VERSION 5.7 ;
BUSBITCHARS "[]" ;
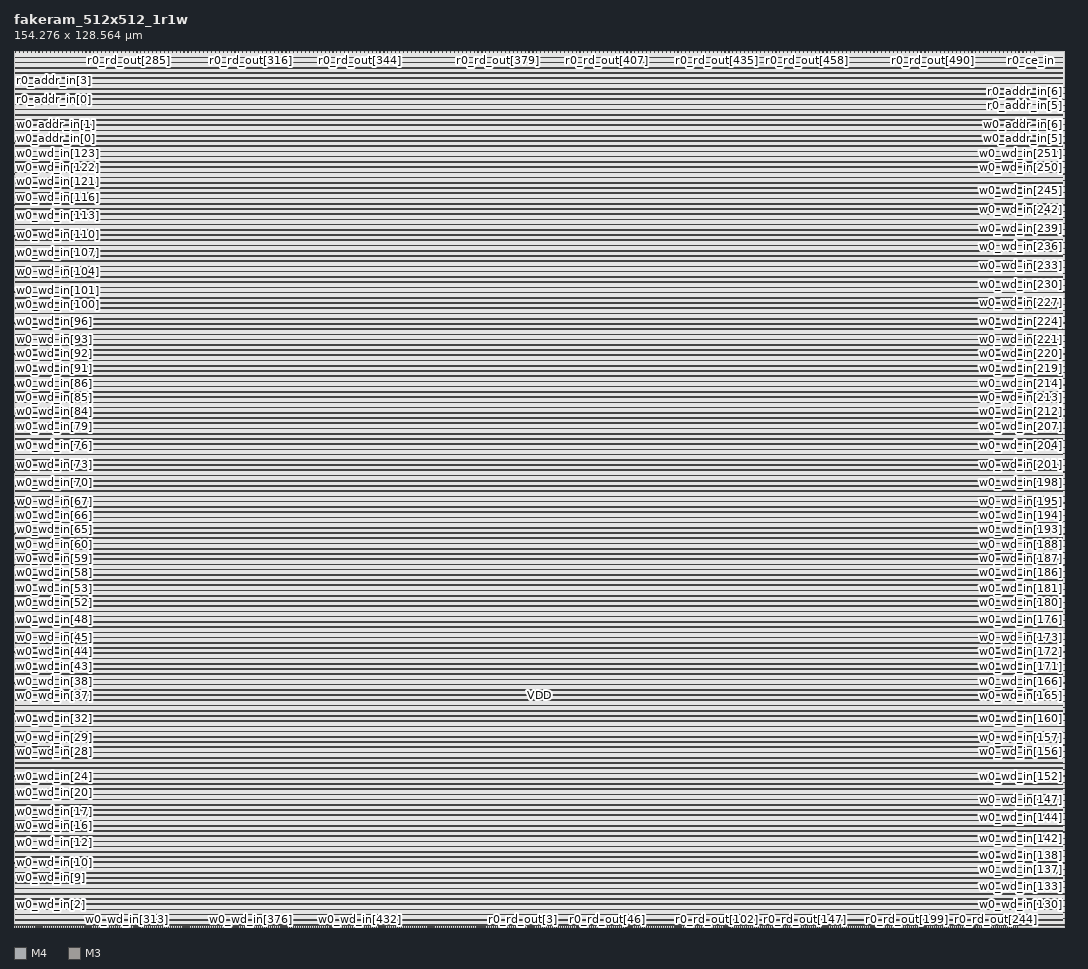
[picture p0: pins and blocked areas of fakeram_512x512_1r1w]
MACRO fakeram_512x512_1r1w
  FOREIGN fakeram_512x512_1r1w 0 0 ;
  SYMMETRY X Y R90 ;
  SIZE 154.276 BY 128.564 ;
  CLASS BLOCK ;
  PIN w0_wd_in[0]
    DIRECTION INPUT ;
    USE SIGNAL ;
    SHAPE ABUTMENT ;
    PORT
      LAYER M4 ;
      RECT 0.000 0.276 0.072 0.300 ;
    END
  END w0_wd_in[0]
  PIN w0_wd_in[1]
    DIRECTION INPUT ;
    USE SIGNAL ;
    SHAPE ABUTMENT ;
    PORT
      LAYER M4 ;
      RECT 0.000 1.188 0.072 1.212 ;
    END
  END w0_wd_in[1]
  PIN w0_wd_in[2]
    DIRECTION INPUT ;
    USE SIGNAL ;
    SHAPE ABUTMENT ;
    PORT
      LAYER M4 ;
      RECT 0.000 2.100 0.072 2.124 ;
    END
  END w0_wd_in[2]
  PIN w0_wd_in[3]
    DIRECTION INPUT ;
    USE SIGNAL ;
    SHAPE ABUTMENT ;
    PORT
      LAYER M4 ;
      RECT 0.000 3.012 0.072 3.036 ;
    END
  END w0_wd_in[3]
  PIN w0_wd_in[4]
    DIRECTION INPUT ;
    USE SIGNAL ;
    SHAPE ABUTMENT ;
    PORT
      LAYER M4 ;
      RECT 0.000 3.924 0.072 3.948 ;
    END
  END w0_wd_in[4]
  PIN w0_wd_in[5]
    DIRECTION INPUT ;
    USE SIGNAL ;
    SHAPE ABUTMENT ;
    PORT
      LAYER M4 ;
      RECT 0.000 4.836 0.072 4.860 ;
    END
  END w0_wd_in[5]
  PIN w0_wd_in[6]
    DIRECTION INPUT ;
    USE SIGNAL ;
    SHAPE ABUTMENT ;
    PORT
      LAYER M4 ;
      RECT 0.000 5.748 0.072 5.772 ;
    END
  END w0_wd_in[6]
  PIN w0_wd_in[7]
    DIRECTION INPUT ;
    USE SIGNAL ;
    SHAPE ABUTMENT ;
    PORT
      LAYER M4 ;
      RECT 0.000 6.660 0.072 6.684 ;
    END
  END w0_wd_in[7]
  PIN w0_wd_in[8]
    DIRECTION INPUT ;
    USE SIGNAL ;
    SHAPE ABUTMENT ;
    PORT
      LAYER M4 ;
      RECT 0.000 7.572 0.072 7.596 ;
    END
  END w0_wd_in[8]
  PIN w0_wd_in[9]
    DIRECTION INPUT ;
    USE SIGNAL ;
    SHAPE ABUTMENT ;
    PORT
      LAYER M4 ;
      RECT 0.000 8.484 0.072 8.508 ;
    END
  END w0_wd_in[9]
  PIN w0_wd_in[10]
    DIRECTION INPUT ;
    USE SIGNAL ;
    SHAPE ABUTMENT ;
    PORT
      LAYER M4 ;
      RECT 0.000 9.396 0.072 9.420 ;
    END
  END w0_wd_in[10]
  PIN w0_wd_in[11]
    DIRECTION INPUT ;
    USE SIGNAL ;
    SHAPE ABUTMENT ;
    PORT
      LAYER M4 ;
      RECT 0.000 10.308 0.072 10.332 ;
    END
  END w0_wd_in[11]
  PIN w0_wd_in[12]
    DIRECTION INPUT ;
    USE SIGNAL ;
    SHAPE ABUTMENT ;
    PORT
      LAYER M4 ;
      RECT 0.000 11.220 0.072 11.244 ;
    END
  END w0_wd_in[12]
  PIN w0_wd_in[13]
    DIRECTION INPUT ;
    USE SIGNAL ;
    SHAPE ABUTMENT ;
    PORT
      LAYER M4 ;
      RECT 0.000 12.132 0.072 12.156 ;
    END
  END w0_wd_in[13]
  PIN w0_wd_in[14]
    DIRECTION INPUT ;
    USE SIGNAL ;
    SHAPE ABUTMENT ;
    PORT
      LAYER M4 ;
      RECT 0.000 13.044 0.072 13.068 ;
    END
  END w0_wd_in[14]
  PIN w0_wd_in[15]
    DIRECTION INPUT ;
    USE SIGNAL ;
    SHAPE ABUTMENT ;
    PORT
      LAYER M4 ;
      RECT 0.000 13.956 0.072 13.980 ;
    END
  END w0_wd_in[15]
  PIN w0_wd_in[16]
    DIRECTION INPUT ;
    USE SIGNAL ;
    SHAPE ABUTMENT ;
    PORT
      LAYER M4 ;
      RECT 0.000 14.868 0.072 14.892 ;
    END
  END w0_wd_in[16]
  PIN w0_wd_in[17]
    DIRECTION INPUT ;
    USE SIGNAL ;
    SHAPE ABUTMENT ;
    PORT
      LAYER M4 ;
      RECT 0.000 15.780 0.072 15.804 ;
    END
  END w0_wd_in[17]
  PIN w0_wd_in[18]
    DIRECTION INPUT ;
    USE SIGNAL ;
    SHAPE ABUTMENT ;
    PORT
      LAYER M4 ;
      RECT 0.000 16.692 0.072 16.716 ;
    END
  END w0_wd_in[18]
  PIN w0_wd_in[19]
    DIRECTION INPUT ;
    USE SIGNAL ;
    SHAPE ABUTMENT ;
    PORT
      LAYER M4 ;
      RECT 0.000 17.604 0.072 17.628 ;
    END
  END w0_wd_in[19]
  PIN w0_wd_in[20]
    DIRECTION INPUT ;
    USE SIGNAL ;
    SHAPE ABUTMENT ;
    PORT
      LAYER M4 ;
      RECT 0.000 18.516 0.072 18.540 ;
    END
  END w0_wd_in[20]
  PIN w0_wd_in[21]
    DIRECTION INPUT ;
    USE SIGNAL ;
    SHAPE ABUTMENT ;
    PORT
      LAYER M4 ;
      RECT 0.000 19.428 0.072 19.452 ;
    END
  END w0_wd_in[21]
  PIN w0_wd_in[22]
    DIRECTION INPUT ;
    USE SIGNAL ;
    SHAPE ABUTMENT ;
    PORT
      LAYER M4 ;
      RECT 0.000 20.340 0.072 20.364 ;
    END
  END w0_wd_in[22]
  PIN w0_wd_in[23]
    DIRECTION INPUT ;
    USE SIGNAL ;
    SHAPE ABUTMENT ;
    PORT
      LAYER M4 ;
      RECT 0.000 21.252 0.072 21.276 ;
    END
  END w0_wd_in[23]
  PIN w0_wd_in[24]
    DIRECTION INPUT ;
    USE SIGNAL ;
    SHAPE ABUTMENT ;
    PORT
      LAYER M4 ;
      RECT 0.000 22.164 0.072 22.188 ;
    END
  END w0_wd_in[24]
  PIN w0_wd_in[25]
    DIRECTION INPUT ;
    USE SIGNAL ;
    SHAPE ABUTMENT ;
    PORT
      LAYER M4 ;
      RECT 0.000 23.076 0.072 23.100 ;
    END
  END w0_wd_in[25]
  PIN w0_wd_in[26]
    DIRECTION INPUT ;
    USE SIGNAL ;
    SHAPE ABUTMENT ;
    PORT
      LAYER M4 ;
      RECT 0.000 23.988 0.072 24.012 ;
    END
  END w0_wd_in[26]
  PIN w0_wd_in[27]
    DIRECTION INPUT ;
    USE SIGNAL ;
    SHAPE ABUTMENT ;
    PORT
      LAYER M4 ;
      RECT 0.000 24.900 0.072 24.924 ;
    END
  END w0_wd_in[27]
  PIN w0_wd_in[28]
    DIRECTION INPUT ;
    USE SIGNAL ;
    SHAPE ABUTMENT ;
    PORT
      LAYER M4 ;
      RECT 0.000 25.812 0.072 25.836 ;
    END
  END w0_wd_in[28]
  PIN w0_wd_in[29]
    DIRECTION INPUT ;
    USE SIGNAL ;
    SHAPE ABUTMENT ;
    PORT
      LAYER M4 ;
      RECT 0.000 26.724 0.072 26.748 ;
    END
  END w0_wd_in[29]
  PIN w0_wd_in[30]
    DIRECTION INPUT ;
    USE SIGNAL ;
    SHAPE ABUTMENT ;
    PORT
      LAYER M4 ;
      RECT 0.000 27.636 0.072 27.660 ;
    END
  END w0_wd_in[30]
  PIN w0_wd_in[31]
    DIRECTION INPUT ;
    USE SIGNAL ;
    SHAPE ABUTMENT ;
    PORT
      LAYER M4 ;
      RECT 0.000 28.548 0.072 28.572 ;
    END
  END w0_wd_in[31]
  PIN w0_wd_in[32]
    DIRECTION INPUT ;
    USE SIGNAL ;
    SHAPE ABUTMENT ;
    PORT
      LAYER M4 ;
      RECT 0.000 29.460 0.072 29.484 ;
    END
  END w0_wd_in[32]
  PIN w0_wd_in[33]
    DIRECTION INPUT ;
    USE SIGNAL ;
    SHAPE ABUTMENT ;
    PORT
      LAYER M4 ;
      RECT 0.000 30.372 0.072 30.396 ;
    END
  END w0_wd_in[33]
  PIN w0_wd_in[34]
    DIRECTION INPUT ;
    USE SIGNAL ;
    SHAPE ABUTMENT ;
    PORT
      LAYER M4 ;
      RECT 0.000 31.284 0.072 31.308 ;
    END
  END w0_wd_in[34]
  PIN w0_wd_in[35]
    DIRECTION INPUT ;
    USE SIGNAL ;
    SHAPE ABUTMENT ;
    PORT
      LAYER M4 ;
      RECT 0.000 32.196 0.072 32.220 ;
    END
  END w0_wd_in[35]
  PIN w0_wd_in[36]
    DIRECTION INPUT ;
    USE SIGNAL ;
    SHAPE ABUTMENT ;
    PORT
      LAYER M4 ;
      RECT 0.000 33.108 0.072 33.132 ;
    END
  END w0_wd_in[36]
  PIN w0_wd_in[37]
    DIRECTION INPUT ;
    USE SIGNAL ;
    SHAPE ABUTMENT ;
    PORT
      LAYER M4 ;
      RECT 0.000 34.020 0.072 34.044 ;
    END
  END w0_wd_in[37]
  PIN w0_wd_in[38]
    DIRECTION INPUT ;
    USE SIGNAL ;
    SHAPE ABUTMENT ;
    PORT
      LAYER M4 ;
      RECT 0.000 34.932 0.072 34.956 ;
    END
  END w0_wd_in[38]
  PIN w0_wd_in[39]
    DIRECTION INPUT ;
    USE SIGNAL ;
    SHAPE ABUTMENT ;
    PORT
      LAYER M4 ;
      RECT 0.000 35.844 0.072 35.868 ;
    END
  END w0_wd_in[39]
  PIN w0_wd_in[40]
    DIRECTION INPUT ;
    USE SIGNAL ;
    SHAPE ABUTMENT ;
    PORT
      LAYER M4 ;
      RECT 0.000 36.756 0.072 36.780 ;
    END
  END w0_wd_in[40]
  PIN w0_wd_in[41]
    DIRECTION INPUT ;
    USE SIGNAL ;
    SHAPE ABUTMENT ;
    PORT
      LAYER M4 ;
      RECT 0.000 37.668 0.072 37.692 ;
    END
  END w0_wd_in[41]
  PIN w0_wd_in[42]
    DIRECTION INPUT ;
    USE SIGNAL ;
    SHAPE ABUTMENT ;
    PORT
      LAYER M4 ;
      RECT 0.000 38.580 0.072 38.604 ;
    END
  END w0_wd_in[42]
  PIN w0_wd_in[43]
    DIRECTION INPUT ;
    USE SIGNAL ;
    SHAPE ABUTMENT ;
    PORT
      LAYER M4 ;
      RECT 0.000 39.492 0.072 39.516 ;
    END
  END w0_wd_in[43]
  PIN w0_wd_in[44]
    DIRECTION INPUT ;
    USE SIGNAL ;
    SHAPE ABUTMENT ;
    PORT
      LAYER M4 ;
      RECT 0.000 40.404 0.072 40.428 ;
    END
  END w0_wd_in[44]
  PIN w0_wd_in[45]
    DIRECTION INPUT ;
    USE SIGNAL ;
    SHAPE ABUTMENT ;
    PORT
      LAYER M4 ;
      RECT 0.000 41.316 0.072 41.340 ;
    END
  END w0_wd_in[45]
  PIN w0_wd_in[46]
    DIRECTION INPUT ;
    USE SIGNAL ;
    SHAPE ABUTMENT ;
    PORT
      LAYER M4 ;
      RECT 0.000 42.228 0.072 42.252 ;
    END
  END w0_wd_in[46]
  PIN w0_wd_in[47]
    DIRECTION INPUT ;
    USE SIGNAL ;
    SHAPE ABUTMENT ;
    PORT
      LAYER M4 ;
      RECT 0.000 43.140 0.072 43.164 ;
    END
  END w0_wd_in[47]
  PIN w0_wd_in[48]
    DIRECTION INPUT ;
    USE SIGNAL ;
    SHAPE ABUTMENT ;
    PORT
      LAYER M4 ;
      RECT 0.000 44.052 0.072 44.076 ;
    END
  END w0_wd_in[48]
  PIN w0_wd_in[49]
    DIRECTION INPUT ;
    USE SIGNAL ;
    SHAPE ABUTMENT ;
    PORT
      LAYER M4 ;
      RECT 0.000 44.964 0.072 44.988 ;
    END
  END w0_wd_in[49]
  PIN w0_wd_in[50]
    DIRECTION INPUT ;
    USE SIGNAL ;
    SHAPE ABUTMENT ;
    PORT
      LAYER M4 ;
      RECT 0.000 45.876 0.072 45.900 ;
    END
  END w0_wd_in[50]
  PIN w0_wd_in[51]
    DIRECTION INPUT ;
    USE SIGNAL ;
    SHAPE ABUTMENT ;
    PORT
      LAYER M4 ;
      RECT 0.000 46.788 0.072 46.812 ;
    END
  END w0_wd_in[51]
  PIN w0_wd_in[52]
    DIRECTION INPUT ;
    USE SIGNAL ;
    SHAPE ABUTMENT ;
    PORT
      LAYER M4 ;
      RECT 0.000 47.700 0.072 47.724 ;
    END
  END w0_wd_in[52]
  PIN w0_wd_in[53]
    DIRECTION INPUT ;
    USE SIGNAL ;
    SHAPE ABUTMENT ;
    PORT
      LAYER M4 ;
      RECT 0.000 48.612 0.072 48.636 ;
    END
  END w0_wd_in[53]
  PIN w0_wd_in[54]
    DIRECTION INPUT ;
    USE SIGNAL ;
    SHAPE ABUTMENT ;
    PORT
      LAYER M4 ;
      RECT 0.000 49.524 0.072 49.548 ;
    END
  END w0_wd_in[54]
  PIN w0_wd_in[55]
    DIRECTION INPUT ;
    USE SIGNAL ;
    SHAPE ABUTMENT ;
    PORT
      LAYER M4 ;
      RECT 0.000 50.436 0.072 50.460 ;
    END
  END w0_wd_in[55]
  PIN w0_wd_in[56]
    DIRECTION INPUT ;
    USE SIGNAL ;
    SHAPE ABUTMENT ;
    PORT
      LAYER M4 ;
      RECT 0.000 51.348 0.072 51.372 ;
    END
  END w0_wd_in[56]
  PIN w0_wd_in[57]
    DIRECTION INPUT ;
    USE SIGNAL ;
    SHAPE ABUTMENT ;
    PORT
      LAYER M4 ;
      RECT 0.000 52.260 0.072 52.284 ;
    END
  END w0_wd_in[57]
  PIN w0_wd_in[58]
    DIRECTION INPUT ;
    USE SIGNAL ;
    SHAPE ABUTMENT ;
    PORT
      LAYER M4 ;
      RECT 0.000 53.172 0.072 53.196 ;
    END
  END w0_wd_in[58]
  PIN w0_wd_in[59]
    DIRECTION INPUT ;
    USE SIGNAL ;
    SHAPE ABUTMENT ;
    PORT
      LAYER M4 ;
      RECT 0.000 54.084 0.072 54.108 ;
    END
  END w0_wd_in[59]
  PIN w0_wd_in[60]
    DIRECTION INPUT ;
    USE SIGNAL ;
    SHAPE ABUTMENT ;
    PORT
      LAYER M4 ;
      RECT 0.000 54.996 0.072 55.020 ;
    END
  END w0_wd_in[60]
  PIN w0_wd_in[61]
    DIRECTION INPUT ;
    USE SIGNAL ;
    SHAPE ABUTMENT ;
    PORT
      LAYER M4 ;
      RECT 0.000 55.908 0.072 55.932 ;
    END
  END w0_wd_in[61]
  PIN w0_wd_in[62]
    DIRECTION INPUT ;
    USE SIGNAL ;
    SHAPE ABUTMENT ;
    PORT
      LAYER M4 ;
      RECT 0.000 56.820 0.072 56.844 ;
    END
  END w0_wd_in[62]
  PIN w0_wd_in[63]
    DIRECTION INPUT ;
    USE SIGNAL ;
    SHAPE ABUTMENT ;
    PORT
      LAYER M4 ;
      RECT 0.000 57.732 0.072 57.756 ;
    END
  END w0_wd_in[63]
  PIN w0_wd_in[64]
    DIRECTION INPUT ;
    USE SIGNAL ;
    SHAPE ABUTMENT ;
    PORT
      LAYER M4 ;
      RECT 0.000 58.644 0.072 58.668 ;
    END
  END w0_wd_in[64]
  PIN w0_wd_in[65]
    DIRECTION INPUT ;
    USE SIGNAL ;
    SHAPE ABUTMENT ;
    PORT
      LAYER M4 ;
      RECT 0.000 59.556 0.072 59.580 ;
    END
  END w0_wd_in[65]
  PIN w0_wd_in[66]
    DIRECTION INPUT ;
    USE SIGNAL ;
    SHAPE ABUTMENT ;
    PORT
      LAYER M4 ;
      RECT 0.000 60.468 0.072 60.492 ;
    END
  END w0_wd_in[66]
  PIN w0_wd_in[67]
    DIRECTION INPUT ;
    USE SIGNAL ;
    SHAPE ABUTMENT ;
    PORT
      LAYER M4 ;
      RECT 0.000 61.380 0.072 61.404 ;
    END
  END w0_wd_in[67]
  PIN w0_wd_in[68]
    DIRECTION INPUT ;
    USE SIGNAL ;
    SHAPE ABUTMENT ;
    PORT
      LAYER M4 ;
      RECT 0.000 62.292 0.072 62.316 ;
    END
  END w0_wd_in[68]
  PIN w0_wd_in[69]
    DIRECTION INPUT ;
    USE SIGNAL ;
    SHAPE ABUTMENT ;
    PORT
      LAYER M4 ;
      RECT 0.000 63.204 0.072 63.228 ;
    END
  END w0_wd_in[69]
  PIN w0_wd_in[70]
    DIRECTION INPUT ;
    USE SIGNAL ;
    SHAPE ABUTMENT ;
    PORT
      LAYER M4 ;
      RECT 0.000 64.116 0.072 64.140 ;
    END
  END w0_wd_in[70]
  PIN w0_wd_in[71]
    DIRECTION INPUT ;
    USE SIGNAL ;
    SHAPE ABUTMENT ;
    PORT
      LAYER M4 ;
      RECT 0.000 65.028 0.072 65.052 ;
    END
  END w0_wd_in[71]
  PIN w0_wd_in[72]
    DIRECTION INPUT ;
    USE SIGNAL ;
    SHAPE ABUTMENT ;
    PORT
      LAYER M4 ;
      RECT 0.000 65.940 0.072 65.964 ;
    END
  END w0_wd_in[72]
  PIN w0_wd_in[73]
    DIRECTION INPUT ;
    USE SIGNAL ;
    SHAPE ABUTMENT ;
    PORT
      LAYER M4 ;
      RECT 0.000 66.852 0.072 66.876 ;
    END
  END w0_wd_in[73]
  PIN w0_wd_in[74]
    DIRECTION INPUT ;
    USE SIGNAL ;
    SHAPE ABUTMENT ;
    PORT
      LAYER M4 ;
      RECT 0.000 67.764 0.072 67.788 ;
    END
  END w0_wd_in[74]
  PIN w0_wd_in[75]
    DIRECTION INPUT ;
    USE SIGNAL ;
    SHAPE ABUTMENT ;
    PORT
      LAYER M4 ;
      RECT 0.000 68.676 0.072 68.700 ;
    END
  END w0_wd_in[75]
  PIN w0_wd_in[76]
    DIRECTION INPUT ;
    USE SIGNAL ;
    SHAPE ABUTMENT ;
    PORT
      LAYER M4 ;
      RECT 0.000 69.588 0.072 69.612 ;
    END
  END w0_wd_in[76]
  PIN w0_wd_in[77]
    DIRECTION INPUT ;
    USE SIGNAL ;
    SHAPE ABUTMENT ;
    PORT
      LAYER M4 ;
      RECT 0.000 70.500 0.072 70.524 ;
    END
  END w0_wd_in[77]
  PIN w0_wd_in[78]
    DIRECTION INPUT ;
    USE SIGNAL ;
    SHAPE ABUTMENT ;
    PORT
      LAYER M4 ;
      RECT 0.000 71.412 0.072 71.436 ;
    END
  END w0_wd_in[78]
  PIN w0_wd_in[79]
    DIRECTION INPUT ;
    USE SIGNAL ;
    SHAPE ABUTMENT ;
    PORT
      LAYER M4 ;
      RECT 0.000 72.324 0.072 72.348 ;
    END
  END w0_wd_in[79]
  PIN w0_wd_in[80]
    DIRECTION INPUT ;
    USE SIGNAL ;
    SHAPE ABUTMENT ;
    PORT
      LAYER M4 ;
      RECT 0.000 73.236 0.072 73.260 ;
    END
  END w0_wd_in[80]
  PIN w0_wd_in[81]
    DIRECTION INPUT ;
    USE SIGNAL ;
    SHAPE ABUTMENT ;
    PORT
      LAYER M4 ;
      RECT 0.000 74.148 0.072 74.172 ;
    END
  END w0_wd_in[81]
  PIN w0_wd_in[82]
    DIRECTION INPUT ;
    USE SIGNAL ;
    SHAPE ABUTMENT ;
    PORT
      LAYER M4 ;
      RECT 0.000 75.060 0.072 75.084 ;
    END
  END w0_wd_in[82]
  PIN w0_wd_in[83]
    DIRECTION INPUT ;
    USE SIGNAL ;
    SHAPE ABUTMENT ;
    PORT
      LAYER M4 ;
      RECT 0.000 75.972 0.072 75.996 ;
    END
  END w0_wd_in[83]
  PIN w0_wd_in[84]
    DIRECTION INPUT ;
    USE SIGNAL ;
    SHAPE ABUTMENT ;
    PORT
      LAYER M4 ;
      RECT 0.000 76.884 0.072 76.908 ;
    END
  END w0_wd_in[84]
  PIN w0_wd_in[85]
    DIRECTION INPUT ;
    USE SIGNAL ;
    SHAPE ABUTMENT ;
    PORT
      LAYER M4 ;
      RECT 0.000 77.796 0.072 77.820 ;
    END
  END w0_wd_in[85]
  PIN w0_wd_in[86]
    DIRECTION INPUT ;
    USE SIGNAL ;
    SHAPE ABUTMENT ;
    PORT
      LAYER M4 ;
      RECT 0.000 78.708 0.072 78.732 ;
    END
  END w0_wd_in[86]
  PIN w0_wd_in[87]
    DIRECTION INPUT ;
    USE SIGNAL ;
    SHAPE ABUTMENT ;
    PORT
      LAYER M4 ;
      RECT 0.000 79.620 0.072 79.644 ;
    END
  END w0_wd_in[87]
  PIN w0_wd_in[88]
    DIRECTION INPUT ;
    USE SIGNAL ;
    SHAPE ABUTMENT ;
    PORT
      LAYER M4 ;
      RECT 0.000 80.532 0.072 80.556 ;
    END
  END w0_wd_in[88]
  PIN w0_wd_in[89]
    DIRECTION INPUT ;
    USE SIGNAL ;
    SHAPE ABUTMENT ;
    PORT
      LAYER M4 ;
      RECT 0.000 81.444 0.072 81.468 ;
    END
  END w0_wd_in[89]
  PIN w0_wd_in[90]
    DIRECTION INPUT ;
    USE SIGNAL ;
    SHAPE ABUTMENT ;
    PORT
      LAYER M4 ;
      RECT 0.000 82.356 0.072 82.380 ;
    END
  END w0_wd_in[90]
  PIN w0_wd_in[91]
    DIRECTION INPUT ;
    USE SIGNAL ;
    SHAPE ABUTMENT ;
    PORT
      LAYER M4 ;
      RECT 0.000 83.268 0.072 83.292 ;
    END
  END w0_wd_in[91]
  PIN w0_wd_in[92]
    DIRECTION INPUT ;
    USE SIGNAL ;
    SHAPE ABUTMENT ;
    PORT
      LAYER M4 ;
      RECT 0.000 84.180 0.072 84.204 ;
    END
  END w0_wd_in[92]
  PIN w0_wd_in[93]
    DIRECTION INPUT ;
    USE SIGNAL ;
    SHAPE ABUTMENT ;
    PORT
      LAYER M4 ;
      RECT 0.000 85.092 0.072 85.116 ;
    END
  END w0_wd_in[93]
  PIN w0_wd_in[94]
    DIRECTION INPUT ;
    USE SIGNAL ;
    SHAPE ABUTMENT ;
    PORT
      LAYER M4 ;
      RECT 0.000 86.004 0.072 86.028 ;
    END
  END w0_wd_in[94]
  PIN w0_wd_in[95]
    DIRECTION INPUT ;
    USE SIGNAL ;
    SHAPE ABUTMENT ;
    PORT
      LAYER M4 ;
      RECT 0.000 86.916 0.072 86.940 ;
    END
  END w0_wd_in[95]
  PIN w0_wd_in[96]
    DIRECTION INPUT ;
    USE SIGNAL ;
    SHAPE ABUTMENT ;
    PORT
      LAYER M4 ;
      RECT 0.000 87.828 0.072 87.852 ;
    END
  END w0_wd_in[96]
  PIN w0_wd_in[97]
    DIRECTION INPUT ;
    USE SIGNAL ;
    SHAPE ABUTMENT ;
    PORT
      LAYER M4 ;
      RECT 0.000 88.740 0.072 88.764 ;
    END
  END w0_wd_in[97]
  PIN w0_wd_in[98]
    DIRECTION INPUT ;
    USE SIGNAL ;
    SHAPE ABUTMENT ;
    PORT
      LAYER M4 ;
      RECT 0.000 89.652 0.072 89.676 ;
    END
  END w0_wd_in[98]
  PIN w0_wd_in[99]
    DIRECTION INPUT ;
    USE SIGNAL ;
    SHAPE ABUTMENT ;
    PORT
      LAYER M4 ;
      RECT 0.000 90.564 0.072 90.588 ;
    END
  END w0_wd_in[99]
  PIN w0_wd_in[100]
    DIRECTION INPUT ;
    USE SIGNAL ;
    SHAPE ABUTMENT ;
    PORT
      LAYER M4 ;
      RECT 0.000 91.476 0.072 91.500 ;
    END
  END w0_wd_in[100]
  PIN w0_wd_in[101]
    DIRECTION INPUT ;
    USE SIGNAL ;
    SHAPE ABUTMENT ;
    PORT
      LAYER M4 ;
      RECT 0.000 92.388 0.072 92.412 ;
    END
  END w0_wd_in[101]
  PIN w0_wd_in[102]
    DIRECTION INPUT ;
    USE SIGNAL ;
    SHAPE ABUTMENT ;
    PORT
      LAYER M4 ;
      RECT 0.000 93.300 0.072 93.324 ;
    END
  END w0_wd_in[102]
  PIN w0_wd_in[103]
    DIRECTION INPUT ;
    USE SIGNAL ;
    SHAPE ABUTMENT ;
    PORT
      LAYER M4 ;
      RECT 0.000 94.212 0.072 94.236 ;
    END
  END w0_wd_in[103]
  PIN w0_wd_in[104]
    DIRECTION INPUT ;
    USE SIGNAL ;
    SHAPE ABUTMENT ;
    PORT
      LAYER M4 ;
      RECT 0.000 95.124 0.072 95.148 ;
    END
  END w0_wd_in[104]
  PIN w0_wd_in[105]
    DIRECTION INPUT ;
    USE SIGNAL ;
    SHAPE ABUTMENT ;
    PORT
      LAYER M4 ;
      RECT 0.000 96.036 0.072 96.060 ;
    END
  END w0_wd_in[105]
  PIN w0_wd_in[106]
    DIRECTION INPUT ;
    USE SIGNAL ;
    SHAPE ABUTMENT ;
    PORT
      LAYER M4 ;
      RECT 0.000 96.948 0.072 96.972 ;
    END
  END w0_wd_in[106]
  PIN w0_wd_in[107]
    DIRECTION INPUT ;
    USE SIGNAL ;
    SHAPE ABUTMENT ;
    PORT
      LAYER M4 ;
      RECT 0.000 97.860 0.072 97.884 ;
    END
  END w0_wd_in[107]
  PIN w0_wd_in[108]
    DIRECTION INPUT ;
    USE SIGNAL ;
    SHAPE ABUTMENT ;
    PORT
      LAYER M4 ;
      RECT 0.000 98.772 0.072 98.796 ;
    END
  END w0_wd_in[108]
  PIN w0_wd_in[109]
    DIRECTION INPUT ;
    USE SIGNAL ;
    SHAPE ABUTMENT ;
    PORT
      LAYER M4 ;
      RECT 0.000 99.684 0.072 99.708 ;
    END
  END w0_wd_in[109]
  PIN w0_wd_in[110]
    DIRECTION INPUT ;
    USE SIGNAL ;
    SHAPE ABUTMENT ;
    PORT
      LAYER M4 ;
      RECT 0.000 100.596 0.072 100.620 ;
    END
  END w0_wd_in[110]
  PIN w0_wd_in[111]
    DIRECTION INPUT ;
    USE SIGNAL ;
    SHAPE ABUTMENT ;
    PORT
      LAYER M4 ;
      RECT 0.000 101.508 0.072 101.532 ;
    END
  END w0_wd_in[111]
  PIN w0_wd_in[112]
    DIRECTION INPUT ;
    USE SIGNAL ;
    SHAPE ABUTMENT ;
    PORT
      LAYER M4 ;
      RECT 0.000 102.420 0.072 102.444 ;
    END
  END w0_wd_in[112]
  PIN w0_wd_in[113]
    DIRECTION INPUT ;
    USE SIGNAL ;
    SHAPE ABUTMENT ;
    PORT
      LAYER M4 ;
      RECT 0.000 103.332 0.072 103.356 ;
    END
  END w0_wd_in[113]
  PIN w0_wd_in[114]
    DIRECTION INPUT ;
    USE SIGNAL ;
    SHAPE ABUTMENT ;
    PORT
      LAYER M4 ;
      RECT 0.000 104.244 0.072 104.268 ;
    END
  END w0_wd_in[114]
  PIN w0_wd_in[115]
    DIRECTION INPUT ;
    USE SIGNAL ;
    SHAPE ABUTMENT ;
    PORT
      LAYER M4 ;
      RECT 0.000 105.156 0.072 105.180 ;
    END
  END w0_wd_in[115]
  PIN w0_wd_in[116]
    DIRECTION INPUT ;
    USE SIGNAL ;
    SHAPE ABUTMENT ;
    PORT
      LAYER M4 ;
      RECT 0.000 106.068 0.072 106.092 ;
    END
  END w0_wd_in[116]
  PIN w0_wd_in[117]
    DIRECTION INPUT ;
    USE SIGNAL ;
    SHAPE ABUTMENT ;
    PORT
      LAYER M4 ;
      RECT 0.000 106.980 0.072 107.004 ;
    END
  END w0_wd_in[117]
  PIN w0_wd_in[118]
    DIRECTION INPUT ;
    USE SIGNAL ;
    SHAPE ABUTMENT ;
    PORT
      LAYER M4 ;
      RECT 0.000 107.892 0.072 107.916 ;
    END
  END w0_wd_in[118]
  PIN w0_wd_in[119]
    DIRECTION INPUT ;
    USE SIGNAL ;
    SHAPE ABUTMENT ;
    PORT
      LAYER M4 ;
      RECT 0.000 108.804 0.072 108.828 ;
    END
  END w0_wd_in[119]
  PIN w0_wd_in[120]
    DIRECTION INPUT ;
    USE SIGNAL ;
    SHAPE ABUTMENT ;
    PORT
      LAYER M4 ;
      RECT 0.000 109.716 0.072 109.740 ;
    END
  END w0_wd_in[120]
  PIN w0_wd_in[121]
    DIRECTION INPUT ;
    USE SIGNAL ;
    SHAPE ABUTMENT ;
    PORT
      LAYER M4 ;
      RECT 0.000 110.628 0.072 110.652 ;
    END
  END w0_wd_in[121]
  PIN w0_wd_in[122]
    DIRECTION INPUT ;
    USE SIGNAL ;
    SHAPE ABUTMENT ;
    PORT
      LAYER M4 ;
      RECT 0.000 111.540 0.072 111.564 ;
    END
  END w0_wd_in[122]
  PIN w0_wd_in[123]
    DIRECTION INPUT ;
    USE SIGNAL ;
    SHAPE ABUTMENT ;
    PORT
      LAYER M4 ;
      RECT 0.000 112.452 0.072 112.476 ;
    END
  END w0_wd_in[123]
  PIN w0_wd_in[124]
    DIRECTION INPUT ;
    USE SIGNAL ;
    SHAPE ABUTMENT ;
    PORT
      LAYER M4 ;
      RECT 0.000 113.364 0.072 113.388 ;
    END
  END w0_wd_in[124]
  PIN w0_wd_in[125]
    DIRECTION INPUT ;
    USE SIGNAL ;
    SHAPE ABUTMENT ;
    PORT
      LAYER M4 ;
      RECT 0.000 114.276 0.072 114.300 ;
    END
  END w0_wd_in[125]
  PIN w0_wd_in[126]
    DIRECTION INPUT ;
    USE SIGNAL ;
    SHAPE ABUTMENT ;
    PORT
      LAYER M4 ;
      RECT 0.000 115.188 0.072 115.212 ;
    END
  END w0_wd_in[126]
  PIN w0_wd_in[127]
    DIRECTION INPUT ;
    USE SIGNAL ;
    SHAPE ABUTMENT ;
    PORT
      LAYER M4 ;
      RECT 0.000 116.100 0.072 116.124 ;
    END
  END w0_wd_in[127]
  PIN w0_wd_in[128]
    DIRECTION INPUT ;
    USE SIGNAL ;
    SHAPE ABUTMENT ;
    PORT
      LAYER M4 ;
      RECT 154.204 0.276 154.276 0.300 ;
    END
  END w0_wd_in[128]
  PIN w0_wd_in[129]
    DIRECTION INPUT ;
    USE SIGNAL ;
    SHAPE ABUTMENT ;
    PORT
      LAYER M4 ;
      RECT 154.204 1.188 154.276 1.212 ;
    END
  END w0_wd_in[129]
  PIN w0_wd_in[130]
    DIRECTION INPUT ;
    USE SIGNAL ;
    SHAPE ABUTMENT ;
    PORT
      LAYER M4 ;
      RECT 154.204 2.100 154.276 2.124 ;
    END
  END w0_wd_in[130]
  PIN w0_wd_in[131]
    DIRECTION INPUT ;
    USE SIGNAL ;
    SHAPE ABUTMENT ;
    PORT
      LAYER M4 ;
      RECT 154.204 3.012 154.276 3.036 ;
    END
  END w0_wd_in[131]
  PIN w0_wd_in[132]
    DIRECTION INPUT ;
    USE SIGNAL ;
    SHAPE ABUTMENT ;
    PORT
      LAYER M4 ;
      RECT 154.204 3.924 154.276 3.948 ;
    END
  END w0_wd_in[132]
  PIN w0_wd_in[133]
    DIRECTION INPUT ;
    USE SIGNAL ;
    SHAPE ABUTMENT ;
    PORT
      LAYER M4 ;
      RECT 154.204 4.836 154.276 4.860 ;
    END
  END w0_wd_in[133]
  PIN w0_wd_in[134]
    DIRECTION INPUT ;
    USE SIGNAL ;
    SHAPE ABUTMENT ;
    PORT
      LAYER M4 ;
      RECT 154.204 5.748 154.276 5.772 ;
    END
  END w0_wd_in[134]
  PIN w0_wd_in[135]
    DIRECTION INPUT ;
    USE SIGNAL ;
    SHAPE ABUTMENT ;
    PORT
      LAYER M4 ;
      RECT 154.204 6.660 154.276 6.684 ;
    END
  END w0_wd_in[135]
  PIN w0_wd_in[136]
    DIRECTION INPUT ;
    USE SIGNAL ;
    SHAPE ABUTMENT ;
    PORT
      LAYER M4 ;
      RECT 154.204 7.572 154.276 7.596 ;
    END
  END w0_wd_in[136]
  PIN w0_wd_in[137]
    DIRECTION INPUT ;
    USE SIGNAL ;
    SHAPE ABUTMENT ;
    PORT
      LAYER M4 ;
      RECT 154.204 8.484 154.276 8.508 ;
    END
  END w0_wd_in[137]
  PIN w0_wd_in[138]
    DIRECTION INPUT ;
    USE SIGNAL ;
    SHAPE ABUTMENT ;
    PORT
      LAYER M4 ;
      RECT 154.204 9.396 154.276 9.420 ;
    END
  END w0_wd_in[138]
  PIN w0_wd_in[139]
    DIRECTION INPUT ;
    USE SIGNAL ;
    SHAPE ABUTMENT ;
    PORT
      LAYER M4 ;
      RECT 154.204 10.308 154.276 10.332 ;
    END
  END w0_wd_in[139]
  PIN w0_wd_in[140]
    DIRECTION INPUT ;
    USE SIGNAL ;
    SHAPE ABUTMENT ;
    PORT
      LAYER M4 ;
      RECT 154.204 11.220 154.276 11.244 ;
    END
  END w0_wd_in[140]
  PIN w0_wd_in[141]
    DIRECTION INPUT ;
    USE SIGNAL ;
    SHAPE ABUTMENT ;
    PORT
      LAYER M4 ;
      RECT 154.204 12.132 154.276 12.156 ;
    END
  END w0_wd_in[141]
  PIN w0_wd_in[142]
    DIRECTION INPUT ;
    USE SIGNAL ;
    SHAPE ABUTMENT ;
    PORT
      LAYER M4 ;
      RECT 154.204 13.044 154.276 13.068 ;
    END
  END w0_wd_in[142]
  PIN w0_wd_in[143]
    DIRECTION INPUT ;
    USE SIGNAL ;
    SHAPE ABUTMENT ;
    PORT
      LAYER M4 ;
      RECT 154.204 13.956 154.276 13.980 ;
    END
  END w0_wd_in[143]
  PIN w0_wd_in[144]
    DIRECTION INPUT ;
    USE SIGNAL ;
    SHAPE ABUTMENT ;
    PORT
      LAYER M4 ;
      RECT 154.204 14.868 154.276 14.892 ;
    END
  END w0_wd_in[144]
  PIN w0_wd_in[145]
    DIRECTION INPUT ;
    USE SIGNAL ;
    SHAPE ABUTMENT ;
    PORT
      LAYER M4 ;
      RECT 154.204 15.780 154.276 15.804 ;
    END
  END w0_wd_in[145]
  PIN w0_wd_in[146]
    DIRECTION INPUT ;
    USE SIGNAL ;
    SHAPE ABUTMENT ;
    PORT
      LAYER M4 ;
      RECT 154.204 16.692 154.276 16.716 ;
    END
  END w0_wd_in[146]
  PIN w0_wd_in[147]
    DIRECTION INPUT ;
    USE SIGNAL ;
    SHAPE ABUTMENT ;
    PORT
      LAYER M4 ;
      RECT 154.204 17.604 154.276 17.628 ;
    END
  END w0_wd_in[147]
  PIN w0_wd_in[148]
    DIRECTION INPUT ;
    USE SIGNAL ;
    SHAPE ABUTMENT ;
    PORT
      LAYER M4 ;
      RECT 154.204 18.516 154.276 18.540 ;
    END
  END w0_wd_in[148]
  PIN w0_wd_in[149]
    DIRECTION INPUT ;
    USE SIGNAL ;
    SHAPE ABUTMENT ;
    PORT
      LAYER M4 ;
      RECT 154.204 19.428 154.276 19.452 ;
    END
  END w0_wd_in[149]
  PIN w0_wd_in[150]
    DIRECTION INPUT ;
    USE SIGNAL ;
    SHAPE ABUTMENT ;
    PORT
      LAYER M4 ;
      RECT 154.204 20.340 154.276 20.364 ;
    END
  END w0_wd_in[150]
  PIN w0_wd_in[151]
    DIRECTION INPUT ;
    USE SIGNAL ;
    SHAPE ABUTMENT ;
    PORT
      LAYER M4 ;
      RECT 154.204 21.252 154.276 21.276 ;
    END
  END w0_wd_in[151]
  PIN w0_wd_in[152]
    DIRECTION INPUT ;
    USE SIGNAL ;
    SHAPE ABUTMENT ;
    PORT
      LAYER M4 ;
      RECT 154.204 22.164 154.276 22.188 ;
    END
  END w0_wd_in[152]
  PIN w0_wd_in[153]
    DIRECTION INPUT ;
    USE SIGNAL ;
    SHAPE ABUTMENT ;
    PORT
      LAYER M4 ;
      RECT 154.204 23.076 154.276 23.100 ;
    END
  END w0_wd_in[153]
  PIN w0_wd_in[154]
    DIRECTION INPUT ;
    USE SIGNAL ;
    SHAPE ABUTMENT ;
    PORT
      LAYER M4 ;
      RECT 154.204 23.988 154.276 24.012 ;
    END
  END w0_wd_in[154]
  PIN w0_wd_in[155]
    DIRECTION INPUT ;
    USE SIGNAL ;
    SHAPE ABUTMENT ;
    PORT
      LAYER M4 ;
      RECT 154.204 24.900 154.276 24.924 ;
    END
  END w0_wd_in[155]
  PIN w0_wd_in[156]
    DIRECTION INPUT ;
    USE SIGNAL ;
    SHAPE ABUTMENT ;
    PORT
      LAYER M4 ;
      RECT 154.204 25.812 154.276 25.836 ;
    END
  END w0_wd_in[156]
  PIN w0_wd_in[157]
    DIRECTION INPUT ;
    USE SIGNAL ;
    SHAPE ABUTMENT ;
    PORT
      LAYER M4 ;
      RECT 154.204 26.724 154.276 26.748 ;
    END
  END w0_wd_in[157]
  PIN w0_wd_in[158]
    DIRECTION INPUT ;
    USE SIGNAL ;
    SHAPE ABUTMENT ;
    PORT
      LAYER M4 ;
      RECT 154.204 27.636 154.276 27.660 ;
    END
  END w0_wd_in[158]
  PIN w0_wd_in[159]
    DIRECTION INPUT ;
    USE SIGNAL ;
    SHAPE ABUTMENT ;
    PORT
      LAYER M4 ;
      RECT 154.204 28.548 154.276 28.572 ;
    END
  END w0_wd_in[159]
  PIN w0_wd_in[160]
    DIRECTION INPUT ;
    USE SIGNAL ;
    SHAPE ABUTMENT ;
    PORT
      LAYER M4 ;
      RECT 154.204 29.460 154.276 29.484 ;
    END
  END w0_wd_in[160]
  PIN w0_wd_in[161]
    DIRECTION INPUT ;
    USE SIGNAL ;
    SHAPE ABUTMENT ;
    PORT
      LAYER M4 ;
      RECT 154.204 30.372 154.276 30.396 ;
    END
  END w0_wd_in[161]
  PIN w0_wd_in[162]
    DIRECTION INPUT ;
    USE SIGNAL ;
    SHAPE ABUTMENT ;
    PORT
      LAYER M4 ;
      RECT 154.204 31.284 154.276 31.308 ;
    END
  END w0_wd_in[162]
  PIN w0_wd_in[163]
    DIRECTION INPUT ;
    USE SIGNAL ;
    SHAPE ABUTMENT ;
    PORT
      LAYER M4 ;
      RECT 154.204 32.196 154.276 32.220 ;
    END
  END w0_wd_in[163]
  PIN w0_wd_in[164]
    DIRECTION INPUT ;
    USE SIGNAL ;
    SHAPE ABUTMENT ;
    PORT
      LAYER M4 ;
      RECT 154.204 33.108 154.276 33.132 ;
    END
  END w0_wd_in[164]
  PIN w0_wd_in[165]
    DIRECTION INPUT ;
    USE SIGNAL ;
    SHAPE ABUTMENT ;
    PORT
      LAYER M4 ;
      RECT 154.204 34.020 154.276 34.044 ;
    END
  END w0_wd_in[165]
  PIN w0_wd_in[166]
    DIRECTION INPUT ;
    USE SIGNAL ;
    SHAPE ABUTMENT ;
    PORT
      LAYER M4 ;
      RECT 154.204 34.932 154.276 34.956 ;
    END
  END w0_wd_in[166]
  PIN w0_wd_in[167]
    DIRECTION INPUT ;
    USE SIGNAL ;
    SHAPE ABUTMENT ;
    PORT
      LAYER M4 ;
      RECT 154.204 35.844 154.276 35.868 ;
    END
  END w0_wd_in[167]
  PIN w0_wd_in[168]
    DIRECTION INPUT ;
    USE SIGNAL ;
    SHAPE ABUTMENT ;
    PORT
      LAYER M4 ;
      RECT 154.204 36.756 154.276 36.780 ;
    END
  END w0_wd_in[168]
  PIN w0_wd_in[169]
    DIRECTION INPUT ;
    USE SIGNAL ;
    SHAPE ABUTMENT ;
    PORT
      LAYER M4 ;
      RECT 154.204 37.668 154.276 37.692 ;
    END
  END w0_wd_in[169]
  PIN w0_wd_in[170]
    DIRECTION INPUT ;
    USE SIGNAL ;
    SHAPE ABUTMENT ;
    PORT
      LAYER M4 ;
      RECT 154.204 38.580 154.276 38.604 ;
    END
  END w0_wd_in[170]
  PIN w0_wd_in[171]
    DIRECTION INPUT ;
    USE SIGNAL ;
    SHAPE ABUTMENT ;
    PORT
      LAYER M4 ;
      RECT 154.204 39.492 154.276 39.516 ;
    END
  END w0_wd_in[171]
  PIN w0_wd_in[172]
    DIRECTION INPUT ;
    USE SIGNAL ;
    SHAPE ABUTMENT ;
    PORT
      LAYER M4 ;
      RECT 154.204 40.404 154.276 40.428 ;
    END
  END w0_wd_in[172]
  PIN w0_wd_in[173]
    DIRECTION INPUT ;
    USE SIGNAL ;
    SHAPE ABUTMENT ;
    PORT
      LAYER M4 ;
      RECT 154.204 41.316 154.276 41.340 ;
    END
  END w0_wd_in[173]
  PIN w0_wd_in[174]
    DIRECTION INPUT ;
    USE SIGNAL ;
    SHAPE ABUTMENT ;
    PORT
      LAYER M4 ;
      RECT 154.204 42.228 154.276 42.252 ;
    END
  END w0_wd_in[174]
  PIN w0_wd_in[175]
    DIRECTION INPUT ;
    USE SIGNAL ;
    SHAPE ABUTMENT ;
    PORT
      LAYER M4 ;
      RECT 154.204 43.140 154.276 43.164 ;
    END
  END w0_wd_in[175]
  PIN w0_wd_in[176]
    DIRECTION INPUT ;
    USE SIGNAL ;
    SHAPE ABUTMENT ;
    PORT
      LAYER M4 ;
      RECT 154.204 44.052 154.276 44.076 ;
    END
  END w0_wd_in[176]
  PIN w0_wd_in[177]
    DIRECTION INPUT ;
    USE SIGNAL ;
    SHAPE ABUTMENT ;
    PORT
      LAYER M4 ;
      RECT 154.204 44.964 154.276 44.988 ;
    END
  END w0_wd_in[177]
  PIN w0_wd_in[178]
    DIRECTION INPUT ;
    USE SIGNAL ;
    SHAPE ABUTMENT ;
    PORT
      LAYER M4 ;
      RECT 154.204 45.876 154.276 45.900 ;
    END
  END w0_wd_in[178]
  PIN w0_wd_in[179]
    DIRECTION INPUT ;
    USE SIGNAL ;
    SHAPE ABUTMENT ;
    PORT
      LAYER M4 ;
      RECT 154.204 46.788 154.276 46.812 ;
    END
  END w0_wd_in[179]
  PIN w0_wd_in[180]
    DIRECTION INPUT ;
    USE SIGNAL ;
    SHAPE ABUTMENT ;
    PORT
      LAYER M4 ;
      RECT 154.204 47.700 154.276 47.724 ;
    END
  END w0_wd_in[180]
  PIN w0_wd_in[181]
    DIRECTION INPUT ;
    USE SIGNAL ;
    SHAPE ABUTMENT ;
    PORT
      LAYER M4 ;
      RECT 154.204 48.612 154.276 48.636 ;
    END
  END w0_wd_in[181]
  PIN w0_wd_in[182]
    DIRECTION INPUT ;
    USE SIGNAL ;
    SHAPE ABUTMENT ;
    PORT
      LAYER M4 ;
      RECT 154.204 49.524 154.276 49.548 ;
    END
  END w0_wd_in[182]
  PIN w0_wd_in[183]
    DIRECTION INPUT ;
    USE SIGNAL ;
    SHAPE ABUTMENT ;
    PORT
      LAYER M4 ;
      RECT 154.204 50.436 154.276 50.460 ;
    END
  END w0_wd_in[183]
  PIN w0_wd_in[184]
    DIRECTION INPUT ;
    USE SIGNAL ;
    SHAPE ABUTMENT ;
    PORT
      LAYER M4 ;
      RECT 154.204 51.348 154.276 51.372 ;
    END
  END w0_wd_in[184]
  PIN w0_wd_in[185]
    DIRECTION INPUT ;
    USE SIGNAL ;
    SHAPE ABUTMENT ;
    PORT
      LAYER M4 ;
      RECT 154.204 52.260 154.276 52.284 ;
    END
  END w0_wd_in[185]
  PIN w0_wd_in[186]
    DIRECTION INPUT ;
    USE SIGNAL ;
    SHAPE ABUTMENT ;
    PORT
      LAYER M4 ;
      RECT 154.204 53.172 154.276 53.196 ;
    END
  END w0_wd_in[186]
  PIN w0_wd_in[187]
    DIRECTION INPUT ;
    USE SIGNAL ;
    SHAPE ABUTMENT ;
    PORT
      LAYER M4 ;
      RECT 154.204 54.084 154.276 54.108 ;
    END
  END w0_wd_in[187]
  PIN w0_wd_in[188]
    DIRECTION INPUT ;
    USE SIGNAL ;
    SHAPE ABUTMENT ;
    PORT
      LAYER M4 ;
      RECT 154.204 54.996 154.276 55.020 ;
    END
  END w0_wd_in[188]
  PIN w0_wd_in[189]
    DIRECTION INPUT ;
    USE SIGNAL ;
    SHAPE ABUTMENT ;
    PORT
      LAYER M4 ;
      RECT 154.204 55.908 154.276 55.932 ;
    END
  END w0_wd_in[189]
  PIN w0_wd_in[190]
    DIRECTION INPUT ;
    USE SIGNAL ;
    SHAPE ABUTMENT ;
    PORT
      LAYER M4 ;
      RECT 154.204 56.820 154.276 56.844 ;
    END
  END w0_wd_in[190]
  PIN w0_wd_in[191]
    DIRECTION INPUT ;
    USE SIGNAL ;
    SHAPE ABUTMENT ;
    PORT
      LAYER M4 ;
      RECT 154.204 57.732 154.276 57.756 ;
    END
  END w0_wd_in[191]
  PIN w0_wd_in[192]
    DIRECTION INPUT ;
    USE SIGNAL ;
    SHAPE ABUTMENT ;
    PORT
      LAYER M4 ;
      RECT 154.204 58.644 154.276 58.668 ;
    END
  END w0_wd_in[192]
  PIN w0_wd_in[193]
    DIRECTION INPUT ;
    USE SIGNAL ;
    SHAPE ABUTMENT ;
    PORT
      LAYER M4 ;
      RECT 154.204 59.556 154.276 59.580 ;
    END
  END w0_wd_in[193]
  PIN w0_wd_in[194]
    DIRECTION INPUT ;
    USE SIGNAL ;
    SHAPE ABUTMENT ;
    PORT
      LAYER M4 ;
      RECT 154.204 60.468 154.276 60.492 ;
    END
  END w0_wd_in[194]
  PIN w0_wd_in[195]
    DIRECTION INPUT ;
    USE SIGNAL ;
    SHAPE ABUTMENT ;
    PORT
      LAYER M4 ;
      RECT 154.204 61.380 154.276 61.404 ;
    END
  END w0_wd_in[195]
  PIN w0_wd_in[196]
    DIRECTION INPUT ;
    USE SIGNAL ;
    SHAPE ABUTMENT ;
    PORT
      LAYER M4 ;
      RECT 154.204 62.292 154.276 62.316 ;
    END
  END w0_wd_in[196]
  PIN w0_wd_in[197]
    DIRECTION INPUT ;
    USE SIGNAL ;
    SHAPE ABUTMENT ;
    PORT
      LAYER M4 ;
      RECT 154.204 63.204 154.276 63.228 ;
    END
  END w0_wd_in[197]
  PIN w0_wd_in[198]
    DIRECTION INPUT ;
    USE SIGNAL ;
    SHAPE ABUTMENT ;
    PORT
      LAYER M4 ;
      RECT 154.204 64.116 154.276 64.140 ;
    END
  END w0_wd_in[198]
  PIN w0_wd_in[199]
    DIRECTION INPUT ;
    USE SIGNAL ;
    SHAPE ABUTMENT ;
    PORT
      LAYER M4 ;
      RECT 154.204 65.028 154.276 65.052 ;
    END
  END w0_wd_in[199]
  PIN w0_wd_in[200]
    DIRECTION INPUT ;
    USE SIGNAL ;
    SHAPE ABUTMENT ;
    PORT
      LAYER M4 ;
      RECT 154.204 65.940 154.276 65.964 ;
    END
  END w0_wd_in[200]
  PIN w0_wd_in[201]
    DIRECTION INPUT ;
    USE SIGNAL ;
    SHAPE ABUTMENT ;
    PORT
      LAYER M4 ;
      RECT 154.204 66.852 154.276 66.876 ;
    END
  END w0_wd_in[201]
  PIN w0_wd_in[202]
    DIRECTION INPUT ;
    USE SIGNAL ;
    SHAPE ABUTMENT ;
    PORT
      LAYER M4 ;
      RECT 154.204 67.764 154.276 67.788 ;
    END
  END w0_wd_in[202]
  PIN w0_wd_in[203]
    DIRECTION INPUT ;
    USE SIGNAL ;
    SHAPE ABUTMENT ;
    PORT
      LAYER M4 ;
      RECT 154.204 68.676 154.276 68.700 ;
    END
  END w0_wd_in[203]
  PIN w0_wd_in[204]
    DIRECTION INPUT ;
    USE SIGNAL ;
    SHAPE ABUTMENT ;
    PORT
      LAYER M4 ;
      RECT 154.204 69.588 154.276 69.612 ;
    END
  END w0_wd_in[204]
  PIN w0_wd_in[205]
    DIRECTION INPUT ;
    USE SIGNAL ;
    SHAPE ABUTMENT ;
    PORT
      LAYER M4 ;
      RECT 154.204 70.500 154.276 70.524 ;
    END
  END w0_wd_in[205]
  PIN w0_wd_in[206]
    DIRECTION INPUT ;
    USE SIGNAL ;
    SHAPE ABUTMENT ;
    PORT
      LAYER M4 ;
      RECT 154.204 71.412 154.276 71.436 ;
    END
  END w0_wd_in[206]
  PIN w0_wd_in[207]
    DIRECTION INPUT ;
    USE SIGNAL ;
    SHAPE ABUTMENT ;
    PORT
      LAYER M4 ;
      RECT 154.204 72.324 154.276 72.348 ;
    END
  END w0_wd_in[207]
  PIN w0_wd_in[208]
    DIRECTION INPUT ;
    USE SIGNAL ;
    SHAPE ABUTMENT ;
    PORT
      LAYER M4 ;
      RECT 154.204 73.236 154.276 73.260 ;
    END
  END w0_wd_in[208]
  PIN w0_wd_in[209]
    DIRECTION INPUT ;
    USE SIGNAL ;
    SHAPE ABUTMENT ;
    PORT
      LAYER M4 ;
      RECT 154.204 74.148 154.276 74.172 ;
    END
  END w0_wd_in[209]
  PIN w0_wd_in[210]
    DIRECTION INPUT ;
    USE SIGNAL ;
    SHAPE ABUTMENT ;
    PORT
      LAYER M4 ;
      RECT 154.204 75.060 154.276 75.084 ;
    END
  END w0_wd_in[210]
  PIN w0_wd_in[211]
    DIRECTION INPUT ;
    USE SIGNAL ;
    SHAPE ABUTMENT ;
    PORT
      LAYER M4 ;
      RECT 154.204 75.972 154.276 75.996 ;
    END
  END w0_wd_in[211]
  PIN w0_wd_in[212]
    DIRECTION INPUT ;
    USE SIGNAL ;
    SHAPE ABUTMENT ;
    PORT
      LAYER M4 ;
      RECT 154.204 76.884 154.276 76.908 ;
    END
  END w0_wd_in[212]
  PIN w0_wd_in[213]
    DIRECTION INPUT ;
    USE SIGNAL ;
    SHAPE ABUTMENT ;
    PORT
      LAYER M4 ;
      RECT 154.204 77.796 154.276 77.820 ;
    END
  END w0_wd_in[213]
  PIN w0_wd_in[214]
    DIRECTION INPUT ;
    USE SIGNAL ;
    SHAPE ABUTMENT ;
    PORT
      LAYER M4 ;
      RECT 154.204 78.708 154.276 78.732 ;
    END
  END w0_wd_in[214]
  PIN w0_wd_in[215]
    DIRECTION INPUT ;
    USE SIGNAL ;
    SHAPE ABUTMENT ;
    PORT
      LAYER M4 ;
      RECT 154.204 79.620 154.276 79.644 ;
    END
  END w0_wd_in[215]
  PIN w0_wd_in[216]
    DIRECTION INPUT ;
    USE SIGNAL ;
    SHAPE ABUTMENT ;
    PORT
      LAYER M4 ;
      RECT 154.204 80.532 154.276 80.556 ;
    END
  END w0_wd_in[216]
  PIN w0_wd_in[217]
    DIRECTION INPUT ;
    USE SIGNAL ;
    SHAPE ABUTMENT ;
    PORT
      LAYER M4 ;
      RECT 154.204 81.444 154.276 81.468 ;
    END
  END w0_wd_in[217]
  PIN w0_wd_in[218]
    DIRECTION INPUT ;
    USE SIGNAL ;
    SHAPE ABUTMENT ;
    PORT
      LAYER M4 ;
      RECT 154.204 82.356 154.276 82.380 ;
    END
  END w0_wd_in[218]
  PIN w0_wd_in[219]
    DIRECTION INPUT ;
    USE SIGNAL ;
    SHAPE ABUTMENT ;
    PORT
      LAYER M4 ;
      RECT 154.204 83.268 154.276 83.292 ;
    END
  END w0_wd_in[219]
  PIN w0_wd_in[220]
    DIRECTION INPUT ;
    USE SIGNAL ;
    SHAPE ABUTMENT ;
    PORT
      LAYER M4 ;
      RECT 154.204 84.180 154.276 84.204 ;
    END
  END w0_wd_in[220]
  PIN w0_wd_in[221]
    DIRECTION INPUT ;
    USE SIGNAL ;
    SHAPE ABUTMENT ;
    PORT
      LAYER M4 ;
      RECT 154.204 85.092 154.276 85.116 ;
    END
  END w0_wd_in[221]
  PIN w0_wd_in[222]
    DIRECTION INPUT ;
    USE SIGNAL ;
    SHAPE ABUTMENT ;
    PORT
      LAYER M4 ;
      RECT 154.204 86.004 154.276 86.028 ;
    END
  END w0_wd_in[222]
  PIN w0_wd_in[223]
    DIRECTION INPUT ;
    USE SIGNAL ;
    SHAPE ABUTMENT ;
    PORT
      LAYER M4 ;
      RECT 154.204 86.916 154.276 86.940 ;
    END
  END w0_wd_in[223]
  PIN w0_wd_in[224]
    DIRECTION INPUT ;
    USE SIGNAL ;
    SHAPE ABUTMENT ;
    PORT
      LAYER M4 ;
      RECT 154.204 87.828 154.276 87.852 ;
    END
  END w0_wd_in[224]
  PIN w0_wd_in[225]
    DIRECTION INPUT ;
    USE SIGNAL ;
    SHAPE ABUTMENT ;
    PORT
      LAYER M4 ;
      RECT 154.204 88.740 154.276 88.764 ;
    END
  END w0_wd_in[225]
  PIN w0_wd_in[226]
    DIRECTION INPUT ;
    USE SIGNAL ;
    SHAPE ABUTMENT ;
    PORT
      LAYER M4 ;
      RECT 154.204 89.652 154.276 89.676 ;
    END
  END w0_wd_in[226]
  PIN w0_wd_in[227]
    DIRECTION INPUT ;
    USE SIGNAL ;
    SHAPE ABUTMENT ;
    PORT
      LAYER M4 ;
      RECT 154.204 90.564 154.276 90.588 ;
    END
  END w0_wd_in[227]
  PIN w0_wd_in[228]
    DIRECTION INPUT ;
    USE SIGNAL ;
    SHAPE ABUTMENT ;
    PORT
      LAYER M4 ;
      RECT 154.204 91.476 154.276 91.500 ;
    END
  END w0_wd_in[228]
  PIN w0_wd_in[229]
    DIRECTION INPUT ;
    USE SIGNAL ;
    SHAPE ABUTMENT ;
    PORT
      LAYER M4 ;
      RECT 154.204 92.388 154.276 92.412 ;
    END
  END w0_wd_in[229]
  PIN w0_wd_in[230]
    DIRECTION INPUT ;
    USE SIGNAL ;
    SHAPE ABUTMENT ;
    PORT
      LAYER M4 ;
      RECT 154.204 93.300 154.276 93.324 ;
    END
  END w0_wd_in[230]
  PIN w0_wd_in[231]
    DIRECTION INPUT ;
    USE SIGNAL ;
    SHAPE ABUTMENT ;
    PORT
      LAYER M4 ;
      RECT 154.204 94.212 154.276 94.236 ;
    END
  END w0_wd_in[231]
  PIN w0_wd_in[232]
    DIRECTION INPUT ;
    USE SIGNAL ;
    SHAPE ABUTMENT ;
    PORT
      LAYER M4 ;
      RECT 154.204 95.124 154.276 95.148 ;
    END
  END w0_wd_in[232]
  PIN w0_wd_in[233]
    DIRECTION INPUT ;
    USE SIGNAL ;
    SHAPE ABUTMENT ;
    PORT
      LAYER M4 ;
      RECT 154.204 96.036 154.276 96.060 ;
    END
  END w0_wd_in[233]
  PIN w0_wd_in[234]
    DIRECTION INPUT ;
    USE SIGNAL ;
    SHAPE ABUTMENT ;
    PORT
      LAYER M4 ;
      RECT 154.204 96.948 154.276 96.972 ;
    END
  END w0_wd_in[234]
  PIN w0_wd_in[235]
    DIRECTION INPUT ;
    USE SIGNAL ;
    SHAPE ABUTMENT ;
    PORT
      LAYER M4 ;
      RECT 154.204 97.860 154.276 97.884 ;
    END
  END w0_wd_in[235]
  PIN w0_wd_in[236]
    DIRECTION INPUT ;
    USE SIGNAL ;
    SHAPE ABUTMENT ;
    PORT
      LAYER M4 ;
      RECT 154.204 98.772 154.276 98.796 ;
    END
  END w0_wd_in[236]
  PIN w0_wd_in[237]
    DIRECTION INPUT ;
    USE SIGNAL ;
    SHAPE ABUTMENT ;
    PORT
      LAYER M4 ;
      RECT 154.204 99.684 154.276 99.708 ;
    END
  END w0_wd_in[237]
  PIN w0_wd_in[238]
    DIRECTION INPUT ;
    USE SIGNAL ;
    SHAPE ABUTMENT ;
    PORT
      LAYER M4 ;
      RECT 154.204 100.596 154.276 100.620 ;
    END
  END w0_wd_in[238]
  PIN w0_wd_in[239]
    DIRECTION INPUT ;
    USE SIGNAL ;
    SHAPE ABUTMENT ;
    PORT
      LAYER M4 ;
      RECT 154.204 101.508 154.276 101.532 ;
    END
  END w0_wd_in[239]
  PIN w0_wd_in[240]
    DIRECTION INPUT ;
    USE SIGNAL ;
    SHAPE ABUTMENT ;
    PORT
      LAYER M4 ;
      RECT 154.204 102.420 154.276 102.444 ;
    END
  END w0_wd_in[240]
  PIN w0_wd_in[241]
    DIRECTION INPUT ;
    USE SIGNAL ;
    SHAPE ABUTMENT ;
    PORT
      LAYER M4 ;
      RECT 154.204 103.332 154.276 103.356 ;
    END
  END w0_wd_in[241]
  PIN w0_wd_in[242]
    DIRECTION INPUT ;
    USE SIGNAL ;
    SHAPE ABUTMENT ;
    PORT
      LAYER M4 ;
      RECT 154.204 104.244 154.276 104.268 ;
    END
  END w0_wd_in[242]
  PIN w0_wd_in[243]
    DIRECTION INPUT ;
    USE SIGNAL ;
    SHAPE ABUTMENT ;
    PORT
      LAYER M4 ;
      RECT 154.204 105.156 154.276 105.180 ;
    END
  END w0_wd_in[243]
  PIN w0_wd_in[244]
    DIRECTION INPUT ;
    USE SIGNAL ;
    SHAPE ABUTMENT ;
    PORT
      LAYER M4 ;
      RECT 154.204 106.068 154.276 106.092 ;
    END
  END w0_wd_in[244]
  PIN w0_wd_in[245]
    DIRECTION INPUT ;
    USE SIGNAL ;
    SHAPE ABUTMENT ;
    PORT
      LAYER M4 ;
      RECT 154.204 106.980 154.276 107.004 ;
    END
  END w0_wd_in[245]
  PIN w0_wd_in[246]
    DIRECTION INPUT ;
    USE SIGNAL ;
    SHAPE ABUTMENT ;
    PORT
      LAYER M4 ;
      RECT 154.204 107.892 154.276 107.916 ;
    END
  END w0_wd_in[246]
  PIN w0_wd_in[247]
    DIRECTION INPUT ;
    USE SIGNAL ;
    SHAPE ABUTMENT ;
    PORT
      LAYER M4 ;
      RECT 154.204 108.804 154.276 108.828 ;
    END
  END w0_wd_in[247]
  PIN w0_wd_in[248]
    DIRECTION INPUT ;
    USE SIGNAL ;
    SHAPE ABUTMENT ;
    PORT
      LAYER M4 ;
      RECT 154.204 109.716 154.276 109.740 ;
    END
  END w0_wd_in[248]
  PIN w0_wd_in[249]
    DIRECTION INPUT ;
    USE SIGNAL ;
    SHAPE ABUTMENT ;
    PORT
      LAYER M4 ;
      RECT 154.204 110.628 154.276 110.652 ;
    END
  END w0_wd_in[249]
  PIN w0_wd_in[250]
    DIRECTION INPUT ;
    USE SIGNAL ;
    SHAPE ABUTMENT ;
    PORT
      LAYER M4 ;
      RECT 154.204 111.540 154.276 111.564 ;
    END
  END w0_wd_in[250]
  PIN w0_wd_in[251]
    DIRECTION INPUT ;
    USE SIGNAL ;
    SHAPE ABUTMENT ;
    PORT
      LAYER M4 ;
      RECT 154.204 112.452 154.276 112.476 ;
    END
  END w0_wd_in[251]
  PIN w0_wd_in[252]
    DIRECTION INPUT ;
    USE SIGNAL ;
    SHAPE ABUTMENT ;
    PORT
      LAYER M4 ;
      RECT 154.204 113.364 154.276 113.388 ;
    END
  END w0_wd_in[252]
  PIN w0_wd_in[253]
    DIRECTION INPUT ;
    USE SIGNAL ;
    SHAPE ABUTMENT ;
    PORT
      LAYER M4 ;
      RECT 154.204 114.276 154.276 114.300 ;
    END
  END w0_wd_in[253]
  PIN w0_wd_in[254]
    DIRECTION INPUT ;
    USE SIGNAL ;
    SHAPE ABUTMENT ;
    PORT
      LAYER M4 ;
      RECT 154.204 115.188 154.276 115.212 ;
    END
  END w0_wd_in[254]
  PIN w0_wd_in[255]
    DIRECTION INPUT ;
    USE SIGNAL ;
    SHAPE ABUTMENT ;
    PORT
      LAYER M4 ;
      RECT 154.204 116.100 154.276 116.124 ;
    END
  END w0_wd_in[255]
  PIN w0_wd_in[256]
    DIRECTION OUTPUT ;
    USE SIGNAL ;
    SHAPE ABUTMENT ;
    PORT
      LAYER M3 ;
      RECT 0.207 0.000 0.225 0.054 ;
    END
  END w0_wd_in[256]
  PIN w0_wd_in[257]
    DIRECTION OUTPUT ;
    USE SIGNAL ;
    SHAPE ABUTMENT ;
    PORT
      LAYER M3 ;
      RECT 0.495 0.000 0.513 0.054 ;
    END
  END w0_wd_in[257]
  PIN w0_wd_in[258]
    DIRECTION OUTPUT ;
    USE SIGNAL ;
    SHAPE ABUTMENT ;
    PORT
      LAYER M3 ;
      RECT 0.783 0.000 0.801 0.054 ;
    END
  END w0_wd_in[258]
  PIN w0_wd_in[259]
    DIRECTION OUTPUT ;
    USE SIGNAL ;
    SHAPE ABUTMENT ;
    PORT
      LAYER M3 ;
      RECT 1.071 0.000 1.089 0.054 ;
    END
  END w0_wd_in[259]
  PIN w0_wd_in[260]
    DIRECTION OUTPUT ;
    USE SIGNAL ;
    SHAPE ABUTMENT ;
    PORT
      LAYER M3 ;
      RECT 1.359 0.000 1.377 0.054 ;
    END
  END w0_wd_in[260]
  PIN w0_wd_in[261]
    DIRECTION OUTPUT ;
    USE SIGNAL ;
    SHAPE ABUTMENT ;
    PORT
      LAYER M3 ;
      RECT 1.647 0.000 1.665 0.054 ;
    END
  END w0_wd_in[261]
  PIN w0_wd_in[262]
    DIRECTION OUTPUT ;
    USE SIGNAL ;
    SHAPE ABUTMENT ;
    PORT
      LAYER M3 ;
      RECT 1.935 0.000 1.953 0.054 ;
    END
  END w0_wd_in[262]
  PIN w0_wd_in[263]
    DIRECTION OUTPUT ;
    USE SIGNAL ;
    SHAPE ABUTMENT ;
    PORT
      LAYER M3 ;
      RECT 2.223 0.000 2.241 0.054 ;
    END
  END w0_wd_in[263]
  PIN w0_wd_in[264]
    DIRECTION OUTPUT ;
    USE SIGNAL ;
    SHAPE ABUTMENT ;
    PORT
      LAYER M3 ;
      RECT 2.511 0.000 2.529 0.054 ;
    END
  END w0_wd_in[264]
  PIN w0_wd_in[265]
    DIRECTION OUTPUT ;
    USE SIGNAL ;
    SHAPE ABUTMENT ;
    PORT
      LAYER M3 ;
      RECT 2.799 0.000 2.817 0.054 ;
    END
  END w0_wd_in[265]
  PIN w0_wd_in[266]
    DIRECTION OUTPUT ;
    USE SIGNAL ;
    SHAPE ABUTMENT ;
    PORT
      LAYER M3 ;
      RECT 3.087 0.000 3.105 0.054 ;
    END
  END w0_wd_in[266]
  PIN w0_wd_in[267]
    DIRECTION OUTPUT ;
    USE SIGNAL ;
    SHAPE ABUTMENT ;
    PORT
      LAYER M3 ;
      RECT 3.375 0.000 3.393 0.054 ;
    END
  END w0_wd_in[267]
  PIN w0_wd_in[268]
    DIRECTION OUTPUT ;
    USE SIGNAL ;
    SHAPE ABUTMENT ;
    PORT
      LAYER M3 ;
      RECT 3.663 0.000 3.681 0.054 ;
    END
  END w0_wd_in[268]
  PIN w0_wd_in[269]
    DIRECTION OUTPUT ;
    USE SIGNAL ;
    SHAPE ABUTMENT ;
    PORT
      LAYER M3 ;
      RECT 3.951 0.000 3.969 0.054 ;
    END
  END w0_wd_in[269]
  PIN w0_wd_in[270]
    DIRECTION OUTPUT ;
    USE SIGNAL ;
    SHAPE ABUTMENT ;
    PORT
      LAYER M3 ;
      RECT 4.239 0.000 4.257 0.054 ;
    END
  END w0_wd_in[270]
  PIN w0_wd_in[271]
    DIRECTION OUTPUT ;
    USE SIGNAL ;
    SHAPE ABUTMENT ;
    PORT
      LAYER M3 ;
      RECT 4.527 0.000 4.545 0.054 ;
    END
  END w0_wd_in[271]
  PIN w0_wd_in[272]
    DIRECTION OUTPUT ;
    USE SIGNAL ;
    SHAPE ABUTMENT ;
    PORT
      LAYER M3 ;
      RECT 4.815 0.000 4.833 0.054 ;
    END
  END w0_wd_in[272]
  PIN w0_wd_in[273]
    DIRECTION OUTPUT ;
    USE SIGNAL ;
    SHAPE ABUTMENT ;
    PORT
      LAYER M3 ;
      RECT 5.103 0.000 5.121 0.054 ;
    END
  END w0_wd_in[273]
  PIN w0_wd_in[274]
    DIRECTION OUTPUT ;
    USE SIGNAL ;
    SHAPE ABUTMENT ;
    PORT
      LAYER M3 ;
      RECT 5.391 0.000 5.409 0.054 ;
    END
  END w0_wd_in[274]
  PIN w0_wd_in[275]
    DIRECTION OUTPUT ;
    USE SIGNAL ;
    SHAPE ABUTMENT ;
    PORT
      LAYER M3 ;
      RECT 5.679 0.000 5.697 0.054 ;
    END
  END w0_wd_in[275]
  PIN w0_wd_in[276]
    DIRECTION OUTPUT ;
    USE SIGNAL ;
    SHAPE ABUTMENT ;
    PORT
      LAYER M3 ;
      RECT 5.967 0.000 5.985 0.054 ;
    END
  END w0_wd_in[276]
  PIN w0_wd_in[277]
    DIRECTION OUTPUT ;
    USE SIGNAL ;
    SHAPE ABUTMENT ;
    PORT
      LAYER M3 ;
      RECT 6.255 0.000 6.273 0.054 ;
    END
  END w0_wd_in[277]
  PIN w0_wd_in[278]
    DIRECTION OUTPUT ;
    USE SIGNAL ;
    SHAPE ABUTMENT ;
    PORT
      LAYER M3 ;
      RECT 6.543 0.000 6.561 0.054 ;
    END
  END w0_wd_in[278]
  PIN w0_wd_in[279]
    DIRECTION OUTPUT ;
    USE SIGNAL ;
    SHAPE ABUTMENT ;
    PORT
      LAYER M3 ;
      RECT 6.831 0.000 6.849 0.054 ;
    END
  END w0_wd_in[279]
  PIN w0_wd_in[280]
    DIRECTION OUTPUT ;
    USE SIGNAL ;
    SHAPE ABUTMENT ;
    PORT
      LAYER M3 ;
      RECT 7.119 0.000 7.137 0.054 ;
    END
  END w0_wd_in[280]
  PIN w0_wd_in[281]
    DIRECTION OUTPUT ;
    USE SIGNAL ;
    SHAPE ABUTMENT ;
    PORT
      LAYER M3 ;
      RECT 7.407 0.000 7.425 0.054 ;
    END
  END w0_wd_in[281]
  PIN w0_wd_in[282]
    DIRECTION OUTPUT ;
    USE SIGNAL ;
    SHAPE ABUTMENT ;
    PORT
      LAYER M3 ;
      RECT 7.695 0.000 7.713 0.054 ;
    END
  END w0_wd_in[282]
  PIN w0_wd_in[283]
    DIRECTION OUTPUT ;
    USE SIGNAL ;
    SHAPE ABUTMENT ;
    PORT
      LAYER M3 ;
      RECT 7.983 0.000 8.001 0.054 ;
    END
  END w0_wd_in[283]
  PIN w0_wd_in[284]
    DIRECTION OUTPUT ;
    USE SIGNAL ;
    SHAPE ABUTMENT ;
    PORT
      LAYER M3 ;
      RECT 8.271 0.000 8.289 0.054 ;
    END
  END w0_wd_in[284]
  PIN w0_wd_in[285]
    DIRECTION OUTPUT ;
    USE SIGNAL ;
    SHAPE ABUTMENT ;
    PORT
      LAYER M3 ;
      RECT 8.559 0.000 8.577 0.054 ;
    END
  END w0_wd_in[285]
  PIN w0_wd_in[286]
    DIRECTION OUTPUT ;
    USE SIGNAL ;
    SHAPE ABUTMENT ;
    PORT
      LAYER M3 ;
      RECT 8.847 0.000 8.865 0.054 ;
    END
  END w0_wd_in[286]
  PIN w0_wd_in[287]
    DIRECTION OUTPUT ;
    USE SIGNAL ;
    SHAPE ABUTMENT ;
    PORT
      LAYER M3 ;
      RECT 9.135 0.000 9.153 0.054 ;
    END
  END w0_wd_in[287]
  PIN w0_wd_in[288]
    DIRECTION OUTPUT ;
    USE SIGNAL ;
    SHAPE ABUTMENT ;
    PORT
      LAYER M3 ;
      RECT 9.423 0.000 9.441 0.054 ;
    END
  END w0_wd_in[288]
  PIN w0_wd_in[289]
    DIRECTION OUTPUT ;
    USE SIGNAL ;
    SHAPE ABUTMENT ;
    PORT
      LAYER M3 ;
      RECT 9.711 0.000 9.729 0.054 ;
    END
  END w0_wd_in[289]
  PIN w0_wd_in[290]
    DIRECTION OUTPUT ;
    USE SIGNAL ;
    SHAPE ABUTMENT ;
    PORT
      LAYER M3 ;
      RECT 9.999 0.000 10.017 0.054 ;
    END
  END w0_wd_in[290]
  PIN w0_wd_in[291]
    DIRECTION OUTPUT ;
    USE SIGNAL ;
    SHAPE ABUTMENT ;
    PORT
      LAYER M3 ;
      RECT 10.287 0.000 10.305 0.054 ;
    END
  END w0_wd_in[291]
  PIN w0_wd_in[292]
    DIRECTION OUTPUT ;
    USE SIGNAL ;
    SHAPE ABUTMENT ;
    PORT
      LAYER M3 ;
      RECT 10.575 0.000 10.593 0.054 ;
    END
  END w0_wd_in[292]
  PIN w0_wd_in[293]
    DIRECTION OUTPUT ;
    USE SIGNAL ;
    SHAPE ABUTMENT ;
    PORT
      LAYER M3 ;
      RECT 10.863 0.000 10.881 0.054 ;
    END
  END w0_wd_in[293]
  PIN w0_wd_in[294]
    DIRECTION OUTPUT ;
    USE SIGNAL ;
    SHAPE ABUTMENT ;
    PORT
      LAYER M3 ;
      RECT 11.151 0.000 11.169 0.054 ;
    END
  END w0_wd_in[294]
  PIN w0_wd_in[295]
    DIRECTION OUTPUT ;
    USE SIGNAL ;
    SHAPE ABUTMENT ;
    PORT
      LAYER M3 ;
      RECT 11.439 0.000 11.457 0.054 ;
    END
  END w0_wd_in[295]
  PIN w0_wd_in[296]
    DIRECTION OUTPUT ;
    USE SIGNAL ;
    SHAPE ABUTMENT ;
    PORT
      LAYER M3 ;
      RECT 11.727 0.000 11.745 0.054 ;
    END
  END w0_wd_in[296]
  PIN w0_wd_in[297]
    DIRECTION OUTPUT ;
    USE SIGNAL ;
    SHAPE ABUTMENT ;
    PORT
      LAYER M3 ;
      RECT 12.015 0.000 12.033 0.054 ;
    END
  END w0_wd_in[297]
  PIN w0_wd_in[298]
    DIRECTION OUTPUT ;
    USE SIGNAL ;
    SHAPE ABUTMENT ;
    PORT
      LAYER M3 ;
      RECT 12.303 0.000 12.321 0.054 ;
    END
  END w0_wd_in[298]
  PIN w0_wd_in[299]
    DIRECTION OUTPUT ;
    USE SIGNAL ;
    SHAPE ABUTMENT ;
    PORT
      LAYER M3 ;
      RECT 12.591 0.000 12.609 0.054 ;
    END
  END w0_wd_in[299]
  PIN w0_wd_in[300]
    DIRECTION OUTPUT ;
    USE SIGNAL ;
    SHAPE ABUTMENT ;
    PORT
      LAYER M3 ;
      RECT 12.879 0.000 12.897 0.054 ;
    END
  END w0_wd_in[300]
  PIN w0_wd_in[301]
    DIRECTION OUTPUT ;
    USE SIGNAL ;
    SHAPE ABUTMENT ;
    PORT
      LAYER M3 ;
      RECT 13.167 0.000 13.185 0.054 ;
    END
  END w0_wd_in[301]
  PIN w0_wd_in[302]
    DIRECTION OUTPUT ;
    USE SIGNAL ;
    SHAPE ABUTMENT ;
    PORT
      LAYER M3 ;
      RECT 13.455 0.000 13.473 0.054 ;
    END
  END w0_wd_in[302]
  PIN w0_wd_in[303]
    DIRECTION OUTPUT ;
    USE SIGNAL ;
    SHAPE ABUTMENT ;
    PORT
      LAYER M3 ;
      RECT 13.743 0.000 13.761 0.054 ;
    END
  END w0_wd_in[303]
  PIN w0_wd_in[304]
    DIRECTION OUTPUT ;
    USE SIGNAL ;
    SHAPE ABUTMENT ;
    PORT
      LAYER M3 ;
      RECT 14.031 0.000 14.049 0.054 ;
    END
  END w0_wd_in[304]
  PIN w0_wd_in[305]
    DIRECTION OUTPUT ;
    USE SIGNAL ;
    SHAPE ABUTMENT ;
    PORT
      LAYER M3 ;
      RECT 14.319 0.000 14.337 0.054 ;
    END
  END w0_wd_in[305]
  PIN w0_wd_in[306]
    DIRECTION OUTPUT ;
    USE SIGNAL ;
    SHAPE ABUTMENT ;
    PORT
      LAYER M3 ;
      RECT 14.607 0.000 14.625 0.054 ;
    END
  END w0_wd_in[306]
  PIN w0_wd_in[307]
    DIRECTION OUTPUT ;
    USE SIGNAL ;
    SHAPE ABUTMENT ;
    PORT
      LAYER M3 ;
      RECT 14.895 0.000 14.913 0.054 ;
    END
  END w0_wd_in[307]
  PIN w0_wd_in[308]
    DIRECTION OUTPUT ;
    USE SIGNAL ;
    SHAPE ABUTMENT ;
    PORT
      LAYER M3 ;
      RECT 15.183 0.000 15.201 0.054 ;
    END
  END w0_wd_in[308]
  PIN w0_wd_in[309]
    DIRECTION OUTPUT ;
    USE SIGNAL ;
    SHAPE ABUTMENT ;
    PORT
      LAYER M3 ;
      RECT 15.471 0.000 15.489 0.054 ;
    END
  END w0_wd_in[309]
  PIN w0_wd_in[310]
    DIRECTION OUTPUT ;
    USE SIGNAL ;
    SHAPE ABUTMENT ;
    PORT
      LAYER M3 ;
      RECT 15.759 0.000 15.777 0.054 ;
    END
  END w0_wd_in[310]
  PIN w0_wd_in[311]
    DIRECTION OUTPUT ;
    USE SIGNAL ;
    SHAPE ABUTMENT ;
    PORT
      LAYER M3 ;
      RECT 16.047 0.000 16.065 0.054 ;
    END
  END w0_wd_in[311]
  PIN w0_wd_in[312]
    DIRECTION OUTPUT ;
    USE SIGNAL ;
    SHAPE ABUTMENT ;
    PORT
      LAYER M3 ;
      RECT 16.335 0.000 16.353 0.054 ;
    END
  END w0_wd_in[312]
  PIN w0_wd_in[313]
    DIRECTION OUTPUT ;
    USE SIGNAL ;
    SHAPE ABUTMENT ;
    PORT
      LAYER M3 ;
      RECT 16.623 0.000 16.641 0.054 ;
    END
  END w0_wd_in[313]
  PIN w0_wd_in[314]
    DIRECTION OUTPUT ;
    USE SIGNAL ;
    SHAPE ABUTMENT ;
    PORT
      LAYER M3 ;
      RECT 16.911 0.000 16.929 0.054 ;
    END
  END w0_wd_in[314]
  PIN w0_wd_in[315]
    DIRECTION OUTPUT ;
    USE SIGNAL ;
    SHAPE ABUTMENT ;
    PORT
      LAYER M3 ;
      RECT 17.199 0.000 17.217 0.054 ;
    END
  END w0_wd_in[315]
  PIN w0_wd_in[316]
    DIRECTION OUTPUT ;
    USE SIGNAL ;
    SHAPE ABUTMENT ;
    PORT
      LAYER M3 ;
      RECT 17.487 0.000 17.505 0.054 ;
    END
  END w0_wd_in[316]
  PIN w0_wd_in[317]
    DIRECTION OUTPUT ;
    USE SIGNAL ;
    SHAPE ABUTMENT ;
    PORT
      LAYER M3 ;
      RECT 17.775 0.000 17.793 0.054 ;
    END
  END w0_wd_in[317]
  PIN w0_wd_in[318]
    DIRECTION OUTPUT ;
    USE SIGNAL ;
    SHAPE ABUTMENT ;
    PORT
      LAYER M3 ;
      RECT 18.063 0.000 18.081 0.054 ;
    END
  END w0_wd_in[318]
  PIN w0_wd_in[319]
    DIRECTION OUTPUT ;
    USE SIGNAL ;
    SHAPE ABUTMENT ;
    PORT
      LAYER M3 ;
      RECT 18.351 0.000 18.369 0.054 ;
    END
  END w0_wd_in[319]
  PIN w0_wd_in[320]
    DIRECTION OUTPUT ;
    USE SIGNAL ;
    SHAPE ABUTMENT ;
    PORT
      LAYER M3 ;
      RECT 18.639 0.000 18.657 0.054 ;
    END
  END w0_wd_in[320]
  PIN w0_wd_in[321]
    DIRECTION OUTPUT ;
    USE SIGNAL ;
    SHAPE ABUTMENT ;
    PORT
      LAYER M3 ;
      RECT 18.927 0.000 18.945 0.054 ;
    END
  END w0_wd_in[321]
  PIN w0_wd_in[322]
    DIRECTION OUTPUT ;
    USE SIGNAL ;
    SHAPE ABUTMENT ;
    PORT
      LAYER M3 ;
      RECT 19.215 0.000 19.233 0.054 ;
    END
  END w0_wd_in[322]
  PIN w0_wd_in[323]
    DIRECTION OUTPUT ;
    USE SIGNAL ;
    SHAPE ABUTMENT ;
    PORT
      LAYER M3 ;
      RECT 19.503 0.000 19.521 0.054 ;
    END
  END w0_wd_in[323]
  PIN w0_wd_in[324]
    DIRECTION OUTPUT ;
    USE SIGNAL ;
    SHAPE ABUTMENT ;
    PORT
      LAYER M3 ;
      RECT 19.791 0.000 19.809 0.054 ;
    END
  END w0_wd_in[324]
  PIN w0_wd_in[325]
    DIRECTION OUTPUT ;
    USE SIGNAL ;
    SHAPE ABUTMENT ;
    PORT
      LAYER M3 ;
      RECT 20.079 0.000 20.097 0.054 ;
    END
  END w0_wd_in[325]
  PIN w0_wd_in[326]
    DIRECTION OUTPUT ;
    USE SIGNAL ;
    SHAPE ABUTMENT ;
    PORT
      LAYER M3 ;
      RECT 20.367 0.000 20.385 0.054 ;
    END
  END w0_wd_in[326]
  PIN w0_wd_in[327]
    DIRECTION OUTPUT ;
    USE SIGNAL ;
    SHAPE ABUTMENT ;
    PORT
      LAYER M3 ;
      RECT 20.655 0.000 20.673 0.054 ;
    END
  END w0_wd_in[327]
  PIN w0_wd_in[328]
    DIRECTION OUTPUT ;
    USE SIGNAL ;
    SHAPE ABUTMENT ;
    PORT
      LAYER M3 ;
      RECT 20.943 0.000 20.961 0.054 ;
    END
  END w0_wd_in[328]
  PIN w0_wd_in[329]
    DIRECTION OUTPUT ;
    USE SIGNAL ;
    SHAPE ABUTMENT ;
    PORT
      LAYER M3 ;
      RECT 21.231 0.000 21.249 0.054 ;
    END
  END w0_wd_in[329]
  PIN w0_wd_in[330]
    DIRECTION OUTPUT ;
    USE SIGNAL ;
    SHAPE ABUTMENT ;
    PORT
      LAYER M3 ;
      RECT 21.519 0.000 21.537 0.054 ;
    END
  END w0_wd_in[330]
  PIN w0_wd_in[331]
    DIRECTION OUTPUT ;
    USE SIGNAL ;
    SHAPE ABUTMENT ;
    PORT
      LAYER M3 ;
      RECT 21.807 0.000 21.825 0.054 ;
    END
  END w0_wd_in[331]
  PIN w0_wd_in[332]
    DIRECTION OUTPUT ;
    USE SIGNAL ;
    SHAPE ABUTMENT ;
    PORT
      LAYER M3 ;
      RECT 22.095 0.000 22.113 0.054 ;
    END
  END w0_wd_in[332]
  PIN w0_wd_in[333]
    DIRECTION OUTPUT ;
    USE SIGNAL ;
    SHAPE ABUTMENT ;
    PORT
      LAYER M3 ;
      RECT 22.383 0.000 22.401 0.054 ;
    END
  END w0_wd_in[333]
  PIN w0_wd_in[334]
    DIRECTION OUTPUT ;
    USE SIGNAL ;
    SHAPE ABUTMENT ;
    PORT
      LAYER M3 ;
      RECT 22.671 0.000 22.689 0.054 ;
    END
  END w0_wd_in[334]
  PIN w0_wd_in[335]
    DIRECTION OUTPUT ;
    USE SIGNAL ;
    SHAPE ABUTMENT ;
    PORT
      LAYER M3 ;
      RECT 22.959 0.000 22.977 0.054 ;
    END
  END w0_wd_in[335]
  PIN w0_wd_in[336]
    DIRECTION OUTPUT ;
    USE SIGNAL ;
    SHAPE ABUTMENT ;
    PORT
      LAYER M3 ;
      RECT 23.247 0.000 23.265 0.054 ;
    END
  END w0_wd_in[336]
  PIN w0_wd_in[337]
    DIRECTION OUTPUT ;
    USE SIGNAL ;
    SHAPE ABUTMENT ;
    PORT
      LAYER M3 ;
      RECT 23.535 0.000 23.553 0.054 ;
    END
  END w0_wd_in[337]
  PIN w0_wd_in[338]
    DIRECTION OUTPUT ;
    USE SIGNAL ;
    SHAPE ABUTMENT ;
    PORT
      LAYER M3 ;
      RECT 23.823 0.000 23.841 0.054 ;
    END
  END w0_wd_in[338]
  PIN w0_wd_in[339]
    DIRECTION OUTPUT ;
    USE SIGNAL ;
    SHAPE ABUTMENT ;
    PORT
      LAYER M3 ;
      RECT 24.111 0.000 24.129 0.054 ;
    END
  END w0_wd_in[339]
  PIN w0_wd_in[340]
    DIRECTION OUTPUT ;
    USE SIGNAL ;
    SHAPE ABUTMENT ;
    PORT
      LAYER M3 ;
      RECT 24.399 0.000 24.417 0.054 ;
    END
  END w0_wd_in[340]
  PIN w0_wd_in[341]
    DIRECTION OUTPUT ;
    USE SIGNAL ;
    SHAPE ABUTMENT ;
    PORT
      LAYER M3 ;
      RECT 24.687 0.000 24.705 0.054 ;
    END
  END w0_wd_in[341]
  PIN w0_wd_in[342]
    DIRECTION OUTPUT ;
    USE SIGNAL ;
    SHAPE ABUTMENT ;
    PORT
      LAYER M3 ;
      RECT 24.975 0.000 24.993 0.054 ;
    END
  END w0_wd_in[342]
  PIN w0_wd_in[343]
    DIRECTION OUTPUT ;
    USE SIGNAL ;
    SHAPE ABUTMENT ;
    PORT
      LAYER M3 ;
      RECT 25.263 0.000 25.281 0.054 ;
    END
  END w0_wd_in[343]
  PIN w0_wd_in[344]
    DIRECTION OUTPUT ;
    USE SIGNAL ;
    SHAPE ABUTMENT ;
    PORT
      LAYER M3 ;
      RECT 25.551 0.000 25.569 0.054 ;
    END
  END w0_wd_in[344]
  PIN w0_wd_in[345]
    DIRECTION OUTPUT ;
    USE SIGNAL ;
    SHAPE ABUTMENT ;
    PORT
      LAYER M3 ;
      RECT 25.839 0.000 25.857 0.054 ;
    END
  END w0_wd_in[345]
  PIN w0_wd_in[346]
    DIRECTION OUTPUT ;
    USE SIGNAL ;
    SHAPE ABUTMENT ;
    PORT
      LAYER M3 ;
      RECT 26.127 0.000 26.145 0.054 ;
    END
  END w0_wd_in[346]
  PIN w0_wd_in[347]
    DIRECTION OUTPUT ;
    USE SIGNAL ;
    SHAPE ABUTMENT ;
    PORT
      LAYER M3 ;
      RECT 26.415 0.000 26.433 0.054 ;
    END
  END w0_wd_in[347]
  PIN w0_wd_in[348]
    DIRECTION OUTPUT ;
    USE SIGNAL ;
    SHAPE ABUTMENT ;
    PORT
      LAYER M3 ;
      RECT 26.703 0.000 26.721 0.054 ;
    END
  END w0_wd_in[348]
  PIN w0_wd_in[349]
    DIRECTION OUTPUT ;
    USE SIGNAL ;
    SHAPE ABUTMENT ;
    PORT
      LAYER M3 ;
      RECT 26.991 0.000 27.009 0.054 ;
    END
  END w0_wd_in[349]
  PIN w0_wd_in[350]
    DIRECTION OUTPUT ;
    USE SIGNAL ;
    SHAPE ABUTMENT ;
    PORT
      LAYER M3 ;
      RECT 27.279 0.000 27.297 0.054 ;
    END
  END w0_wd_in[350]
  PIN w0_wd_in[351]
    DIRECTION OUTPUT ;
    USE SIGNAL ;
    SHAPE ABUTMENT ;
    PORT
      LAYER M3 ;
      RECT 27.567 0.000 27.585 0.054 ;
    END
  END w0_wd_in[351]
  PIN w0_wd_in[352]
    DIRECTION OUTPUT ;
    USE SIGNAL ;
    SHAPE ABUTMENT ;
    PORT
      LAYER M3 ;
      RECT 27.855 0.000 27.873 0.054 ;
    END
  END w0_wd_in[352]
  PIN w0_wd_in[353]
    DIRECTION OUTPUT ;
    USE SIGNAL ;
    SHAPE ABUTMENT ;
    PORT
      LAYER M3 ;
      RECT 28.143 0.000 28.161 0.054 ;
    END
  END w0_wd_in[353]
  PIN w0_wd_in[354]
    DIRECTION OUTPUT ;
    USE SIGNAL ;
    SHAPE ABUTMENT ;
    PORT
      LAYER M3 ;
      RECT 28.431 0.000 28.449 0.054 ;
    END
  END w0_wd_in[354]
  PIN w0_wd_in[355]
    DIRECTION OUTPUT ;
    USE SIGNAL ;
    SHAPE ABUTMENT ;
    PORT
      LAYER M3 ;
      RECT 28.719 0.000 28.737 0.054 ;
    END
  END w0_wd_in[355]
  PIN w0_wd_in[356]
    DIRECTION OUTPUT ;
    USE SIGNAL ;
    SHAPE ABUTMENT ;
    PORT
      LAYER M3 ;
      RECT 29.007 0.000 29.025 0.054 ;
    END
  END w0_wd_in[356]
  PIN w0_wd_in[357]
    DIRECTION OUTPUT ;
    USE SIGNAL ;
    SHAPE ABUTMENT ;
    PORT
      LAYER M3 ;
      RECT 29.295 0.000 29.313 0.054 ;
    END
  END w0_wd_in[357]
  PIN w0_wd_in[358]
    DIRECTION OUTPUT ;
    USE SIGNAL ;
    SHAPE ABUTMENT ;
    PORT
      LAYER M3 ;
      RECT 29.583 0.000 29.601 0.054 ;
    END
  END w0_wd_in[358]
  PIN w0_wd_in[359]
    DIRECTION OUTPUT ;
    USE SIGNAL ;
    SHAPE ABUTMENT ;
    PORT
      LAYER M3 ;
      RECT 29.871 0.000 29.889 0.054 ;
    END
  END w0_wd_in[359]
  PIN w0_wd_in[360]
    DIRECTION OUTPUT ;
    USE SIGNAL ;
    SHAPE ABUTMENT ;
    PORT
      LAYER M3 ;
      RECT 30.159 0.000 30.177 0.054 ;
    END
  END w0_wd_in[360]
  PIN w0_wd_in[361]
    DIRECTION OUTPUT ;
    USE SIGNAL ;
    SHAPE ABUTMENT ;
    PORT
      LAYER M3 ;
      RECT 30.447 0.000 30.465 0.054 ;
    END
  END w0_wd_in[361]
  PIN w0_wd_in[362]
    DIRECTION OUTPUT ;
    USE SIGNAL ;
    SHAPE ABUTMENT ;
    PORT
      LAYER M3 ;
      RECT 30.735 0.000 30.753 0.054 ;
    END
  END w0_wd_in[362]
  PIN w0_wd_in[363]
    DIRECTION OUTPUT ;
    USE SIGNAL ;
    SHAPE ABUTMENT ;
    PORT
      LAYER M3 ;
      RECT 31.023 0.000 31.041 0.054 ;
    END
  END w0_wd_in[363]
  PIN w0_wd_in[364]
    DIRECTION OUTPUT ;
    USE SIGNAL ;
    SHAPE ABUTMENT ;
    PORT
      LAYER M3 ;
      RECT 31.311 0.000 31.329 0.054 ;
    END
  END w0_wd_in[364]
  PIN w0_wd_in[365]
    DIRECTION OUTPUT ;
    USE SIGNAL ;
    SHAPE ABUTMENT ;
    PORT
      LAYER M3 ;
      RECT 31.599 0.000 31.617 0.054 ;
    END
  END w0_wd_in[365]
  PIN w0_wd_in[366]
    DIRECTION OUTPUT ;
    USE SIGNAL ;
    SHAPE ABUTMENT ;
    PORT
      LAYER M3 ;
      RECT 31.887 0.000 31.905 0.054 ;
    END
  END w0_wd_in[366]
  PIN w0_wd_in[367]
    DIRECTION OUTPUT ;
    USE SIGNAL ;
    SHAPE ABUTMENT ;
    PORT
      LAYER M3 ;
      RECT 32.175 0.000 32.193 0.054 ;
    END
  END w0_wd_in[367]
  PIN w0_wd_in[368]
    DIRECTION OUTPUT ;
    USE SIGNAL ;
    SHAPE ABUTMENT ;
    PORT
      LAYER M3 ;
      RECT 32.463 0.000 32.481 0.054 ;
    END
  END w0_wd_in[368]
  PIN w0_wd_in[369]
    DIRECTION OUTPUT ;
    USE SIGNAL ;
    SHAPE ABUTMENT ;
    PORT
      LAYER M3 ;
      RECT 32.751 0.000 32.769 0.054 ;
    END
  END w0_wd_in[369]
  PIN w0_wd_in[370]
    DIRECTION OUTPUT ;
    USE SIGNAL ;
    SHAPE ABUTMENT ;
    PORT
      LAYER M3 ;
      RECT 33.039 0.000 33.057 0.054 ;
    END
  END w0_wd_in[370]
  PIN w0_wd_in[371]
    DIRECTION OUTPUT ;
    USE SIGNAL ;
    SHAPE ABUTMENT ;
    PORT
      LAYER M3 ;
      RECT 33.327 0.000 33.345 0.054 ;
    END
  END w0_wd_in[371]
  PIN w0_wd_in[372]
    DIRECTION OUTPUT ;
    USE SIGNAL ;
    SHAPE ABUTMENT ;
    PORT
      LAYER M3 ;
      RECT 33.615 0.000 33.633 0.054 ;
    END
  END w0_wd_in[372]
  PIN w0_wd_in[373]
    DIRECTION OUTPUT ;
    USE SIGNAL ;
    SHAPE ABUTMENT ;
    PORT
      LAYER M3 ;
      RECT 33.903 0.000 33.921 0.054 ;
    END
  END w0_wd_in[373]
  PIN w0_wd_in[374]
    DIRECTION OUTPUT ;
    USE SIGNAL ;
    SHAPE ABUTMENT ;
    PORT
      LAYER M3 ;
      RECT 34.191 0.000 34.209 0.054 ;
    END
  END w0_wd_in[374]
  PIN w0_wd_in[375]
    DIRECTION OUTPUT ;
    USE SIGNAL ;
    SHAPE ABUTMENT ;
    PORT
      LAYER M3 ;
      RECT 34.479 0.000 34.497 0.054 ;
    END
  END w0_wd_in[375]
  PIN w0_wd_in[376]
    DIRECTION OUTPUT ;
    USE SIGNAL ;
    SHAPE ABUTMENT ;
    PORT
      LAYER M3 ;
      RECT 34.767 0.000 34.785 0.054 ;
    END
  END w0_wd_in[376]
  PIN w0_wd_in[377]
    DIRECTION OUTPUT ;
    USE SIGNAL ;
    SHAPE ABUTMENT ;
    PORT
      LAYER M3 ;
      RECT 35.055 0.000 35.073 0.054 ;
    END
  END w0_wd_in[377]
  PIN w0_wd_in[378]
    DIRECTION OUTPUT ;
    USE SIGNAL ;
    SHAPE ABUTMENT ;
    PORT
      LAYER M3 ;
      RECT 35.343 0.000 35.361 0.054 ;
    END
  END w0_wd_in[378]
  PIN w0_wd_in[379]
    DIRECTION OUTPUT ;
    USE SIGNAL ;
    SHAPE ABUTMENT ;
    PORT
      LAYER M3 ;
      RECT 35.631 0.000 35.649 0.054 ;
    END
  END w0_wd_in[379]
  PIN w0_wd_in[380]
    DIRECTION OUTPUT ;
    USE SIGNAL ;
    SHAPE ABUTMENT ;
    PORT
      LAYER M3 ;
      RECT 35.919 0.000 35.937 0.054 ;
    END
  END w0_wd_in[380]
  PIN w0_wd_in[381]
    DIRECTION OUTPUT ;
    USE SIGNAL ;
    SHAPE ABUTMENT ;
    PORT
      LAYER M3 ;
      RECT 36.207 0.000 36.225 0.054 ;
    END
  END w0_wd_in[381]
  PIN w0_wd_in[382]
    DIRECTION OUTPUT ;
    USE SIGNAL ;
    SHAPE ABUTMENT ;
    PORT
      LAYER M3 ;
      RECT 36.495 0.000 36.513 0.054 ;
    END
  END w0_wd_in[382]
  PIN w0_wd_in[383]
    DIRECTION OUTPUT ;
    USE SIGNAL ;
    SHAPE ABUTMENT ;
    PORT
      LAYER M3 ;
      RECT 36.783 0.000 36.801 0.054 ;
    END
  END w0_wd_in[383]
  PIN w0_wd_in[384]
    DIRECTION OUTPUT ;
    USE SIGNAL ;
    SHAPE ABUTMENT ;
    PORT
      LAYER M3 ;
      RECT 37.071 0.000 37.089 0.054 ;
    END
  END w0_wd_in[384]
  PIN w0_wd_in[385]
    DIRECTION OUTPUT ;
    USE SIGNAL ;
    SHAPE ABUTMENT ;
    PORT
      LAYER M3 ;
      RECT 37.359 0.000 37.377 0.054 ;
    END
  END w0_wd_in[385]
  PIN w0_wd_in[386]
    DIRECTION OUTPUT ;
    USE SIGNAL ;
    SHAPE ABUTMENT ;
    PORT
      LAYER M3 ;
      RECT 37.647 0.000 37.665 0.054 ;
    END
  END w0_wd_in[386]
  PIN w0_wd_in[387]
    DIRECTION OUTPUT ;
    USE SIGNAL ;
    SHAPE ABUTMENT ;
    PORT
      LAYER M3 ;
      RECT 37.935 0.000 37.953 0.054 ;
    END
  END w0_wd_in[387]
  PIN w0_wd_in[388]
    DIRECTION OUTPUT ;
    USE SIGNAL ;
    SHAPE ABUTMENT ;
    PORT
      LAYER M3 ;
      RECT 38.223 0.000 38.241 0.054 ;
    END
  END w0_wd_in[388]
  PIN w0_wd_in[389]
    DIRECTION OUTPUT ;
    USE SIGNAL ;
    SHAPE ABUTMENT ;
    PORT
      LAYER M3 ;
      RECT 38.511 0.000 38.529 0.054 ;
    END
  END w0_wd_in[389]
  PIN w0_wd_in[390]
    DIRECTION OUTPUT ;
    USE SIGNAL ;
    SHAPE ABUTMENT ;
    PORT
      LAYER M3 ;
      RECT 38.799 0.000 38.817 0.054 ;
    END
  END w0_wd_in[390]
  PIN w0_wd_in[391]
    DIRECTION OUTPUT ;
    USE SIGNAL ;
    SHAPE ABUTMENT ;
    PORT
      LAYER M3 ;
      RECT 39.087 0.000 39.105 0.054 ;
    END
  END w0_wd_in[391]
  PIN w0_wd_in[392]
    DIRECTION OUTPUT ;
    USE SIGNAL ;
    SHAPE ABUTMENT ;
    PORT
      LAYER M3 ;
      RECT 39.375 0.000 39.393 0.054 ;
    END
  END w0_wd_in[392]
  PIN w0_wd_in[393]
    DIRECTION OUTPUT ;
    USE SIGNAL ;
    SHAPE ABUTMENT ;
    PORT
      LAYER M3 ;
      RECT 39.663 0.000 39.681 0.054 ;
    END
  END w0_wd_in[393]
  PIN w0_wd_in[394]
    DIRECTION OUTPUT ;
    USE SIGNAL ;
    SHAPE ABUTMENT ;
    PORT
      LAYER M3 ;
      RECT 39.951 0.000 39.969 0.054 ;
    END
  END w0_wd_in[394]
  PIN w0_wd_in[395]
    DIRECTION OUTPUT ;
    USE SIGNAL ;
    SHAPE ABUTMENT ;
    PORT
      LAYER M3 ;
      RECT 40.239 0.000 40.257 0.054 ;
    END
  END w0_wd_in[395]
  PIN w0_wd_in[396]
    DIRECTION OUTPUT ;
    USE SIGNAL ;
    SHAPE ABUTMENT ;
    PORT
      LAYER M3 ;
      RECT 40.527 0.000 40.545 0.054 ;
    END
  END w0_wd_in[396]
  PIN w0_wd_in[397]
    DIRECTION OUTPUT ;
    USE SIGNAL ;
    SHAPE ABUTMENT ;
    PORT
      LAYER M3 ;
      RECT 40.815 0.000 40.833 0.054 ;
    END
  END w0_wd_in[397]
  PIN w0_wd_in[398]
    DIRECTION OUTPUT ;
    USE SIGNAL ;
    SHAPE ABUTMENT ;
    PORT
      LAYER M3 ;
      RECT 41.103 0.000 41.121 0.054 ;
    END
  END w0_wd_in[398]
  PIN w0_wd_in[399]
    DIRECTION OUTPUT ;
    USE SIGNAL ;
    SHAPE ABUTMENT ;
    PORT
      LAYER M3 ;
      RECT 41.391 0.000 41.409 0.054 ;
    END
  END w0_wd_in[399]
  PIN w0_wd_in[400]
    DIRECTION OUTPUT ;
    USE SIGNAL ;
    SHAPE ABUTMENT ;
    PORT
      LAYER M3 ;
      RECT 41.679 0.000 41.697 0.054 ;
    END
  END w0_wd_in[400]
  PIN w0_wd_in[401]
    DIRECTION OUTPUT ;
    USE SIGNAL ;
    SHAPE ABUTMENT ;
    PORT
      LAYER M3 ;
      RECT 41.967 0.000 41.985 0.054 ;
    END
  END w0_wd_in[401]
  PIN w0_wd_in[402]
    DIRECTION OUTPUT ;
    USE SIGNAL ;
    SHAPE ABUTMENT ;
    PORT
      LAYER M3 ;
      RECT 42.255 0.000 42.273 0.054 ;
    END
  END w0_wd_in[402]
  PIN w0_wd_in[403]
    DIRECTION OUTPUT ;
    USE SIGNAL ;
    SHAPE ABUTMENT ;
    PORT
      LAYER M3 ;
      RECT 42.543 0.000 42.561 0.054 ;
    END
  END w0_wd_in[403]
  PIN w0_wd_in[404]
    DIRECTION OUTPUT ;
    USE SIGNAL ;
    SHAPE ABUTMENT ;
    PORT
      LAYER M3 ;
      RECT 42.831 0.000 42.849 0.054 ;
    END
  END w0_wd_in[404]
  PIN w0_wd_in[405]
    DIRECTION OUTPUT ;
    USE SIGNAL ;
    SHAPE ABUTMENT ;
    PORT
      LAYER M3 ;
      RECT 43.119 0.000 43.137 0.054 ;
    END
  END w0_wd_in[405]
  PIN w0_wd_in[406]
    DIRECTION OUTPUT ;
    USE SIGNAL ;
    SHAPE ABUTMENT ;
    PORT
      LAYER M3 ;
      RECT 43.407 0.000 43.425 0.054 ;
    END
  END w0_wd_in[406]
  PIN w0_wd_in[407]
    DIRECTION OUTPUT ;
    USE SIGNAL ;
    SHAPE ABUTMENT ;
    PORT
      LAYER M3 ;
      RECT 43.695 0.000 43.713 0.054 ;
    END
  END w0_wd_in[407]
  PIN w0_wd_in[408]
    DIRECTION OUTPUT ;
    USE SIGNAL ;
    SHAPE ABUTMENT ;
    PORT
      LAYER M3 ;
      RECT 43.983 0.000 44.001 0.054 ;
    END
  END w0_wd_in[408]
  PIN w0_wd_in[409]
    DIRECTION OUTPUT ;
    USE SIGNAL ;
    SHAPE ABUTMENT ;
    PORT
      LAYER M3 ;
      RECT 44.271 0.000 44.289 0.054 ;
    END
  END w0_wd_in[409]
  PIN w0_wd_in[410]
    DIRECTION OUTPUT ;
    USE SIGNAL ;
    SHAPE ABUTMENT ;
    PORT
      LAYER M3 ;
      RECT 44.559 0.000 44.577 0.054 ;
    END
  END w0_wd_in[410]
  PIN w0_wd_in[411]
    DIRECTION OUTPUT ;
    USE SIGNAL ;
    SHAPE ABUTMENT ;
    PORT
      LAYER M3 ;
      RECT 44.847 0.000 44.865 0.054 ;
    END
  END w0_wd_in[411]
  PIN w0_wd_in[412]
    DIRECTION OUTPUT ;
    USE SIGNAL ;
    SHAPE ABUTMENT ;
    PORT
      LAYER M3 ;
      RECT 45.135 0.000 45.153 0.054 ;
    END
  END w0_wd_in[412]
  PIN w0_wd_in[413]
    DIRECTION OUTPUT ;
    USE SIGNAL ;
    SHAPE ABUTMENT ;
    PORT
      LAYER M3 ;
      RECT 45.423 0.000 45.441 0.054 ;
    END
  END w0_wd_in[413]
  PIN w0_wd_in[414]
    DIRECTION OUTPUT ;
    USE SIGNAL ;
    SHAPE ABUTMENT ;
    PORT
      LAYER M3 ;
      RECT 45.711 0.000 45.729 0.054 ;
    END
  END w0_wd_in[414]
  PIN w0_wd_in[415]
    DIRECTION OUTPUT ;
    USE SIGNAL ;
    SHAPE ABUTMENT ;
    PORT
      LAYER M3 ;
      RECT 45.999 0.000 46.017 0.054 ;
    END
  END w0_wd_in[415]
  PIN w0_wd_in[416]
    DIRECTION OUTPUT ;
    USE SIGNAL ;
    SHAPE ABUTMENT ;
    PORT
      LAYER M3 ;
      RECT 46.287 0.000 46.305 0.054 ;
    END
  END w0_wd_in[416]
  PIN w0_wd_in[417]
    DIRECTION OUTPUT ;
    USE SIGNAL ;
    SHAPE ABUTMENT ;
    PORT
      LAYER M3 ;
      RECT 46.575 0.000 46.593 0.054 ;
    END
  END w0_wd_in[417]
  PIN w0_wd_in[418]
    DIRECTION OUTPUT ;
    USE SIGNAL ;
    SHAPE ABUTMENT ;
    PORT
      LAYER M3 ;
      RECT 46.863 0.000 46.881 0.054 ;
    END
  END w0_wd_in[418]
  PIN w0_wd_in[419]
    DIRECTION OUTPUT ;
    USE SIGNAL ;
    SHAPE ABUTMENT ;
    PORT
      LAYER M3 ;
      RECT 47.151 0.000 47.169 0.054 ;
    END
  END w0_wd_in[419]
  PIN w0_wd_in[420]
    DIRECTION OUTPUT ;
    USE SIGNAL ;
    SHAPE ABUTMENT ;
    PORT
      LAYER M3 ;
      RECT 47.439 0.000 47.457 0.054 ;
    END
  END w0_wd_in[420]
  PIN w0_wd_in[421]
    DIRECTION OUTPUT ;
    USE SIGNAL ;
    SHAPE ABUTMENT ;
    PORT
      LAYER M3 ;
      RECT 47.727 0.000 47.745 0.054 ;
    END
  END w0_wd_in[421]
  PIN w0_wd_in[422]
    DIRECTION OUTPUT ;
    USE SIGNAL ;
    SHAPE ABUTMENT ;
    PORT
      LAYER M3 ;
      RECT 48.015 0.000 48.033 0.054 ;
    END
  END w0_wd_in[422]
  PIN w0_wd_in[423]
    DIRECTION OUTPUT ;
    USE SIGNAL ;
    SHAPE ABUTMENT ;
    PORT
      LAYER M3 ;
      RECT 48.303 0.000 48.321 0.054 ;
    END
  END w0_wd_in[423]
  PIN w0_wd_in[424]
    DIRECTION OUTPUT ;
    USE SIGNAL ;
    SHAPE ABUTMENT ;
    PORT
      LAYER M3 ;
      RECT 48.591 0.000 48.609 0.054 ;
    END
  END w0_wd_in[424]
  PIN w0_wd_in[425]
    DIRECTION OUTPUT ;
    USE SIGNAL ;
    SHAPE ABUTMENT ;
    PORT
      LAYER M3 ;
      RECT 48.879 0.000 48.897 0.054 ;
    END
  END w0_wd_in[425]
  PIN w0_wd_in[426]
    DIRECTION OUTPUT ;
    USE SIGNAL ;
    SHAPE ABUTMENT ;
    PORT
      LAYER M3 ;
      RECT 49.167 0.000 49.185 0.054 ;
    END
  END w0_wd_in[426]
  PIN w0_wd_in[427]
    DIRECTION OUTPUT ;
    USE SIGNAL ;
    SHAPE ABUTMENT ;
    PORT
      LAYER M3 ;
      RECT 49.455 0.000 49.473 0.054 ;
    END
  END w0_wd_in[427]
  PIN w0_wd_in[428]
    DIRECTION OUTPUT ;
    USE SIGNAL ;
    SHAPE ABUTMENT ;
    PORT
      LAYER M3 ;
      RECT 49.743 0.000 49.761 0.054 ;
    END
  END w0_wd_in[428]
  PIN w0_wd_in[429]
    DIRECTION OUTPUT ;
    USE SIGNAL ;
    SHAPE ABUTMENT ;
    PORT
      LAYER M3 ;
      RECT 50.031 0.000 50.049 0.054 ;
    END
  END w0_wd_in[429]
  PIN w0_wd_in[430]
    DIRECTION OUTPUT ;
    USE SIGNAL ;
    SHAPE ABUTMENT ;
    PORT
      LAYER M3 ;
      RECT 50.319 0.000 50.337 0.054 ;
    END
  END w0_wd_in[430]
  PIN w0_wd_in[431]
    DIRECTION OUTPUT ;
    USE SIGNAL ;
    SHAPE ABUTMENT ;
    PORT
      LAYER M3 ;
      RECT 50.607 0.000 50.625 0.054 ;
    END
  END w0_wd_in[431]
  PIN w0_wd_in[432]
    DIRECTION OUTPUT ;
    USE SIGNAL ;
    SHAPE ABUTMENT ;
    PORT
      LAYER M3 ;
      RECT 50.895 0.000 50.913 0.054 ;
    END
  END w0_wd_in[432]
  PIN w0_wd_in[433]
    DIRECTION OUTPUT ;
    USE SIGNAL ;
    SHAPE ABUTMENT ;
    PORT
      LAYER M3 ;
      RECT 51.183 0.000 51.201 0.054 ;
    END
  END w0_wd_in[433]
  PIN w0_wd_in[434]
    DIRECTION OUTPUT ;
    USE SIGNAL ;
    SHAPE ABUTMENT ;
    PORT
      LAYER M3 ;
      RECT 51.471 0.000 51.489 0.054 ;
    END
  END w0_wd_in[434]
  PIN w0_wd_in[435]
    DIRECTION OUTPUT ;
    USE SIGNAL ;
    SHAPE ABUTMENT ;
    PORT
      LAYER M3 ;
      RECT 51.759 0.000 51.777 0.054 ;
    END
  END w0_wd_in[435]
  PIN w0_wd_in[436]
    DIRECTION OUTPUT ;
    USE SIGNAL ;
    SHAPE ABUTMENT ;
    PORT
      LAYER M3 ;
      RECT 52.047 0.000 52.065 0.054 ;
    END
  END w0_wd_in[436]
  PIN w0_wd_in[437]
    DIRECTION OUTPUT ;
    USE SIGNAL ;
    SHAPE ABUTMENT ;
    PORT
      LAYER M3 ;
      RECT 52.335 0.000 52.353 0.054 ;
    END
  END w0_wd_in[437]
  PIN w0_wd_in[438]
    DIRECTION OUTPUT ;
    USE SIGNAL ;
    SHAPE ABUTMENT ;
    PORT
      LAYER M3 ;
      RECT 52.623 0.000 52.641 0.054 ;
    END
  END w0_wd_in[438]
  PIN w0_wd_in[439]
    DIRECTION OUTPUT ;
    USE SIGNAL ;
    SHAPE ABUTMENT ;
    PORT
      LAYER M3 ;
      RECT 52.911 0.000 52.929 0.054 ;
    END
  END w0_wd_in[439]
  PIN w0_wd_in[440]
    DIRECTION OUTPUT ;
    USE SIGNAL ;
    SHAPE ABUTMENT ;
    PORT
      LAYER M3 ;
      RECT 53.199 0.000 53.217 0.054 ;
    END
  END w0_wd_in[440]
  PIN w0_wd_in[441]
    DIRECTION OUTPUT ;
    USE SIGNAL ;
    SHAPE ABUTMENT ;
    PORT
      LAYER M3 ;
      RECT 53.487 0.000 53.505 0.054 ;
    END
  END w0_wd_in[441]
  PIN w0_wd_in[442]
    DIRECTION OUTPUT ;
    USE SIGNAL ;
    SHAPE ABUTMENT ;
    PORT
      LAYER M3 ;
      RECT 53.775 0.000 53.793 0.054 ;
    END
  END w0_wd_in[442]
  PIN w0_wd_in[443]
    DIRECTION OUTPUT ;
    USE SIGNAL ;
    SHAPE ABUTMENT ;
    PORT
      LAYER M3 ;
      RECT 54.063 0.000 54.081 0.054 ;
    END
  END w0_wd_in[443]
  PIN w0_wd_in[444]
    DIRECTION OUTPUT ;
    USE SIGNAL ;
    SHAPE ABUTMENT ;
    PORT
      LAYER M3 ;
      RECT 54.351 0.000 54.369 0.054 ;
    END
  END w0_wd_in[444]
  PIN w0_wd_in[445]
    DIRECTION OUTPUT ;
    USE SIGNAL ;
    SHAPE ABUTMENT ;
    PORT
      LAYER M3 ;
      RECT 54.639 0.000 54.657 0.054 ;
    END
  END w0_wd_in[445]
  PIN w0_wd_in[446]
    DIRECTION OUTPUT ;
    USE SIGNAL ;
    SHAPE ABUTMENT ;
    PORT
      LAYER M3 ;
      RECT 54.927 0.000 54.945 0.054 ;
    END
  END w0_wd_in[446]
  PIN w0_wd_in[447]
    DIRECTION OUTPUT ;
    USE SIGNAL ;
    SHAPE ABUTMENT ;
    PORT
      LAYER M3 ;
      RECT 55.215 0.000 55.233 0.054 ;
    END
  END w0_wd_in[447]
  PIN w0_wd_in[448]
    DIRECTION OUTPUT ;
    USE SIGNAL ;
    SHAPE ABUTMENT ;
    PORT
      LAYER M3 ;
      RECT 55.503 0.000 55.521 0.054 ;
    END
  END w0_wd_in[448]
  PIN w0_wd_in[449]
    DIRECTION OUTPUT ;
    USE SIGNAL ;
    SHAPE ABUTMENT ;
    PORT
      LAYER M3 ;
      RECT 55.791 0.000 55.809 0.054 ;
    END
  END w0_wd_in[449]
  PIN w0_wd_in[450]
    DIRECTION OUTPUT ;
    USE SIGNAL ;
    SHAPE ABUTMENT ;
    PORT
      LAYER M3 ;
      RECT 56.079 0.000 56.097 0.054 ;
    END
  END w0_wd_in[450]
  PIN w0_wd_in[451]
    DIRECTION OUTPUT ;
    USE SIGNAL ;
    SHAPE ABUTMENT ;
    PORT
      LAYER M3 ;
      RECT 56.367 0.000 56.385 0.054 ;
    END
  END w0_wd_in[451]
  PIN w0_wd_in[452]
    DIRECTION OUTPUT ;
    USE SIGNAL ;
    SHAPE ABUTMENT ;
    PORT
      LAYER M3 ;
      RECT 56.655 0.000 56.673 0.054 ;
    END
  END w0_wd_in[452]
  PIN w0_wd_in[453]
    DIRECTION OUTPUT ;
    USE SIGNAL ;
    SHAPE ABUTMENT ;
    PORT
      LAYER M3 ;
      RECT 56.943 0.000 56.961 0.054 ;
    END
  END w0_wd_in[453]
  PIN w0_wd_in[454]
    DIRECTION OUTPUT ;
    USE SIGNAL ;
    SHAPE ABUTMENT ;
    PORT
      LAYER M3 ;
      RECT 57.231 0.000 57.249 0.054 ;
    END
  END w0_wd_in[454]
  PIN w0_wd_in[455]
    DIRECTION OUTPUT ;
    USE SIGNAL ;
    SHAPE ABUTMENT ;
    PORT
      LAYER M3 ;
      RECT 57.519 0.000 57.537 0.054 ;
    END
  END w0_wd_in[455]
  PIN w0_wd_in[456]
    DIRECTION OUTPUT ;
    USE SIGNAL ;
    SHAPE ABUTMENT ;
    PORT
      LAYER M3 ;
      RECT 57.807 0.000 57.825 0.054 ;
    END
  END w0_wd_in[456]
  PIN w0_wd_in[457]
    DIRECTION OUTPUT ;
    USE SIGNAL ;
    SHAPE ABUTMENT ;
    PORT
      LAYER M3 ;
      RECT 58.095 0.000 58.113 0.054 ;
    END
  END w0_wd_in[457]
  PIN w0_wd_in[458]
    DIRECTION OUTPUT ;
    USE SIGNAL ;
    SHAPE ABUTMENT ;
    PORT
      LAYER M3 ;
      RECT 58.383 0.000 58.401 0.054 ;
    END
  END w0_wd_in[458]
  PIN w0_wd_in[459]
    DIRECTION OUTPUT ;
    USE SIGNAL ;
    SHAPE ABUTMENT ;
    PORT
      LAYER M3 ;
      RECT 58.671 0.000 58.689 0.054 ;
    END
  END w0_wd_in[459]
  PIN w0_wd_in[460]
    DIRECTION OUTPUT ;
    USE SIGNAL ;
    SHAPE ABUTMENT ;
    PORT
      LAYER M3 ;
      RECT 58.959 0.000 58.977 0.054 ;
    END
  END w0_wd_in[460]
  PIN w0_wd_in[461]
    DIRECTION OUTPUT ;
    USE SIGNAL ;
    SHAPE ABUTMENT ;
    PORT
      LAYER M3 ;
      RECT 59.247 0.000 59.265 0.054 ;
    END
  END w0_wd_in[461]
  PIN w0_wd_in[462]
    DIRECTION OUTPUT ;
    USE SIGNAL ;
    SHAPE ABUTMENT ;
    PORT
      LAYER M3 ;
      RECT 59.535 0.000 59.553 0.054 ;
    END
  END w0_wd_in[462]
  PIN w0_wd_in[463]
    DIRECTION OUTPUT ;
    USE SIGNAL ;
    SHAPE ABUTMENT ;
    PORT
      LAYER M3 ;
      RECT 59.823 0.000 59.841 0.054 ;
    END
  END w0_wd_in[463]
  PIN w0_wd_in[464]
    DIRECTION OUTPUT ;
    USE SIGNAL ;
    SHAPE ABUTMENT ;
    PORT
      LAYER M3 ;
      RECT 60.111 0.000 60.129 0.054 ;
    END
  END w0_wd_in[464]
  PIN w0_wd_in[465]
    DIRECTION OUTPUT ;
    USE SIGNAL ;
    SHAPE ABUTMENT ;
    PORT
      LAYER M3 ;
      RECT 60.399 0.000 60.417 0.054 ;
    END
  END w0_wd_in[465]
  PIN w0_wd_in[466]
    DIRECTION OUTPUT ;
    USE SIGNAL ;
    SHAPE ABUTMENT ;
    PORT
      LAYER M3 ;
      RECT 60.687 0.000 60.705 0.054 ;
    END
  END w0_wd_in[466]
  PIN w0_wd_in[467]
    DIRECTION OUTPUT ;
    USE SIGNAL ;
    SHAPE ABUTMENT ;
    PORT
      LAYER M3 ;
      RECT 60.975 0.000 60.993 0.054 ;
    END
  END w0_wd_in[467]
  PIN w0_wd_in[468]
    DIRECTION OUTPUT ;
    USE SIGNAL ;
    SHAPE ABUTMENT ;
    PORT
      LAYER M3 ;
      RECT 61.263 0.000 61.281 0.054 ;
    END
  END w0_wd_in[468]
  PIN w0_wd_in[469]
    DIRECTION OUTPUT ;
    USE SIGNAL ;
    SHAPE ABUTMENT ;
    PORT
      LAYER M3 ;
      RECT 61.551 0.000 61.569 0.054 ;
    END
  END w0_wd_in[469]
  PIN w0_wd_in[470]
    DIRECTION OUTPUT ;
    USE SIGNAL ;
    SHAPE ABUTMENT ;
    PORT
      LAYER M3 ;
      RECT 61.839 0.000 61.857 0.054 ;
    END
  END w0_wd_in[470]
  PIN w0_wd_in[471]
    DIRECTION OUTPUT ;
    USE SIGNAL ;
    SHAPE ABUTMENT ;
    PORT
      LAYER M3 ;
      RECT 62.127 0.000 62.145 0.054 ;
    END
  END w0_wd_in[471]
  PIN w0_wd_in[472]
    DIRECTION OUTPUT ;
    USE SIGNAL ;
    SHAPE ABUTMENT ;
    PORT
      LAYER M3 ;
      RECT 62.415 0.000 62.433 0.054 ;
    END
  END w0_wd_in[472]
  PIN w0_wd_in[473]
    DIRECTION OUTPUT ;
    USE SIGNAL ;
    SHAPE ABUTMENT ;
    PORT
      LAYER M3 ;
      RECT 62.703 0.000 62.721 0.054 ;
    END
  END w0_wd_in[473]
  PIN w0_wd_in[474]
    DIRECTION OUTPUT ;
    USE SIGNAL ;
    SHAPE ABUTMENT ;
    PORT
      LAYER M3 ;
      RECT 62.991 0.000 63.009 0.054 ;
    END
  END w0_wd_in[474]
  PIN w0_wd_in[475]
    DIRECTION OUTPUT ;
    USE SIGNAL ;
    SHAPE ABUTMENT ;
    PORT
      LAYER M3 ;
      RECT 63.279 0.000 63.297 0.054 ;
    END
  END w0_wd_in[475]
  PIN w0_wd_in[476]
    DIRECTION OUTPUT ;
    USE SIGNAL ;
    SHAPE ABUTMENT ;
    PORT
      LAYER M3 ;
      RECT 63.567 0.000 63.585 0.054 ;
    END
  END w0_wd_in[476]
  PIN w0_wd_in[477]
    DIRECTION OUTPUT ;
    USE SIGNAL ;
    SHAPE ABUTMENT ;
    PORT
      LAYER M3 ;
      RECT 63.855 0.000 63.873 0.054 ;
    END
  END w0_wd_in[477]
  PIN w0_wd_in[478]
    DIRECTION OUTPUT ;
    USE SIGNAL ;
    SHAPE ABUTMENT ;
    PORT
      LAYER M3 ;
      RECT 64.143 0.000 64.161 0.054 ;
    END
  END w0_wd_in[478]
  PIN w0_wd_in[479]
    DIRECTION OUTPUT ;
    USE SIGNAL ;
    SHAPE ABUTMENT ;
    PORT
      LAYER M3 ;
      RECT 64.431 0.000 64.449 0.054 ;
    END
  END w0_wd_in[479]
  PIN w0_wd_in[480]
    DIRECTION OUTPUT ;
    USE SIGNAL ;
    SHAPE ABUTMENT ;
    PORT
      LAYER M3 ;
      RECT 64.719 0.000 64.737 0.054 ;
    END
  END w0_wd_in[480]
  PIN w0_wd_in[481]
    DIRECTION OUTPUT ;
    USE SIGNAL ;
    SHAPE ABUTMENT ;
    PORT
      LAYER M3 ;
      RECT 65.007 0.000 65.025 0.054 ;
    END
  END w0_wd_in[481]
  PIN w0_wd_in[482]
    DIRECTION OUTPUT ;
    USE SIGNAL ;
    SHAPE ABUTMENT ;
    PORT
      LAYER M3 ;
      RECT 65.295 0.000 65.313 0.054 ;
    END
  END w0_wd_in[482]
  PIN w0_wd_in[483]
    DIRECTION OUTPUT ;
    USE SIGNAL ;
    SHAPE ABUTMENT ;
    PORT
      LAYER M3 ;
      RECT 65.583 0.000 65.601 0.054 ;
    END
  END w0_wd_in[483]
  PIN w0_wd_in[484]
    DIRECTION OUTPUT ;
    USE SIGNAL ;
    SHAPE ABUTMENT ;
    PORT
      LAYER M3 ;
      RECT 65.871 0.000 65.889 0.054 ;
    END
  END w0_wd_in[484]
  PIN w0_wd_in[485]
    DIRECTION OUTPUT ;
    USE SIGNAL ;
    SHAPE ABUTMENT ;
    PORT
      LAYER M3 ;
      RECT 66.159 0.000 66.177 0.054 ;
    END
  END w0_wd_in[485]
  PIN w0_wd_in[486]
    DIRECTION OUTPUT ;
    USE SIGNAL ;
    SHAPE ABUTMENT ;
    PORT
      LAYER M3 ;
      RECT 66.447 0.000 66.465 0.054 ;
    END
  END w0_wd_in[486]
  PIN w0_wd_in[487]
    DIRECTION OUTPUT ;
    USE SIGNAL ;
    SHAPE ABUTMENT ;
    PORT
      LAYER M3 ;
      RECT 66.735 0.000 66.753 0.054 ;
    END
  END w0_wd_in[487]
  PIN w0_wd_in[488]
    DIRECTION OUTPUT ;
    USE SIGNAL ;
    SHAPE ABUTMENT ;
    PORT
      LAYER M3 ;
      RECT 67.023 0.000 67.041 0.054 ;
    END
  END w0_wd_in[488]
  PIN w0_wd_in[489]
    DIRECTION OUTPUT ;
    USE SIGNAL ;
    SHAPE ABUTMENT ;
    PORT
      LAYER M3 ;
      RECT 67.311 0.000 67.329 0.054 ;
    END
  END w0_wd_in[489]
  PIN w0_wd_in[490]
    DIRECTION OUTPUT ;
    USE SIGNAL ;
    SHAPE ABUTMENT ;
    PORT
      LAYER M3 ;
      RECT 67.599 0.000 67.617 0.054 ;
    END
  END w0_wd_in[490]
  PIN w0_wd_in[491]
    DIRECTION OUTPUT ;
    USE SIGNAL ;
    SHAPE ABUTMENT ;
    PORT
      LAYER M3 ;
      RECT 67.887 0.000 67.905 0.054 ;
    END
  END w0_wd_in[491]
  PIN w0_wd_in[492]
    DIRECTION OUTPUT ;
    USE SIGNAL ;
    SHAPE ABUTMENT ;
    PORT
      LAYER M3 ;
      RECT 68.175 0.000 68.193 0.054 ;
    END
  END w0_wd_in[492]
  PIN w0_wd_in[493]
    DIRECTION OUTPUT ;
    USE SIGNAL ;
    SHAPE ABUTMENT ;
    PORT
      LAYER M3 ;
      RECT 68.463 0.000 68.481 0.054 ;
    END
  END w0_wd_in[493]
  PIN w0_wd_in[494]
    DIRECTION OUTPUT ;
    USE SIGNAL ;
    SHAPE ABUTMENT ;
    PORT
      LAYER M3 ;
      RECT 68.751 0.000 68.769 0.054 ;
    END
  END w0_wd_in[494]
  PIN w0_wd_in[495]
    DIRECTION OUTPUT ;
    USE SIGNAL ;
    SHAPE ABUTMENT ;
    PORT
      LAYER M3 ;
      RECT 69.039 0.000 69.057 0.054 ;
    END
  END w0_wd_in[495]
  PIN w0_wd_in[496]
    DIRECTION OUTPUT ;
    USE SIGNAL ;
    SHAPE ABUTMENT ;
    PORT
      LAYER M3 ;
      RECT 69.327 0.000 69.345 0.054 ;
    END
  END w0_wd_in[496]
  PIN w0_wd_in[497]
    DIRECTION OUTPUT ;
    USE SIGNAL ;
    SHAPE ABUTMENT ;
    PORT
      LAYER M3 ;
      RECT 69.615 0.000 69.633 0.054 ;
    END
  END w0_wd_in[497]
  PIN w0_wd_in[498]
    DIRECTION OUTPUT ;
    USE SIGNAL ;
    SHAPE ABUTMENT ;
    PORT
      LAYER M3 ;
      RECT 69.903 0.000 69.921 0.054 ;
    END
  END w0_wd_in[498]
  PIN w0_wd_in[499]
    DIRECTION OUTPUT ;
    USE SIGNAL ;
    SHAPE ABUTMENT ;
    PORT
      LAYER M3 ;
      RECT 70.191 0.000 70.209 0.054 ;
    END
  END w0_wd_in[499]
  PIN w0_wd_in[500]
    DIRECTION OUTPUT ;
    USE SIGNAL ;
    SHAPE ABUTMENT ;
    PORT
      LAYER M3 ;
      RECT 70.479 0.000 70.497 0.054 ;
    END
  END w0_wd_in[500]
  PIN w0_wd_in[501]
    DIRECTION OUTPUT ;
    USE SIGNAL ;
    SHAPE ABUTMENT ;
    PORT
      LAYER M3 ;
      RECT 70.767 0.000 70.785 0.054 ;
    END
  END w0_wd_in[501]
  PIN w0_wd_in[502]
    DIRECTION OUTPUT ;
    USE SIGNAL ;
    SHAPE ABUTMENT ;
    PORT
      LAYER M3 ;
      RECT 71.055 0.000 71.073 0.054 ;
    END
  END w0_wd_in[502]
  PIN w0_wd_in[503]
    DIRECTION OUTPUT ;
    USE SIGNAL ;
    SHAPE ABUTMENT ;
    PORT
      LAYER M3 ;
      RECT 71.343 0.000 71.361 0.054 ;
    END
  END w0_wd_in[503]
  PIN w0_wd_in[504]
    DIRECTION OUTPUT ;
    USE SIGNAL ;
    SHAPE ABUTMENT ;
    PORT
      LAYER M3 ;
      RECT 71.631 0.000 71.649 0.054 ;
    END
  END w0_wd_in[504]
  PIN w0_wd_in[505]
    DIRECTION OUTPUT ;
    USE SIGNAL ;
    SHAPE ABUTMENT ;
    PORT
      LAYER M3 ;
      RECT 71.919 0.000 71.937 0.054 ;
    END
  END w0_wd_in[505]
  PIN w0_wd_in[506]
    DIRECTION OUTPUT ;
    USE SIGNAL ;
    SHAPE ABUTMENT ;
    PORT
      LAYER M3 ;
      RECT 72.207 0.000 72.225 0.054 ;
    END
  END w0_wd_in[506]
  PIN w0_wd_in[507]
    DIRECTION OUTPUT ;
    USE SIGNAL ;
    SHAPE ABUTMENT ;
    PORT
      LAYER M3 ;
      RECT 72.495 0.000 72.513 0.054 ;
    END
  END w0_wd_in[507]
  PIN w0_wd_in[508]
    DIRECTION OUTPUT ;
    USE SIGNAL ;
    SHAPE ABUTMENT ;
    PORT
      LAYER M3 ;
      RECT 72.783 0.000 72.801 0.054 ;
    END
  END w0_wd_in[508]
  PIN w0_wd_in[509]
    DIRECTION OUTPUT ;
    USE SIGNAL ;
    SHAPE ABUTMENT ;
    PORT
      LAYER M3 ;
      RECT 73.071 0.000 73.089 0.054 ;
    END
  END w0_wd_in[509]
  PIN w0_wd_in[510]
    DIRECTION OUTPUT ;
    USE SIGNAL ;
    SHAPE ABUTMENT ;
    PORT
      LAYER M3 ;
      RECT 73.359 0.000 73.377 0.054 ;
    END
  END w0_wd_in[510]
  PIN w0_wd_in[511]
    DIRECTION OUTPUT ;
    USE SIGNAL ;
    SHAPE ABUTMENT ;
    PORT
      LAYER M3 ;
      RECT 73.647 0.000 73.665 0.054 ;
    END
  END w0_wd_in[511]
  PIN r0_rd_out[0]
    DIRECTION OUTPUT ;
    USE SIGNAL ;
    SHAPE ABUTMENT ;
    PORT
      LAYER M3 ;
      RECT 73.935 0.000 73.953 0.054 ;
    END
  END r0_rd_out[0]
  PIN r0_rd_out[1]
    DIRECTION OUTPUT ;
    USE SIGNAL ;
    SHAPE ABUTMENT ;
    PORT
      LAYER M3 ;
      RECT 74.223 0.000 74.241 0.054 ;
    END
  END r0_rd_out[1]
  PIN r0_rd_out[2]
    DIRECTION OUTPUT ;
    USE SIGNAL ;
    SHAPE ABUTMENT ;
    PORT
      LAYER M3 ;
      RECT 74.511 0.000 74.529 0.054 ;
    END
  END r0_rd_out[2]
  PIN r0_rd_out[3]
    DIRECTION OUTPUT ;
    USE SIGNAL ;
    SHAPE ABUTMENT ;
    PORT
      LAYER M3 ;
      RECT 74.799 0.000 74.817 0.054 ;
    END
  END r0_rd_out[3]
  PIN r0_rd_out[4]
    DIRECTION OUTPUT ;
    USE SIGNAL ;
    SHAPE ABUTMENT ;
    PORT
      LAYER M3 ;
      RECT 75.087 0.000 75.105 0.054 ;
    END
  END r0_rd_out[4]
  PIN r0_rd_out[5]
    DIRECTION OUTPUT ;
    USE SIGNAL ;
    SHAPE ABUTMENT ;
    PORT
      LAYER M3 ;
      RECT 75.375 0.000 75.393 0.054 ;
    END
  END r0_rd_out[5]
  PIN r0_rd_out[6]
    DIRECTION OUTPUT ;
    USE SIGNAL ;
    SHAPE ABUTMENT ;
    PORT
      LAYER M3 ;
      RECT 75.663 0.000 75.681 0.054 ;
    END
  END r0_rd_out[6]
  PIN r0_rd_out[7]
    DIRECTION OUTPUT ;
    USE SIGNAL ;
    SHAPE ABUTMENT ;
    PORT
      LAYER M3 ;
      RECT 75.951 0.000 75.969 0.054 ;
    END
  END r0_rd_out[7]
  PIN r0_rd_out[8]
    DIRECTION OUTPUT ;
    USE SIGNAL ;
    SHAPE ABUTMENT ;
    PORT
      LAYER M3 ;
      RECT 76.239 0.000 76.257 0.054 ;
    END
  END r0_rd_out[8]
  PIN r0_rd_out[9]
    DIRECTION OUTPUT ;
    USE SIGNAL ;
    SHAPE ABUTMENT ;
    PORT
      LAYER M3 ;
      RECT 76.527 0.000 76.545 0.054 ;
    END
  END r0_rd_out[9]
  PIN r0_rd_out[10]
    DIRECTION OUTPUT ;
    USE SIGNAL ;
    SHAPE ABUTMENT ;
    PORT
      LAYER M3 ;
      RECT 76.815 0.000 76.833 0.054 ;
    END
  END r0_rd_out[10]
  PIN r0_rd_out[11]
    DIRECTION OUTPUT ;
    USE SIGNAL ;
    SHAPE ABUTMENT ;
    PORT
      LAYER M3 ;
      RECT 77.103 0.000 77.121 0.054 ;
    END
  END r0_rd_out[11]
  PIN r0_rd_out[12]
    DIRECTION OUTPUT ;
    USE SIGNAL ;
    SHAPE ABUTMENT ;
    PORT
      LAYER M3 ;
      RECT 77.391 0.000 77.409 0.054 ;
    END
  END r0_rd_out[12]
  PIN r0_rd_out[13]
    DIRECTION OUTPUT ;
    USE SIGNAL ;
    SHAPE ABUTMENT ;
    PORT
      LAYER M3 ;
      RECT 77.679 0.000 77.697 0.054 ;
    END
  END r0_rd_out[13]
  PIN r0_rd_out[14]
    DIRECTION OUTPUT ;
    USE SIGNAL ;
    SHAPE ABUTMENT ;
    PORT
      LAYER M3 ;
      RECT 77.967 0.000 77.985 0.054 ;
    END
  END r0_rd_out[14]
  PIN r0_rd_out[15]
    DIRECTION OUTPUT ;
    USE SIGNAL ;
    SHAPE ABUTMENT ;
    PORT
      LAYER M3 ;
      RECT 78.255 0.000 78.273 0.054 ;
    END
  END r0_rd_out[15]
  PIN r0_rd_out[16]
    DIRECTION OUTPUT ;
    USE SIGNAL ;
    SHAPE ABUTMENT ;
    PORT
      LAYER M3 ;
      RECT 78.543 0.000 78.561 0.054 ;
    END
  END r0_rd_out[16]
  PIN r0_rd_out[17]
    DIRECTION OUTPUT ;
    USE SIGNAL ;
    SHAPE ABUTMENT ;
    PORT
      LAYER M3 ;
      RECT 78.831 0.000 78.849 0.054 ;
    END
  END r0_rd_out[17]
  PIN r0_rd_out[18]
    DIRECTION OUTPUT ;
    USE SIGNAL ;
    SHAPE ABUTMENT ;
    PORT
      LAYER M3 ;
      RECT 79.119 0.000 79.137 0.054 ;
    END
  END r0_rd_out[18]
  PIN r0_rd_out[19]
    DIRECTION OUTPUT ;
    USE SIGNAL ;
    SHAPE ABUTMENT ;
    PORT
      LAYER M3 ;
      RECT 79.407 0.000 79.425 0.054 ;
    END
  END r0_rd_out[19]
  PIN r0_rd_out[20]
    DIRECTION OUTPUT ;
    USE SIGNAL ;
    SHAPE ABUTMENT ;
    PORT
      LAYER M3 ;
      RECT 79.695 0.000 79.713 0.054 ;
    END
  END r0_rd_out[20]
  PIN r0_rd_out[21]
    DIRECTION OUTPUT ;
    USE SIGNAL ;
    SHAPE ABUTMENT ;
    PORT
      LAYER M3 ;
      RECT 79.983 0.000 80.001 0.054 ;
    END
  END r0_rd_out[21]
  PIN r0_rd_out[22]
    DIRECTION OUTPUT ;
    USE SIGNAL ;
    SHAPE ABUTMENT ;
    PORT
      LAYER M3 ;
      RECT 80.271 0.000 80.289 0.054 ;
    END
  END r0_rd_out[22]
  PIN r0_rd_out[23]
    DIRECTION OUTPUT ;
    USE SIGNAL ;
    SHAPE ABUTMENT ;
    PORT
      LAYER M3 ;
      RECT 80.559 0.000 80.577 0.054 ;
    END
  END r0_rd_out[23]
  PIN r0_rd_out[24]
    DIRECTION OUTPUT ;
    USE SIGNAL ;
    SHAPE ABUTMENT ;
    PORT
      LAYER M3 ;
      RECT 80.847 0.000 80.865 0.054 ;
    END
  END r0_rd_out[24]
  PIN r0_rd_out[25]
    DIRECTION OUTPUT ;
    USE SIGNAL ;
    SHAPE ABUTMENT ;
    PORT
      LAYER M3 ;
      RECT 81.135 0.000 81.153 0.054 ;
    END
  END r0_rd_out[25]
  PIN r0_rd_out[26]
    DIRECTION OUTPUT ;
    USE SIGNAL ;
    SHAPE ABUTMENT ;
    PORT
      LAYER M3 ;
      RECT 81.423 0.000 81.441 0.054 ;
    END
  END r0_rd_out[26]
  PIN r0_rd_out[27]
    DIRECTION OUTPUT ;
    USE SIGNAL ;
    SHAPE ABUTMENT ;
    PORT
      LAYER M3 ;
      RECT 81.711 0.000 81.729 0.054 ;
    END
  END r0_rd_out[27]
  PIN r0_rd_out[28]
    DIRECTION OUTPUT ;
    USE SIGNAL ;
    SHAPE ABUTMENT ;
    PORT
      LAYER M3 ;
      RECT 81.999 0.000 82.017 0.054 ;
    END
  END r0_rd_out[28]
  PIN r0_rd_out[29]
    DIRECTION OUTPUT ;
    USE SIGNAL ;
    SHAPE ABUTMENT ;
    PORT
      LAYER M3 ;
      RECT 82.287 0.000 82.305 0.054 ;
    END
  END r0_rd_out[29]
  PIN r0_rd_out[30]
    DIRECTION OUTPUT ;
    USE SIGNAL ;
    SHAPE ABUTMENT ;
    PORT
      LAYER M3 ;
      RECT 82.575 0.000 82.593 0.054 ;
    END
  END r0_rd_out[30]
  PIN r0_rd_out[31]
    DIRECTION OUTPUT ;
    USE SIGNAL ;
    SHAPE ABUTMENT ;
    PORT
      LAYER M3 ;
      RECT 82.863 0.000 82.881 0.054 ;
    END
  END r0_rd_out[31]
  PIN r0_rd_out[32]
    DIRECTION OUTPUT ;
    USE SIGNAL ;
    SHAPE ABUTMENT ;
    PORT
      LAYER M3 ;
      RECT 83.151 0.000 83.169 0.054 ;
    END
  END r0_rd_out[32]
  PIN r0_rd_out[33]
    DIRECTION OUTPUT ;
    USE SIGNAL ;
    SHAPE ABUTMENT ;
    PORT
      LAYER M3 ;
      RECT 83.439 0.000 83.457 0.054 ;
    END
  END r0_rd_out[33]
  PIN r0_rd_out[34]
    DIRECTION OUTPUT ;
    USE SIGNAL ;
    SHAPE ABUTMENT ;
    PORT
      LAYER M3 ;
      RECT 83.727 0.000 83.745 0.054 ;
    END
  END r0_rd_out[34]
  PIN r0_rd_out[35]
    DIRECTION OUTPUT ;
    USE SIGNAL ;
    SHAPE ABUTMENT ;
    PORT
      LAYER M3 ;
      RECT 84.015 0.000 84.033 0.054 ;
    END
  END r0_rd_out[35]
  PIN r0_rd_out[36]
    DIRECTION OUTPUT ;
    USE SIGNAL ;
    SHAPE ABUTMENT ;
    PORT
      LAYER M3 ;
      RECT 84.303 0.000 84.321 0.054 ;
    END
  END r0_rd_out[36]
  PIN r0_rd_out[37]
    DIRECTION OUTPUT ;
    USE SIGNAL ;
    SHAPE ABUTMENT ;
    PORT
      LAYER M3 ;
      RECT 84.591 0.000 84.609 0.054 ;
    END
  END r0_rd_out[37]
  PIN r0_rd_out[38]
    DIRECTION OUTPUT ;
    USE SIGNAL ;
    SHAPE ABUTMENT ;
    PORT
      LAYER M3 ;
      RECT 84.879 0.000 84.897 0.054 ;
    END
  END r0_rd_out[38]
  PIN r0_rd_out[39]
    DIRECTION OUTPUT ;
    USE SIGNAL ;
    SHAPE ABUTMENT ;
    PORT
      LAYER M3 ;
      RECT 85.167 0.000 85.185 0.054 ;
    END
  END r0_rd_out[39]
  PIN r0_rd_out[40]
    DIRECTION OUTPUT ;
    USE SIGNAL ;
    SHAPE ABUTMENT ;
    PORT
      LAYER M3 ;
      RECT 85.455 0.000 85.473 0.054 ;
    END
  END r0_rd_out[40]
  PIN r0_rd_out[41]
    DIRECTION OUTPUT ;
    USE SIGNAL ;
    SHAPE ABUTMENT ;
    PORT
      LAYER M3 ;
      RECT 85.743 0.000 85.761 0.054 ;
    END
  END r0_rd_out[41]
  PIN r0_rd_out[42]
    DIRECTION OUTPUT ;
    USE SIGNAL ;
    SHAPE ABUTMENT ;
    PORT
      LAYER M3 ;
      RECT 86.031 0.000 86.049 0.054 ;
    END
  END r0_rd_out[42]
  PIN r0_rd_out[43]
    DIRECTION OUTPUT ;
    USE SIGNAL ;
    SHAPE ABUTMENT ;
    PORT
      LAYER M3 ;
      RECT 86.319 0.000 86.337 0.054 ;
    END
  END r0_rd_out[43]
  PIN r0_rd_out[44]
    DIRECTION OUTPUT ;
    USE SIGNAL ;
    SHAPE ABUTMENT ;
    PORT
      LAYER M3 ;
      RECT 86.607 0.000 86.625 0.054 ;
    END
  END r0_rd_out[44]
  PIN r0_rd_out[45]
    DIRECTION OUTPUT ;
    USE SIGNAL ;
    SHAPE ABUTMENT ;
    PORT
      LAYER M3 ;
      RECT 86.895 0.000 86.913 0.054 ;
    END
  END r0_rd_out[45]
  PIN r0_rd_out[46]
    DIRECTION OUTPUT ;
    USE SIGNAL ;
    SHAPE ABUTMENT ;
    PORT
      LAYER M3 ;
      RECT 87.183 0.000 87.201 0.054 ;
    END
  END r0_rd_out[46]
  PIN r0_rd_out[47]
    DIRECTION OUTPUT ;
    USE SIGNAL ;
    SHAPE ABUTMENT ;
    PORT
      LAYER M3 ;
      RECT 87.471 0.000 87.489 0.054 ;
    END
  END r0_rd_out[47]
  PIN r0_rd_out[48]
    DIRECTION OUTPUT ;
    USE SIGNAL ;
    SHAPE ABUTMENT ;
    PORT
      LAYER M3 ;
      RECT 87.759 0.000 87.777 0.054 ;
    END
  END r0_rd_out[48]
  PIN r0_rd_out[49]
    DIRECTION OUTPUT ;
    USE SIGNAL ;
    SHAPE ABUTMENT ;
    PORT
      LAYER M3 ;
      RECT 88.047 0.000 88.065 0.054 ;
    END
  END r0_rd_out[49]
  PIN r0_rd_out[50]
    DIRECTION OUTPUT ;
    USE SIGNAL ;
    SHAPE ABUTMENT ;
    PORT
      LAYER M3 ;
      RECT 88.335 0.000 88.353 0.054 ;
    END
  END r0_rd_out[50]
  PIN r0_rd_out[51]
    DIRECTION OUTPUT ;
    USE SIGNAL ;
    SHAPE ABUTMENT ;
    PORT
      LAYER M3 ;
      RECT 88.623 0.000 88.641 0.054 ;
    END
  END r0_rd_out[51]
  PIN r0_rd_out[52]
    DIRECTION OUTPUT ;
    USE SIGNAL ;
    SHAPE ABUTMENT ;
    PORT
      LAYER M3 ;
      RECT 88.911 0.000 88.929 0.054 ;
    END
  END r0_rd_out[52]
  PIN r0_rd_out[53]
    DIRECTION OUTPUT ;
    USE SIGNAL ;
    SHAPE ABUTMENT ;
    PORT
      LAYER M3 ;
      RECT 89.199 0.000 89.217 0.054 ;
    END
  END r0_rd_out[53]
  PIN r0_rd_out[54]
    DIRECTION OUTPUT ;
    USE SIGNAL ;
    SHAPE ABUTMENT ;
    PORT
      LAYER M3 ;
      RECT 89.487 0.000 89.505 0.054 ;
    END
  END r0_rd_out[54]
  PIN r0_rd_out[55]
    DIRECTION OUTPUT ;
    USE SIGNAL ;
    SHAPE ABUTMENT ;
    PORT
      LAYER M3 ;
      RECT 89.775 0.000 89.793 0.054 ;
    END
  END r0_rd_out[55]
  PIN r0_rd_out[56]
    DIRECTION OUTPUT ;
    USE SIGNAL ;
    SHAPE ABUTMENT ;
    PORT
      LAYER M3 ;
      RECT 90.063 0.000 90.081 0.054 ;
    END
  END r0_rd_out[56]
  PIN r0_rd_out[57]
    DIRECTION OUTPUT ;
    USE SIGNAL ;
    SHAPE ABUTMENT ;
    PORT
      LAYER M3 ;
      RECT 90.351 0.000 90.369 0.054 ;
    END
  END r0_rd_out[57]
  PIN r0_rd_out[58]
    DIRECTION OUTPUT ;
    USE SIGNAL ;
    SHAPE ABUTMENT ;
    PORT
      LAYER M3 ;
      RECT 90.639 0.000 90.657 0.054 ;
    END
  END r0_rd_out[58]
  PIN r0_rd_out[59]
    DIRECTION OUTPUT ;
    USE SIGNAL ;
    SHAPE ABUTMENT ;
    PORT
      LAYER M3 ;
      RECT 90.927 0.000 90.945 0.054 ;
    END
  END r0_rd_out[59]
  PIN r0_rd_out[60]
    DIRECTION OUTPUT ;
    USE SIGNAL ;
    SHAPE ABUTMENT ;
    PORT
      LAYER M3 ;
      RECT 91.215 0.000 91.233 0.054 ;
    END
  END r0_rd_out[60]
  PIN r0_rd_out[61]
    DIRECTION OUTPUT ;
    USE SIGNAL ;
    SHAPE ABUTMENT ;
    PORT
      LAYER M3 ;
      RECT 91.503 0.000 91.521 0.054 ;
    END
  END r0_rd_out[61]
  PIN r0_rd_out[62]
    DIRECTION OUTPUT ;
    USE SIGNAL ;
    SHAPE ABUTMENT ;
    PORT
      LAYER M3 ;
      RECT 91.791 0.000 91.809 0.054 ;
    END
  END r0_rd_out[62]
  PIN r0_rd_out[63]
    DIRECTION OUTPUT ;
    USE SIGNAL ;
    SHAPE ABUTMENT ;
    PORT
      LAYER M3 ;
      RECT 92.079 0.000 92.097 0.054 ;
    END
  END r0_rd_out[63]
  PIN r0_rd_out[64]
    DIRECTION OUTPUT ;
    USE SIGNAL ;
    SHAPE ABUTMENT ;
    PORT
      LAYER M3 ;
      RECT 92.367 0.000 92.385 0.054 ;
    END
  END r0_rd_out[64]
  PIN r0_rd_out[65]
    DIRECTION OUTPUT ;
    USE SIGNAL ;
    SHAPE ABUTMENT ;
    PORT
      LAYER M3 ;
      RECT 92.655 0.000 92.673 0.054 ;
    END
  END r0_rd_out[65]
  PIN r0_rd_out[66]
    DIRECTION OUTPUT ;
    USE SIGNAL ;
    SHAPE ABUTMENT ;
    PORT
      LAYER M3 ;
      RECT 92.943 0.000 92.961 0.054 ;
    END
  END r0_rd_out[66]
  PIN r0_rd_out[67]
    DIRECTION OUTPUT ;
    USE SIGNAL ;
    SHAPE ABUTMENT ;
    PORT
      LAYER M3 ;
      RECT 93.231 0.000 93.249 0.054 ;
    END
  END r0_rd_out[67]
  PIN r0_rd_out[68]
    DIRECTION OUTPUT ;
    USE SIGNAL ;
    SHAPE ABUTMENT ;
    PORT
      LAYER M3 ;
      RECT 93.519 0.000 93.537 0.054 ;
    END
  END r0_rd_out[68]
  PIN r0_rd_out[69]
    DIRECTION OUTPUT ;
    USE SIGNAL ;
    SHAPE ABUTMENT ;
    PORT
      LAYER M3 ;
      RECT 93.807 0.000 93.825 0.054 ;
    END
  END r0_rd_out[69]
  PIN r0_rd_out[70]
    DIRECTION OUTPUT ;
    USE SIGNAL ;
    SHAPE ABUTMENT ;
    PORT
      LAYER M3 ;
      RECT 94.095 0.000 94.113 0.054 ;
    END
  END r0_rd_out[70]
  PIN r0_rd_out[71]
    DIRECTION OUTPUT ;
    USE SIGNAL ;
    SHAPE ABUTMENT ;
    PORT
      LAYER M3 ;
      RECT 94.383 0.000 94.401 0.054 ;
    END
  END r0_rd_out[71]
  PIN r0_rd_out[72]
    DIRECTION OUTPUT ;
    USE SIGNAL ;
    SHAPE ABUTMENT ;
    PORT
      LAYER M3 ;
      RECT 94.671 0.000 94.689 0.054 ;
    END
  END r0_rd_out[72]
  PIN r0_rd_out[73]
    DIRECTION OUTPUT ;
    USE SIGNAL ;
    SHAPE ABUTMENT ;
    PORT
      LAYER M3 ;
      RECT 94.959 0.000 94.977 0.054 ;
    END
  END r0_rd_out[73]
  PIN r0_rd_out[74]
    DIRECTION OUTPUT ;
    USE SIGNAL ;
    SHAPE ABUTMENT ;
    PORT
      LAYER M3 ;
      RECT 95.247 0.000 95.265 0.054 ;
    END
  END r0_rd_out[74]
  PIN r0_rd_out[75]
    DIRECTION OUTPUT ;
    USE SIGNAL ;
    SHAPE ABUTMENT ;
    PORT
      LAYER M3 ;
      RECT 95.535 0.000 95.553 0.054 ;
    END
  END r0_rd_out[75]
  PIN r0_rd_out[76]
    DIRECTION OUTPUT ;
    USE SIGNAL ;
    SHAPE ABUTMENT ;
    PORT
      LAYER M3 ;
      RECT 95.823 0.000 95.841 0.054 ;
    END
  END r0_rd_out[76]
  PIN r0_rd_out[77]
    DIRECTION OUTPUT ;
    USE SIGNAL ;
    SHAPE ABUTMENT ;
    PORT
      LAYER M3 ;
      RECT 96.111 0.000 96.129 0.054 ;
    END
  END r0_rd_out[77]
  PIN r0_rd_out[78]
    DIRECTION OUTPUT ;
    USE SIGNAL ;
    SHAPE ABUTMENT ;
    PORT
      LAYER M3 ;
      RECT 96.399 0.000 96.417 0.054 ;
    END
  END r0_rd_out[78]
  PIN r0_rd_out[79]
    DIRECTION OUTPUT ;
    USE SIGNAL ;
    SHAPE ABUTMENT ;
    PORT
      LAYER M3 ;
      RECT 96.687 0.000 96.705 0.054 ;
    END
  END r0_rd_out[79]
  PIN r0_rd_out[80]
    DIRECTION OUTPUT ;
    USE SIGNAL ;
    SHAPE ABUTMENT ;
    PORT
      LAYER M3 ;
      RECT 96.975 0.000 96.993 0.054 ;
    END
  END r0_rd_out[80]
  PIN r0_rd_out[81]
    DIRECTION OUTPUT ;
    USE SIGNAL ;
    SHAPE ABUTMENT ;
    PORT
      LAYER M3 ;
      RECT 97.263 0.000 97.281 0.054 ;
    END
  END r0_rd_out[81]
  PIN r0_rd_out[82]
    DIRECTION OUTPUT ;
    USE SIGNAL ;
    SHAPE ABUTMENT ;
    PORT
      LAYER M3 ;
      RECT 97.551 0.000 97.569 0.054 ;
    END
  END r0_rd_out[82]
  PIN r0_rd_out[83]
    DIRECTION OUTPUT ;
    USE SIGNAL ;
    SHAPE ABUTMENT ;
    PORT
      LAYER M3 ;
      RECT 97.839 0.000 97.857 0.054 ;
    END
  END r0_rd_out[83]
  PIN r0_rd_out[84]
    DIRECTION OUTPUT ;
    USE SIGNAL ;
    SHAPE ABUTMENT ;
    PORT
      LAYER M3 ;
      RECT 98.127 0.000 98.145 0.054 ;
    END
  END r0_rd_out[84]
  PIN r0_rd_out[85]
    DIRECTION OUTPUT ;
    USE SIGNAL ;
    SHAPE ABUTMENT ;
    PORT
      LAYER M3 ;
      RECT 98.415 0.000 98.433 0.054 ;
    END
  END r0_rd_out[85]
  PIN r0_rd_out[86]
    DIRECTION OUTPUT ;
    USE SIGNAL ;
    SHAPE ABUTMENT ;
    PORT
      LAYER M3 ;
      RECT 98.703 0.000 98.721 0.054 ;
    END
  END r0_rd_out[86]
  PIN r0_rd_out[87]
    DIRECTION OUTPUT ;
    USE SIGNAL ;
    SHAPE ABUTMENT ;
    PORT
      LAYER M3 ;
      RECT 98.991 0.000 99.009 0.054 ;
    END
  END r0_rd_out[87]
  PIN r0_rd_out[88]
    DIRECTION OUTPUT ;
    USE SIGNAL ;
    SHAPE ABUTMENT ;
    PORT
      LAYER M3 ;
      RECT 99.279 0.000 99.297 0.054 ;
    END
  END r0_rd_out[88]
  PIN r0_rd_out[89]
    DIRECTION OUTPUT ;
    USE SIGNAL ;
    SHAPE ABUTMENT ;
    PORT
      LAYER M3 ;
      RECT 99.567 0.000 99.585 0.054 ;
    END
  END r0_rd_out[89]
  PIN r0_rd_out[90]
    DIRECTION OUTPUT ;
    USE SIGNAL ;
    SHAPE ABUTMENT ;
    PORT
      LAYER M3 ;
      RECT 99.855 0.000 99.873 0.054 ;
    END
  END r0_rd_out[90]
  PIN r0_rd_out[91]
    DIRECTION OUTPUT ;
    USE SIGNAL ;
    SHAPE ABUTMENT ;
    PORT
      LAYER M3 ;
      RECT 100.143 0.000 100.161 0.054 ;
    END
  END r0_rd_out[91]
  PIN r0_rd_out[92]
    DIRECTION OUTPUT ;
    USE SIGNAL ;
    SHAPE ABUTMENT ;
    PORT
      LAYER M3 ;
      RECT 100.431 0.000 100.449 0.054 ;
    END
  END r0_rd_out[92]
  PIN r0_rd_out[93]
    DIRECTION OUTPUT ;
    USE SIGNAL ;
    SHAPE ABUTMENT ;
    PORT
      LAYER M3 ;
      RECT 100.719 0.000 100.737 0.054 ;
    END
  END r0_rd_out[93]
  PIN r0_rd_out[94]
    DIRECTION OUTPUT ;
    USE SIGNAL ;
    SHAPE ABUTMENT ;
    PORT
      LAYER M3 ;
      RECT 101.007 0.000 101.025 0.054 ;
    END
  END r0_rd_out[94]
  PIN r0_rd_out[95]
    DIRECTION OUTPUT ;
    USE SIGNAL ;
    SHAPE ABUTMENT ;
    PORT
      LAYER M3 ;
      RECT 101.295 0.000 101.313 0.054 ;
    END
  END r0_rd_out[95]
  PIN r0_rd_out[96]
    DIRECTION OUTPUT ;
    USE SIGNAL ;
    SHAPE ABUTMENT ;
    PORT
      LAYER M3 ;
      RECT 101.583 0.000 101.601 0.054 ;
    END
  END r0_rd_out[96]
  PIN r0_rd_out[97]
    DIRECTION OUTPUT ;
    USE SIGNAL ;
    SHAPE ABUTMENT ;
    PORT
      LAYER M3 ;
      RECT 101.871 0.000 101.889 0.054 ;
    END
  END r0_rd_out[97]
  PIN r0_rd_out[98]
    DIRECTION OUTPUT ;
    USE SIGNAL ;
    SHAPE ABUTMENT ;
    PORT
      LAYER M3 ;
      RECT 102.159 0.000 102.177 0.054 ;
    END
  END r0_rd_out[98]
  PIN r0_rd_out[99]
    DIRECTION OUTPUT ;
    USE SIGNAL ;
    SHAPE ABUTMENT ;
    PORT
      LAYER M3 ;
      RECT 102.447 0.000 102.465 0.054 ;
    END
  END r0_rd_out[99]
  PIN r0_rd_out[100]
    DIRECTION OUTPUT ;
    USE SIGNAL ;
    SHAPE ABUTMENT ;
    PORT
      LAYER M3 ;
      RECT 102.735 0.000 102.753 0.054 ;
    END
  END r0_rd_out[100]
  PIN r0_rd_out[101]
    DIRECTION OUTPUT ;
    USE SIGNAL ;
    SHAPE ABUTMENT ;
    PORT
      LAYER M3 ;
      RECT 103.023 0.000 103.041 0.054 ;
    END
  END r0_rd_out[101]
  PIN r0_rd_out[102]
    DIRECTION OUTPUT ;
    USE SIGNAL ;
    SHAPE ABUTMENT ;
    PORT
      LAYER M3 ;
      RECT 103.311 0.000 103.329 0.054 ;
    END
  END r0_rd_out[102]
  PIN r0_rd_out[103]
    DIRECTION OUTPUT ;
    USE SIGNAL ;
    SHAPE ABUTMENT ;
    PORT
      LAYER M3 ;
      RECT 103.599 0.000 103.617 0.054 ;
    END
  END r0_rd_out[103]
  PIN r0_rd_out[104]
    DIRECTION OUTPUT ;
    USE SIGNAL ;
    SHAPE ABUTMENT ;
    PORT
      LAYER M3 ;
      RECT 103.887 0.000 103.905 0.054 ;
    END
  END r0_rd_out[104]
  PIN r0_rd_out[105]
    DIRECTION OUTPUT ;
    USE SIGNAL ;
    SHAPE ABUTMENT ;
    PORT
      LAYER M3 ;
      RECT 104.175 0.000 104.193 0.054 ;
    END
  END r0_rd_out[105]
  PIN r0_rd_out[106]
    DIRECTION OUTPUT ;
    USE SIGNAL ;
    SHAPE ABUTMENT ;
    PORT
      LAYER M3 ;
      RECT 104.463 0.000 104.481 0.054 ;
    END
  END r0_rd_out[106]
  PIN r0_rd_out[107]
    DIRECTION OUTPUT ;
    USE SIGNAL ;
    SHAPE ABUTMENT ;
    PORT
      LAYER M3 ;
      RECT 104.751 0.000 104.769 0.054 ;
    END
  END r0_rd_out[107]
  PIN r0_rd_out[108]
    DIRECTION OUTPUT ;
    USE SIGNAL ;
    SHAPE ABUTMENT ;
    PORT
      LAYER M3 ;
      RECT 105.039 0.000 105.057 0.054 ;
    END
  END r0_rd_out[108]
  PIN r0_rd_out[109]
    DIRECTION OUTPUT ;
    USE SIGNAL ;
    SHAPE ABUTMENT ;
    PORT
      LAYER M3 ;
      RECT 105.327 0.000 105.345 0.054 ;
    END
  END r0_rd_out[109]
  PIN r0_rd_out[110]
    DIRECTION OUTPUT ;
    USE SIGNAL ;
    SHAPE ABUTMENT ;
    PORT
      LAYER M3 ;
      RECT 105.615 0.000 105.633 0.054 ;
    END
  END r0_rd_out[110]
  PIN r0_rd_out[111]
    DIRECTION OUTPUT ;
    USE SIGNAL ;
    SHAPE ABUTMENT ;
    PORT
      LAYER M3 ;
      RECT 105.903 0.000 105.921 0.054 ;
    END
  END r0_rd_out[111]
  PIN r0_rd_out[112]
    DIRECTION OUTPUT ;
    USE SIGNAL ;
    SHAPE ABUTMENT ;
    PORT
      LAYER M3 ;
      RECT 106.191 0.000 106.209 0.054 ;
    END
  END r0_rd_out[112]
  PIN r0_rd_out[113]
    DIRECTION OUTPUT ;
    USE SIGNAL ;
    SHAPE ABUTMENT ;
    PORT
      LAYER M3 ;
      RECT 106.479 0.000 106.497 0.054 ;
    END
  END r0_rd_out[113]
  PIN r0_rd_out[114]
    DIRECTION OUTPUT ;
    USE SIGNAL ;
    SHAPE ABUTMENT ;
    PORT
      LAYER M3 ;
      RECT 106.767 0.000 106.785 0.054 ;
    END
  END r0_rd_out[114]
  PIN r0_rd_out[115]
    DIRECTION OUTPUT ;
    USE SIGNAL ;
    SHAPE ABUTMENT ;
    PORT
      LAYER M3 ;
      RECT 107.055 0.000 107.073 0.054 ;
    END
  END r0_rd_out[115]
  PIN r0_rd_out[116]
    DIRECTION OUTPUT ;
    USE SIGNAL ;
    SHAPE ABUTMENT ;
    PORT
      LAYER M3 ;
      RECT 107.343 0.000 107.361 0.054 ;
    END
  END r0_rd_out[116]
  PIN r0_rd_out[117]
    DIRECTION OUTPUT ;
    USE SIGNAL ;
    SHAPE ABUTMENT ;
    PORT
      LAYER M3 ;
      RECT 107.631 0.000 107.649 0.054 ;
    END
  END r0_rd_out[117]
  PIN r0_rd_out[118]
    DIRECTION OUTPUT ;
    USE SIGNAL ;
    SHAPE ABUTMENT ;
    PORT
      LAYER M3 ;
      RECT 107.919 0.000 107.937 0.054 ;
    END
  END r0_rd_out[118]
  PIN r0_rd_out[119]
    DIRECTION OUTPUT ;
    USE SIGNAL ;
    SHAPE ABUTMENT ;
    PORT
      LAYER M3 ;
      RECT 108.207 0.000 108.225 0.054 ;
    END
  END r0_rd_out[119]
  PIN r0_rd_out[120]
    DIRECTION OUTPUT ;
    USE SIGNAL ;
    SHAPE ABUTMENT ;
    PORT
      LAYER M3 ;
      RECT 108.495 0.000 108.513 0.054 ;
    END
  END r0_rd_out[120]
  PIN r0_rd_out[121]
    DIRECTION OUTPUT ;
    USE SIGNAL ;
    SHAPE ABUTMENT ;
    PORT
      LAYER M3 ;
      RECT 108.783 0.000 108.801 0.054 ;
    END
  END r0_rd_out[121]
  PIN r0_rd_out[122]
    DIRECTION OUTPUT ;
    USE SIGNAL ;
    SHAPE ABUTMENT ;
    PORT
      LAYER M3 ;
      RECT 109.071 0.000 109.089 0.054 ;
    END
  END r0_rd_out[122]
  PIN r0_rd_out[123]
    DIRECTION OUTPUT ;
    USE SIGNAL ;
    SHAPE ABUTMENT ;
    PORT
      LAYER M3 ;
      RECT 109.359 0.000 109.377 0.054 ;
    END
  END r0_rd_out[123]
  PIN r0_rd_out[124]
    DIRECTION OUTPUT ;
    USE SIGNAL ;
    SHAPE ABUTMENT ;
    PORT
      LAYER M3 ;
      RECT 109.647 0.000 109.665 0.054 ;
    END
  END r0_rd_out[124]
  PIN r0_rd_out[125]
    DIRECTION OUTPUT ;
    USE SIGNAL ;
    SHAPE ABUTMENT ;
    PORT
      LAYER M3 ;
      RECT 109.935 0.000 109.953 0.054 ;
    END
  END r0_rd_out[125]
  PIN r0_rd_out[126]
    DIRECTION OUTPUT ;
    USE SIGNAL ;
    SHAPE ABUTMENT ;
    PORT
      LAYER M3 ;
      RECT 110.223 0.000 110.241 0.054 ;
    END
  END r0_rd_out[126]
  PIN r0_rd_out[127]
    DIRECTION OUTPUT ;
    USE SIGNAL ;
    SHAPE ABUTMENT ;
    PORT
      LAYER M3 ;
      RECT 110.511 0.000 110.529 0.054 ;
    END
  END r0_rd_out[127]
  PIN r0_rd_out[128]
    DIRECTION OUTPUT ;
    USE SIGNAL ;
    SHAPE ABUTMENT ;
    PORT
      LAYER M3 ;
      RECT 110.799 0.000 110.817 0.054 ;
    END
  END r0_rd_out[128]
  PIN r0_rd_out[129]
    DIRECTION OUTPUT ;
    USE SIGNAL ;
    SHAPE ABUTMENT ;
    PORT
      LAYER M3 ;
      RECT 111.087 0.000 111.105 0.054 ;
    END
  END r0_rd_out[129]
  PIN r0_rd_out[130]
    DIRECTION OUTPUT ;
    USE SIGNAL ;
    SHAPE ABUTMENT ;
    PORT
      LAYER M3 ;
      RECT 111.375 0.000 111.393 0.054 ;
    END
  END r0_rd_out[130]
  PIN r0_rd_out[131]
    DIRECTION OUTPUT ;
    USE SIGNAL ;
    SHAPE ABUTMENT ;
    PORT
      LAYER M3 ;
      RECT 111.663 0.000 111.681 0.054 ;
    END
  END r0_rd_out[131]
  PIN r0_rd_out[132]
    DIRECTION OUTPUT ;
    USE SIGNAL ;
    SHAPE ABUTMENT ;
    PORT
      LAYER M3 ;
      RECT 111.951 0.000 111.969 0.054 ;
    END
  END r0_rd_out[132]
  PIN r0_rd_out[133]
    DIRECTION OUTPUT ;
    USE SIGNAL ;
    SHAPE ABUTMENT ;
    PORT
      LAYER M3 ;
      RECT 112.239 0.000 112.257 0.054 ;
    END
  END r0_rd_out[133]
  PIN r0_rd_out[134]
    DIRECTION OUTPUT ;
    USE SIGNAL ;
    SHAPE ABUTMENT ;
    PORT
      LAYER M3 ;
      RECT 112.527 0.000 112.545 0.054 ;
    END
  END r0_rd_out[134]
  PIN r0_rd_out[135]
    DIRECTION OUTPUT ;
    USE SIGNAL ;
    SHAPE ABUTMENT ;
    PORT
      LAYER M3 ;
      RECT 112.815 0.000 112.833 0.054 ;
    END
  END r0_rd_out[135]
  PIN r0_rd_out[136]
    DIRECTION OUTPUT ;
    USE SIGNAL ;
    SHAPE ABUTMENT ;
    PORT
      LAYER M3 ;
      RECT 113.103 0.000 113.121 0.054 ;
    END
  END r0_rd_out[136]
  PIN r0_rd_out[137]
    DIRECTION OUTPUT ;
    USE SIGNAL ;
    SHAPE ABUTMENT ;
    PORT
      LAYER M3 ;
      RECT 113.391 0.000 113.409 0.054 ;
    END
  END r0_rd_out[137]
  PIN r0_rd_out[138]
    DIRECTION OUTPUT ;
    USE SIGNAL ;
    SHAPE ABUTMENT ;
    PORT
      LAYER M3 ;
      RECT 113.679 0.000 113.697 0.054 ;
    END
  END r0_rd_out[138]
  PIN r0_rd_out[139]
    DIRECTION OUTPUT ;
    USE SIGNAL ;
    SHAPE ABUTMENT ;
    PORT
      LAYER M3 ;
      RECT 113.967 0.000 113.985 0.054 ;
    END
  END r0_rd_out[139]
  PIN r0_rd_out[140]
    DIRECTION OUTPUT ;
    USE SIGNAL ;
    SHAPE ABUTMENT ;
    PORT
      LAYER M3 ;
      RECT 114.255 0.000 114.273 0.054 ;
    END
  END r0_rd_out[140]
  PIN r0_rd_out[141]
    DIRECTION OUTPUT ;
    USE SIGNAL ;
    SHAPE ABUTMENT ;
    PORT
      LAYER M3 ;
      RECT 114.543 0.000 114.561 0.054 ;
    END
  END r0_rd_out[141]
  PIN r0_rd_out[142]
    DIRECTION OUTPUT ;
    USE SIGNAL ;
    SHAPE ABUTMENT ;
    PORT
      LAYER M3 ;
      RECT 114.831 0.000 114.849 0.054 ;
    END
  END r0_rd_out[142]
  PIN r0_rd_out[143]
    DIRECTION OUTPUT ;
    USE SIGNAL ;
    SHAPE ABUTMENT ;
    PORT
      LAYER M3 ;
      RECT 115.119 0.000 115.137 0.054 ;
    END
  END r0_rd_out[143]
  PIN r0_rd_out[144]
    DIRECTION OUTPUT ;
    USE SIGNAL ;
    SHAPE ABUTMENT ;
    PORT
      LAYER M3 ;
      RECT 115.407 0.000 115.425 0.054 ;
    END
  END r0_rd_out[144]
  PIN r0_rd_out[145]
    DIRECTION OUTPUT ;
    USE SIGNAL ;
    SHAPE ABUTMENT ;
    PORT
      LAYER M3 ;
      RECT 115.695 0.000 115.713 0.054 ;
    END
  END r0_rd_out[145]
  PIN r0_rd_out[146]
    DIRECTION OUTPUT ;
    USE SIGNAL ;
    SHAPE ABUTMENT ;
    PORT
      LAYER M3 ;
      RECT 115.983 0.000 116.001 0.054 ;
    END
  END r0_rd_out[146]
  PIN r0_rd_out[147]
    DIRECTION OUTPUT ;
    USE SIGNAL ;
    SHAPE ABUTMENT ;
    PORT
      LAYER M3 ;
      RECT 116.271 0.000 116.289 0.054 ;
    END
  END r0_rd_out[147]
  PIN r0_rd_out[148]
    DIRECTION OUTPUT ;
    USE SIGNAL ;
    SHAPE ABUTMENT ;
    PORT
      LAYER M3 ;
      RECT 116.559 0.000 116.577 0.054 ;
    END
  END r0_rd_out[148]
  PIN r0_rd_out[149]
    DIRECTION OUTPUT ;
    USE SIGNAL ;
    SHAPE ABUTMENT ;
    PORT
      LAYER M3 ;
      RECT 116.847 0.000 116.865 0.054 ;
    END
  END r0_rd_out[149]
  PIN r0_rd_out[150]
    DIRECTION OUTPUT ;
    USE SIGNAL ;
    SHAPE ABUTMENT ;
    PORT
      LAYER M3 ;
      RECT 117.135 0.000 117.153 0.054 ;
    END
  END r0_rd_out[150]
  PIN r0_rd_out[151]
    DIRECTION OUTPUT ;
    USE SIGNAL ;
    SHAPE ABUTMENT ;
    PORT
      LAYER M3 ;
      RECT 117.423 0.000 117.441 0.054 ;
    END
  END r0_rd_out[151]
  PIN r0_rd_out[152]
    DIRECTION OUTPUT ;
    USE SIGNAL ;
    SHAPE ABUTMENT ;
    PORT
      LAYER M3 ;
      RECT 117.711 0.000 117.729 0.054 ;
    END
  END r0_rd_out[152]
  PIN r0_rd_out[153]
    DIRECTION OUTPUT ;
    USE SIGNAL ;
    SHAPE ABUTMENT ;
    PORT
      LAYER M3 ;
      RECT 117.999 0.000 118.017 0.054 ;
    END
  END r0_rd_out[153]
  PIN r0_rd_out[154]
    DIRECTION OUTPUT ;
    USE SIGNAL ;
    SHAPE ABUTMENT ;
    PORT
      LAYER M3 ;
      RECT 118.287 0.000 118.305 0.054 ;
    END
  END r0_rd_out[154]
  PIN r0_rd_out[155]
    DIRECTION OUTPUT ;
    USE SIGNAL ;
    SHAPE ABUTMENT ;
    PORT
      LAYER M3 ;
      RECT 118.575 0.000 118.593 0.054 ;
    END
  END r0_rd_out[155]
  PIN r0_rd_out[156]
    DIRECTION OUTPUT ;
    USE SIGNAL ;
    SHAPE ABUTMENT ;
    PORT
      LAYER M3 ;
      RECT 118.863 0.000 118.881 0.054 ;
    END
  END r0_rd_out[156]
  PIN r0_rd_out[157]
    DIRECTION OUTPUT ;
    USE SIGNAL ;
    SHAPE ABUTMENT ;
    PORT
      LAYER M3 ;
      RECT 119.151 0.000 119.169 0.054 ;
    END
  END r0_rd_out[157]
  PIN r0_rd_out[158]
    DIRECTION OUTPUT ;
    USE SIGNAL ;
    SHAPE ABUTMENT ;
    PORT
      LAYER M3 ;
      RECT 119.439 0.000 119.457 0.054 ;
    END
  END r0_rd_out[158]
  PIN r0_rd_out[159]
    DIRECTION OUTPUT ;
    USE SIGNAL ;
    SHAPE ABUTMENT ;
    PORT
      LAYER M3 ;
      RECT 119.727 0.000 119.745 0.054 ;
    END
  END r0_rd_out[159]
  PIN r0_rd_out[160]
    DIRECTION OUTPUT ;
    USE SIGNAL ;
    SHAPE ABUTMENT ;
    PORT
      LAYER M3 ;
      RECT 120.015 0.000 120.033 0.054 ;
    END
  END r0_rd_out[160]
  PIN r0_rd_out[161]
    DIRECTION OUTPUT ;
    USE SIGNAL ;
    SHAPE ABUTMENT ;
    PORT
      LAYER M3 ;
      RECT 120.303 0.000 120.321 0.054 ;
    END
  END r0_rd_out[161]
  PIN r0_rd_out[162]
    DIRECTION OUTPUT ;
    USE SIGNAL ;
    SHAPE ABUTMENT ;
    PORT
      LAYER M3 ;
      RECT 120.591 0.000 120.609 0.054 ;
    END
  END r0_rd_out[162]
  PIN r0_rd_out[163]
    DIRECTION OUTPUT ;
    USE SIGNAL ;
    SHAPE ABUTMENT ;
    PORT
      LAYER M3 ;
      RECT 120.879 0.000 120.897 0.054 ;
    END
  END r0_rd_out[163]
  PIN r0_rd_out[164]
    DIRECTION OUTPUT ;
    USE SIGNAL ;
    SHAPE ABUTMENT ;
    PORT
      LAYER M3 ;
      RECT 121.167 0.000 121.185 0.054 ;
    END
  END r0_rd_out[164]
  PIN r0_rd_out[165]
    DIRECTION OUTPUT ;
    USE SIGNAL ;
    SHAPE ABUTMENT ;
    PORT
      LAYER M3 ;
      RECT 121.455 0.000 121.473 0.054 ;
    END
  END r0_rd_out[165]
  PIN r0_rd_out[166]
    DIRECTION OUTPUT ;
    USE SIGNAL ;
    SHAPE ABUTMENT ;
    PORT
      LAYER M3 ;
      RECT 121.743 0.000 121.761 0.054 ;
    END
  END r0_rd_out[166]
  PIN r0_rd_out[167]
    DIRECTION OUTPUT ;
    USE SIGNAL ;
    SHAPE ABUTMENT ;
    PORT
      LAYER M3 ;
      RECT 122.031 0.000 122.049 0.054 ;
    END
  END r0_rd_out[167]
  PIN r0_rd_out[168]
    DIRECTION OUTPUT ;
    USE SIGNAL ;
    SHAPE ABUTMENT ;
    PORT
      LAYER M3 ;
      RECT 122.319 0.000 122.337 0.054 ;
    END
  END r0_rd_out[168]
  PIN r0_rd_out[169]
    DIRECTION OUTPUT ;
    USE SIGNAL ;
    SHAPE ABUTMENT ;
    PORT
      LAYER M3 ;
      RECT 122.607 0.000 122.625 0.054 ;
    END
  END r0_rd_out[169]
  PIN r0_rd_out[170]
    DIRECTION OUTPUT ;
    USE SIGNAL ;
    SHAPE ABUTMENT ;
    PORT
      LAYER M3 ;
      RECT 122.895 0.000 122.913 0.054 ;
    END
  END r0_rd_out[170]
  PIN r0_rd_out[171]
    DIRECTION OUTPUT ;
    USE SIGNAL ;
    SHAPE ABUTMENT ;
    PORT
      LAYER M3 ;
      RECT 123.183 0.000 123.201 0.054 ;
    END
  END r0_rd_out[171]
  PIN r0_rd_out[172]
    DIRECTION OUTPUT ;
    USE SIGNAL ;
    SHAPE ABUTMENT ;
    PORT
      LAYER M3 ;
      RECT 123.471 0.000 123.489 0.054 ;
    END
  END r0_rd_out[172]
  PIN r0_rd_out[173]
    DIRECTION OUTPUT ;
    USE SIGNAL ;
    SHAPE ABUTMENT ;
    PORT
      LAYER M3 ;
      RECT 123.759 0.000 123.777 0.054 ;
    END
  END r0_rd_out[173]
  PIN r0_rd_out[174]
    DIRECTION OUTPUT ;
    USE SIGNAL ;
    SHAPE ABUTMENT ;
    PORT
      LAYER M3 ;
      RECT 124.047 0.000 124.065 0.054 ;
    END
  END r0_rd_out[174]
  PIN r0_rd_out[175]
    DIRECTION OUTPUT ;
    USE SIGNAL ;
    SHAPE ABUTMENT ;
    PORT
      LAYER M3 ;
      RECT 124.335 0.000 124.353 0.054 ;
    END
  END r0_rd_out[175]
  PIN r0_rd_out[176]
    DIRECTION OUTPUT ;
    USE SIGNAL ;
    SHAPE ABUTMENT ;
    PORT
      LAYER M3 ;
      RECT 124.623 0.000 124.641 0.054 ;
    END
  END r0_rd_out[176]
  PIN r0_rd_out[177]
    DIRECTION OUTPUT ;
    USE SIGNAL ;
    SHAPE ABUTMENT ;
    PORT
      LAYER M3 ;
      RECT 124.911 0.000 124.929 0.054 ;
    END
  END r0_rd_out[177]
  PIN r0_rd_out[178]
    DIRECTION OUTPUT ;
    USE SIGNAL ;
    SHAPE ABUTMENT ;
    PORT
      LAYER M3 ;
      RECT 125.199 0.000 125.217 0.054 ;
    END
  END r0_rd_out[178]
  PIN r0_rd_out[179]
    DIRECTION OUTPUT ;
    USE SIGNAL ;
    SHAPE ABUTMENT ;
    PORT
      LAYER M3 ;
      RECT 125.487 0.000 125.505 0.054 ;
    END
  END r0_rd_out[179]
  PIN r0_rd_out[180]
    DIRECTION OUTPUT ;
    USE SIGNAL ;
    SHAPE ABUTMENT ;
    PORT
      LAYER M3 ;
      RECT 125.775 0.000 125.793 0.054 ;
    END
  END r0_rd_out[180]
  PIN r0_rd_out[181]
    DIRECTION OUTPUT ;
    USE SIGNAL ;
    SHAPE ABUTMENT ;
    PORT
      LAYER M3 ;
      RECT 126.063 0.000 126.081 0.054 ;
    END
  END r0_rd_out[181]
  PIN r0_rd_out[182]
    DIRECTION OUTPUT ;
    USE SIGNAL ;
    SHAPE ABUTMENT ;
    PORT
      LAYER M3 ;
      RECT 126.351 0.000 126.369 0.054 ;
    END
  END r0_rd_out[182]
  PIN r0_rd_out[183]
    DIRECTION OUTPUT ;
    USE SIGNAL ;
    SHAPE ABUTMENT ;
    PORT
      LAYER M3 ;
      RECT 126.639 0.000 126.657 0.054 ;
    END
  END r0_rd_out[183]
  PIN r0_rd_out[184]
    DIRECTION OUTPUT ;
    USE SIGNAL ;
    SHAPE ABUTMENT ;
    PORT
      LAYER M3 ;
      RECT 126.927 0.000 126.945 0.054 ;
    END
  END r0_rd_out[184]
  PIN r0_rd_out[185]
    DIRECTION OUTPUT ;
    USE SIGNAL ;
    SHAPE ABUTMENT ;
    PORT
      LAYER M3 ;
      RECT 127.215 0.000 127.233 0.054 ;
    END
  END r0_rd_out[185]
  PIN r0_rd_out[186]
    DIRECTION OUTPUT ;
    USE SIGNAL ;
    SHAPE ABUTMENT ;
    PORT
      LAYER M3 ;
      RECT 127.503 0.000 127.521 0.054 ;
    END
  END r0_rd_out[186]
  PIN r0_rd_out[187]
    DIRECTION OUTPUT ;
    USE SIGNAL ;
    SHAPE ABUTMENT ;
    PORT
      LAYER M3 ;
      RECT 127.791 0.000 127.809 0.054 ;
    END
  END r0_rd_out[187]
  PIN r0_rd_out[188]
    DIRECTION OUTPUT ;
    USE SIGNAL ;
    SHAPE ABUTMENT ;
    PORT
      LAYER M3 ;
      RECT 128.079 0.000 128.097 0.054 ;
    END
  END r0_rd_out[188]
  PIN r0_rd_out[189]
    DIRECTION OUTPUT ;
    USE SIGNAL ;
    SHAPE ABUTMENT ;
    PORT
      LAYER M3 ;
      RECT 128.367 0.000 128.385 0.054 ;
    END
  END r0_rd_out[189]
  PIN r0_rd_out[190]
    DIRECTION OUTPUT ;
    USE SIGNAL ;
    SHAPE ABUTMENT ;
    PORT
      LAYER M3 ;
      RECT 128.655 0.000 128.673 0.054 ;
    END
  END r0_rd_out[190]
  PIN r0_rd_out[191]
    DIRECTION OUTPUT ;
    USE SIGNAL ;
    SHAPE ABUTMENT ;
    PORT
      LAYER M3 ;
      RECT 128.943 0.000 128.961 0.054 ;
    END
  END r0_rd_out[191]
  PIN r0_rd_out[192]
    DIRECTION OUTPUT ;
    USE SIGNAL ;
    SHAPE ABUTMENT ;
    PORT
      LAYER M3 ;
      RECT 129.231 0.000 129.249 0.054 ;
    END
  END r0_rd_out[192]
  PIN r0_rd_out[193]
    DIRECTION OUTPUT ;
    USE SIGNAL ;
    SHAPE ABUTMENT ;
    PORT
      LAYER M3 ;
      RECT 129.519 0.000 129.537 0.054 ;
    END
  END r0_rd_out[193]
  PIN r0_rd_out[194]
    DIRECTION OUTPUT ;
    USE SIGNAL ;
    SHAPE ABUTMENT ;
    PORT
      LAYER M3 ;
      RECT 129.807 0.000 129.825 0.054 ;
    END
  END r0_rd_out[194]
  PIN r0_rd_out[195]
    DIRECTION OUTPUT ;
    USE SIGNAL ;
    SHAPE ABUTMENT ;
    PORT
      LAYER M3 ;
      RECT 130.095 0.000 130.113 0.054 ;
    END
  END r0_rd_out[195]
  PIN r0_rd_out[196]
    DIRECTION OUTPUT ;
    USE SIGNAL ;
    SHAPE ABUTMENT ;
    PORT
      LAYER M3 ;
      RECT 130.383 0.000 130.401 0.054 ;
    END
  END r0_rd_out[196]
  PIN r0_rd_out[197]
    DIRECTION OUTPUT ;
    USE SIGNAL ;
    SHAPE ABUTMENT ;
    PORT
      LAYER M3 ;
      RECT 130.671 0.000 130.689 0.054 ;
    END
  END r0_rd_out[197]
  PIN r0_rd_out[198]
    DIRECTION OUTPUT ;
    USE SIGNAL ;
    SHAPE ABUTMENT ;
    PORT
      LAYER M3 ;
      RECT 130.959 0.000 130.977 0.054 ;
    END
  END r0_rd_out[198]
  PIN r0_rd_out[199]
    DIRECTION OUTPUT ;
    USE SIGNAL ;
    SHAPE ABUTMENT ;
    PORT
      LAYER M3 ;
      RECT 131.247 0.000 131.265 0.054 ;
    END
  END r0_rd_out[199]
  PIN r0_rd_out[200]
    DIRECTION OUTPUT ;
    USE SIGNAL ;
    SHAPE ABUTMENT ;
    PORT
      LAYER M3 ;
      RECT 131.535 0.000 131.553 0.054 ;
    END
  END r0_rd_out[200]
  PIN r0_rd_out[201]
    DIRECTION OUTPUT ;
    USE SIGNAL ;
    SHAPE ABUTMENT ;
    PORT
      LAYER M3 ;
      RECT 131.823 0.000 131.841 0.054 ;
    END
  END r0_rd_out[201]
  PIN r0_rd_out[202]
    DIRECTION OUTPUT ;
    USE SIGNAL ;
    SHAPE ABUTMENT ;
    PORT
      LAYER M3 ;
      RECT 132.111 0.000 132.129 0.054 ;
    END
  END r0_rd_out[202]
  PIN r0_rd_out[203]
    DIRECTION OUTPUT ;
    USE SIGNAL ;
    SHAPE ABUTMENT ;
    PORT
      LAYER M3 ;
      RECT 132.399 0.000 132.417 0.054 ;
    END
  END r0_rd_out[203]
  PIN r0_rd_out[204]
    DIRECTION OUTPUT ;
    USE SIGNAL ;
    SHAPE ABUTMENT ;
    PORT
      LAYER M3 ;
      RECT 132.687 0.000 132.705 0.054 ;
    END
  END r0_rd_out[204]
  PIN r0_rd_out[205]
    DIRECTION OUTPUT ;
    USE SIGNAL ;
    SHAPE ABUTMENT ;
    PORT
      LAYER M3 ;
      RECT 132.975 0.000 132.993 0.054 ;
    END
  END r0_rd_out[205]
  PIN r0_rd_out[206]
    DIRECTION OUTPUT ;
    USE SIGNAL ;
    SHAPE ABUTMENT ;
    PORT
      LAYER M3 ;
      RECT 133.263 0.000 133.281 0.054 ;
    END
  END r0_rd_out[206]
  PIN r0_rd_out[207]
    DIRECTION OUTPUT ;
    USE SIGNAL ;
    SHAPE ABUTMENT ;
    PORT
      LAYER M3 ;
      RECT 133.551 0.000 133.569 0.054 ;
    END
  END r0_rd_out[207]
  PIN r0_rd_out[208]
    DIRECTION OUTPUT ;
    USE SIGNAL ;
    SHAPE ABUTMENT ;
    PORT
      LAYER M3 ;
      RECT 133.839 0.000 133.857 0.054 ;
    END
  END r0_rd_out[208]
  PIN r0_rd_out[209]
    DIRECTION OUTPUT ;
    USE SIGNAL ;
    SHAPE ABUTMENT ;
    PORT
      LAYER M3 ;
      RECT 134.127 0.000 134.145 0.054 ;
    END
  END r0_rd_out[209]
  PIN r0_rd_out[210]
    DIRECTION OUTPUT ;
    USE SIGNAL ;
    SHAPE ABUTMENT ;
    PORT
      LAYER M3 ;
      RECT 134.415 0.000 134.433 0.054 ;
    END
  END r0_rd_out[210]
  PIN r0_rd_out[211]
    DIRECTION OUTPUT ;
    USE SIGNAL ;
    SHAPE ABUTMENT ;
    PORT
      LAYER M3 ;
      RECT 134.703 0.000 134.721 0.054 ;
    END
  END r0_rd_out[211]
  PIN r0_rd_out[212]
    DIRECTION OUTPUT ;
    USE SIGNAL ;
    SHAPE ABUTMENT ;
    PORT
      LAYER M3 ;
      RECT 134.991 0.000 135.009 0.054 ;
    END
  END r0_rd_out[212]
  PIN r0_rd_out[213]
    DIRECTION OUTPUT ;
    USE SIGNAL ;
    SHAPE ABUTMENT ;
    PORT
      LAYER M3 ;
      RECT 135.279 0.000 135.297 0.054 ;
    END
  END r0_rd_out[213]
  PIN r0_rd_out[214]
    DIRECTION OUTPUT ;
    USE SIGNAL ;
    SHAPE ABUTMENT ;
    PORT
      LAYER M3 ;
      RECT 135.567 0.000 135.585 0.054 ;
    END
  END r0_rd_out[214]
  PIN r0_rd_out[215]
    DIRECTION OUTPUT ;
    USE SIGNAL ;
    SHAPE ABUTMENT ;
    PORT
      LAYER M3 ;
      RECT 135.855 0.000 135.873 0.054 ;
    END
  END r0_rd_out[215]
  PIN r0_rd_out[216]
    DIRECTION OUTPUT ;
    USE SIGNAL ;
    SHAPE ABUTMENT ;
    PORT
      LAYER M3 ;
      RECT 136.143 0.000 136.161 0.054 ;
    END
  END r0_rd_out[216]
  PIN r0_rd_out[217]
    DIRECTION OUTPUT ;
    USE SIGNAL ;
    SHAPE ABUTMENT ;
    PORT
      LAYER M3 ;
      RECT 136.431 0.000 136.449 0.054 ;
    END
  END r0_rd_out[217]
  PIN r0_rd_out[218]
    DIRECTION OUTPUT ;
    USE SIGNAL ;
    SHAPE ABUTMENT ;
    PORT
      LAYER M3 ;
      RECT 136.719 0.000 136.737 0.054 ;
    END
  END r0_rd_out[218]
  PIN r0_rd_out[219]
    DIRECTION OUTPUT ;
    USE SIGNAL ;
    SHAPE ABUTMENT ;
    PORT
      LAYER M3 ;
      RECT 137.007 0.000 137.025 0.054 ;
    END
  END r0_rd_out[219]
  PIN r0_rd_out[220]
    DIRECTION OUTPUT ;
    USE SIGNAL ;
    SHAPE ABUTMENT ;
    PORT
      LAYER M3 ;
      RECT 137.295 0.000 137.313 0.054 ;
    END
  END r0_rd_out[220]
  PIN r0_rd_out[221]
    DIRECTION OUTPUT ;
    USE SIGNAL ;
    SHAPE ABUTMENT ;
    PORT
      LAYER M3 ;
      RECT 137.583 0.000 137.601 0.054 ;
    END
  END r0_rd_out[221]
  PIN r0_rd_out[222]
    DIRECTION OUTPUT ;
    USE SIGNAL ;
    SHAPE ABUTMENT ;
    PORT
      LAYER M3 ;
      RECT 137.871 0.000 137.889 0.054 ;
    END
  END r0_rd_out[222]
  PIN r0_rd_out[223]
    DIRECTION OUTPUT ;
    USE SIGNAL ;
    SHAPE ABUTMENT ;
    PORT
      LAYER M3 ;
      RECT 138.159 0.000 138.177 0.054 ;
    END
  END r0_rd_out[223]
  PIN r0_rd_out[224]
    DIRECTION OUTPUT ;
    USE SIGNAL ;
    SHAPE ABUTMENT ;
    PORT
      LAYER M3 ;
      RECT 138.447 0.000 138.465 0.054 ;
    END
  END r0_rd_out[224]
  PIN r0_rd_out[225]
    DIRECTION OUTPUT ;
    USE SIGNAL ;
    SHAPE ABUTMENT ;
    PORT
      LAYER M3 ;
      RECT 138.735 0.000 138.753 0.054 ;
    END
  END r0_rd_out[225]
  PIN r0_rd_out[226]
    DIRECTION OUTPUT ;
    USE SIGNAL ;
    SHAPE ABUTMENT ;
    PORT
      LAYER M3 ;
      RECT 139.023 0.000 139.041 0.054 ;
    END
  END r0_rd_out[226]
  PIN r0_rd_out[227]
    DIRECTION OUTPUT ;
    USE SIGNAL ;
    SHAPE ABUTMENT ;
    PORT
      LAYER M3 ;
      RECT 139.311 0.000 139.329 0.054 ;
    END
  END r0_rd_out[227]
  PIN r0_rd_out[228]
    DIRECTION OUTPUT ;
    USE SIGNAL ;
    SHAPE ABUTMENT ;
    PORT
      LAYER M3 ;
      RECT 139.599 0.000 139.617 0.054 ;
    END
  END r0_rd_out[228]
  PIN r0_rd_out[229]
    DIRECTION OUTPUT ;
    USE SIGNAL ;
    SHAPE ABUTMENT ;
    PORT
      LAYER M3 ;
      RECT 139.887 0.000 139.905 0.054 ;
    END
  END r0_rd_out[229]
  PIN r0_rd_out[230]
    DIRECTION OUTPUT ;
    USE SIGNAL ;
    SHAPE ABUTMENT ;
    PORT
      LAYER M3 ;
      RECT 140.175 0.000 140.193 0.054 ;
    END
  END r0_rd_out[230]
  PIN r0_rd_out[231]
    DIRECTION OUTPUT ;
    USE SIGNAL ;
    SHAPE ABUTMENT ;
    PORT
      LAYER M3 ;
      RECT 140.463 0.000 140.481 0.054 ;
    END
  END r0_rd_out[231]
  PIN r0_rd_out[232]
    DIRECTION OUTPUT ;
    USE SIGNAL ;
    SHAPE ABUTMENT ;
    PORT
      LAYER M3 ;
      RECT 140.751 0.000 140.769 0.054 ;
    END
  END r0_rd_out[232]
  PIN r0_rd_out[233]
    DIRECTION OUTPUT ;
    USE SIGNAL ;
    SHAPE ABUTMENT ;
    PORT
      LAYER M3 ;
      RECT 141.039 0.000 141.057 0.054 ;
    END
  END r0_rd_out[233]
  PIN r0_rd_out[234]
    DIRECTION OUTPUT ;
    USE SIGNAL ;
    SHAPE ABUTMENT ;
    PORT
      LAYER M3 ;
      RECT 141.327 0.000 141.345 0.054 ;
    END
  END r0_rd_out[234]
  PIN r0_rd_out[235]
    DIRECTION OUTPUT ;
    USE SIGNAL ;
    SHAPE ABUTMENT ;
    PORT
      LAYER M3 ;
      RECT 141.615 0.000 141.633 0.054 ;
    END
  END r0_rd_out[235]
  PIN r0_rd_out[236]
    DIRECTION OUTPUT ;
    USE SIGNAL ;
    SHAPE ABUTMENT ;
    PORT
      LAYER M3 ;
      RECT 141.903 0.000 141.921 0.054 ;
    END
  END r0_rd_out[236]
  PIN r0_rd_out[237]
    DIRECTION OUTPUT ;
    USE SIGNAL ;
    SHAPE ABUTMENT ;
    PORT
      LAYER M3 ;
      RECT 142.191 0.000 142.209 0.054 ;
    END
  END r0_rd_out[237]
  PIN r0_rd_out[238]
    DIRECTION OUTPUT ;
    USE SIGNAL ;
    SHAPE ABUTMENT ;
    PORT
      LAYER M3 ;
      RECT 142.479 0.000 142.497 0.054 ;
    END
  END r0_rd_out[238]
  PIN r0_rd_out[239]
    DIRECTION OUTPUT ;
    USE SIGNAL ;
    SHAPE ABUTMENT ;
    PORT
      LAYER M3 ;
      RECT 142.767 0.000 142.785 0.054 ;
    END
  END r0_rd_out[239]
  PIN r0_rd_out[240]
    DIRECTION OUTPUT ;
    USE SIGNAL ;
    SHAPE ABUTMENT ;
    PORT
      LAYER M3 ;
      RECT 143.055 0.000 143.073 0.054 ;
    END
  END r0_rd_out[240]
  PIN r0_rd_out[241]
    DIRECTION OUTPUT ;
    USE SIGNAL ;
    SHAPE ABUTMENT ;
    PORT
      LAYER M3 ;
      RECT 143.343 0.000 143.361 0.054 ;
    END
  END r0_rd_out[241]
  PIN r0_rd_out[242]
    DIRECTION OUTPUT ;
    USE SIGNAL ;
    SHAPE ABUTMENT ;
    PORT
      LAYER M3 ;
      RECT 143.631 0.000 143.649 0.054 ;
    END
  END r0_rd_out[242]
  PIN r0_rd_out[243]
    DIRECTION OUTPUT ;
    USE SIGNAL ;
    SHAPE ABUTMENT ;
    PORT
      LAYER M3 ;
      RECT 143.919 0.000 143.937 0.054 ;
    END
  END r0_rd_out[243]
  PIN r0_rd_out[244]
    DIRECTION OUTPUT ;
    USE SIGNAL ;
    SHAPE ABUTMENT ;
    PORT
      LAYER M3 ;
      RECT 144.207 0.000 144.225 0.054 ;
    END
  END r0_rd_out[244]
  PIN r0_rd_out[245]
    DIRECTION OUTPUT ;
    USE SIGNAL ;
    SHAPE ABUTMENT ;
    PORT
      LAYER M3 ;
      RECT 144.495 0.000 144.513 0.054 ;
    END
  END r0_rd_out[245]
  PIN r0_rd_out[246]
    DIRECTION OUTPUT ;
    USE SIGNAL ;
    SHAPE ABUTMENT ;
    PORT
      LAYER M3 ;
      RECT 144.783 0.000 144.801 0.054 ;
    END
  END r0_rd_out[246]
  PIN r0_rd_out[247]
    DIRECTION OUTPUT ;
    USE SIGNAL ;
    SHAPE ABUTMENT ;
    PORT
      LAYER M3 ;
      RECT 145.071 0.000 145.089 0.054 ;
    END
  END r0_rd_out[247]
  PIN r0_rd_out[248]
    DIRECTION OUTPUT ;
    USE SIGNAL ;
    SHAPE ABUTMENT ;
    PORT
      LAYER M3 ;
      RECT 145.359 0.000 145.377 0.054 ;
    END
  END r0_rd_out[248]
  PIN r0_rd_out[249]
    DIRECTION OUTPUT ;
    USE SIGNAL ;
    SHAPE ABUTMENT ;
    PORT
      LAYER M3 ;
      RECT 145.647 0.000 145.665 0.054 ;
    END
  END r0_rd_out[249]
  PIN r0_rd_out[250]
    DIRECTION OUTPUT ;
    USE SIGNAL ;
    SHAPE ABUTMENT ;
    PORT
      LAYER M3 ;
      RECT 145.935 0.000 145.953 0.054 ;
    END
  END r0_rd_out[250]
  PIN r0_rd_out[251]
    DIRECTION OUTPUT ;
    USE SIGNAL ;
    SHAPE ABUTMENT ;
    PORT
      LAYER M3 ;
      RECT 146.223 0.000 146.241 0.054 ;
    END
  END r0_rd_out[251]
  PIN r0_rd_out[252]
    DIRECTION OUTPUT ;
    USE SIGNAL ;
    SHAPE ABUTMENT ;
    PORT
      LAYER M3 ;
      RECT 146.511 0.000 146.529 0.054 ;
    END
  END r0_rd_out[252]
  PIN r0_rd_out[253]
    DIRECTION OUTPUT ;
    USE SIGNAL ;
    SHAPE ABUTMENT ;
    PORT
      LAYER M3 ;
      RECT 146.799 0.000 146.817 0.054 ;
    END
  END r0_rd_out[253]
  PIN r0_rd_out[254]
    DIRECTION OUTPUT ;
    USE SIGNAL ;
    SHAPE ABUTMENT ;
    PORT
      LAYER M3 ;
      RECT 147.087 0.000 147.105 0.054 ;
    END
  END r0_rd_out[254]
  PIN r0_rd_out[255]
    DIRECTION OUTPUT ;
    USE SIGNAL ;
    SHAPE ABUTMENT ;
    PORT
      LAYER M3 ;
      RECT 147.375 0.000 147.393 0.054 ;
    END
  END r0_rd_out[255]
  PIN r0_rd_out[256]
    DIRECTION OUTPUT ;
    USE SIGNAL ;
    SHAPE ABUTMENT ;
    PORT
      LAYER M3 ;
      RECT 0.207 128.510 0.225 128.564 ;
    END
  END r0_rd_out[256]
  PIN r0_rd_out[257]
    DIRECTION OUTPUT ;
    USE SIGNAL ;
    SHAPE ABUTMENT ;
    PORT
      LAYER M3 ;
      RECT 0.783 128.510 0.801 128.564 ;
    END
  END r0_rd_out[257]
  PIN r0_rd_out[258]
    DIRECTION OUTPUT ;
    USE SIGNAL ;
    SHAPE ABUTMENT ;
    PORT
      LAYER M3 ;
      RECT 1.359 128.510 1.377 128.564 ;
    END
  END r0_rd_out[258]
  PIN r0_rd_out[259]
    DIRECTION OUTPUT ;
    USE SIGNAL ;
    SHAPE ABUTMENT ;
    PORT
      LAYER M3 ;
      RECT 1.935 128.510 1.953 128.564 ;
    END
  END r0_rd_out[259]
  PIN r0_rd_out[260]
    DIRECTION OUTPUT ;
    USE SIGNAL ;
    SHAPE ABUTMENT ;
    PORT
      LAYER M3 ;
      RECT 2.511 128.510 2.529 128.564 ;
    END
  END r0_rd_out[260]
  PIN r0_rd_out[261]
    DIRECTION OUTPUT ;
    USE SIGNAL ;
    SHAPE ABUTMENT ;
    PORT
      LAYER M3 ;
      RECT 3.087 128.510 3.105 128.564 ;
    END
  END r0_rd_out[261]
  PIN r0_rd_out[262]
    DIRECTION OUTPUT ;
    USE SIGNAL ;
    SHAPE ABUTMENT ;
    PORT
      LAYER M3 ;
      RECT 3.663 128.510 3.681 128.564 ;
    END
  END r0_rd_out[262]
  PIN r0_rd_out[263]
    DIRECTION OUTPUT ;
    USE SIGNAL ;
    SHAPE ABUTMENT ;
    PORT
      LAYER M3 ;
      RECT 4.239 128.510 4.257 128.564 ;
    END
  END r0_rd_out[263]
  PIN r0_rd_out[264]
    DIRECTION OUTPUT ;
    USE SIGNAL ;
    SHAPE ABUTMENT ;
    PORT
      LAYER M3 ;
      RECT 4.815 128.510 4.833 128.564 ;
    END
  END r0_rd_out[264]
  PIN r0_rd_out[265]
    DIRECTION OUTPUT ;
    USE SIGNAL ;
    SHAPE ABUTMENT ;
    PORT
      LAYER M3 ;
      RECT 5.391 128.510 5.409 128.564 ;
    END
  END r0_rd_out[265]
  PIN r0_rd_out[266]
    DIRECTION OUTPUT ;
    USE SIGNAL ;
    SHAPE ABUTMENT ;
    PORT
      LAYER M3 ;
      RECT 5.967 128.510 5.985 128.564 ;
    END
  END r0_rd_out[266]
  PIN r0_rd_out[267]
    DIRECTION OUTPUT ;
    USE SIGNAL ;
    SHAPE ABUTMENT ;
    PORT
      LAYER M3 ;
      RECT 6.543 128.510 6.561 128.564 ;
    END
  END r0_rd_out[267]
  PIN r0_rd_out[268]
    DIRECTION OUTPUT ;
    USE SIGNAL ;
    SHAPE ABUTMENT ;
    PORT
      LAYER M3 ;
      RECT 7.119 128.510 7.137 128.564 ;
    END
  END r0_rd_out[268]
  PIN r0_rd_out[269]
    DIRECTION OUTPUT ;
    USE SIGNAL ;
    SHAPE ABUTMENT ;
    PORT
      LAYER M3 ;
      RECT 7.695 128.510 7.713 128.564 ;
    END
  END r0_rd_out[269]
  PIN r0_rd_out[270]
    DIRECTION OUTPUT ;
    USE SIGNAL ;
    SHAPE ABUTMENT ;
    PORT
      LAYER M3 ;
      RECT 8.271 128.510 8.289 128.564 ;
    END
  END r0_rd_out[270]
  PIN r0_rd_out[271]
    DIRECTION OUTPUT ;
    USE SIGNAL ;
    SHAPE ABUTMENT ;
    PORT
      LAYER M3 ;
      RECT 8.847 128.510 8.865 128.564 ;
    END
  END r0_rd_out[271]
  PIN r0_rd_out[272]
    DIRECTION OUTPUT ;
    USE SIGNAL ;
    SHAPE ABUTMENT ;
    PORT
      LAYER M3 ;
      RECT 9.423 128.510 9.441 128.564 ;
    END
  END r0_rd_out[272]
  PIN r0_rd_out[273]
    DIRECTION OUTPUT ;
    USE SIGNAL ;
    SHAPE ABUTMENT ;
    PORT
      LAYER M3 ;
      RECT 9.999 128.510 10.017 128.564 ;
    END
  END r0_rd_out[273]
  PIN r0_rd_out[274]
    DIRECTION OUTPUT ;
    USE SIGNAL ;
    SHAPE ABUTMENT ;
    PORT
      LAYER M3 ;
      RECT 10.575 128.510 10.593 128.564 ;
    END
  END r0_rd_out[274]
  PIN r0_rd_out[275]
    DIRECTION OUTPUT ;
    USE SIGNAL ;
    SHAPE ABUTMENT ;
    PORT
      LAYER M3 ;
      RECT 11.151 128.510 11.169 128.564 ;
    END
  END r0_rd_out[275]
  PIN r0_rd_out[276]
    DIRECTION OUTPUT ;
    USE SIGNAL ;
    SHAPE ABUTMENT ;
    PORT
      LAYER M3 ;
      RECT 11.727 128.510 11.745 128.564 ;
    END
  END r0_rd_out[276]
  PIN r0_rd_out[277]
    DIRECTION OUTPUT ;
    USE SIGNAL ;
    SHAPE ABUTMENT ;
    PORT
      LAYER M3 ;
      RECT 12.303 128.510 12.321 128.564 ;
    END
  END r0_rd_out[277]
  PIN r0_rd_out[278]
    DIRECTION OUTPUT ;
    USE SIGNAL ;
    SHAPE ABUTMENT ;
    PORT
      LAYER M3 ;
      RECT 12.879 128.510 12.897 128.564 ;
    END
  END r0_rd_out[278]
  PIN r0_rd_out[279]
    DIRECTION OUTPUT ;
    USE SIGNAL ;
    SHAPE ABUTMENT ;
    PORT
      LAYER M3 ;
      RECT 13.455 128.510 13.473 128.564 ;
    END
  END r0_rd_out[279]
  PIN r0_rd_out[280]
    DIRECTION OUTPUT ;
    USE SIGNAL ;
    SHAPE ABUTMENT ;
    PORT
      LAYER M3 ;
      RECT 14.031 128.510 14.049 128.564 ;
    END
  END r0_rd_out[280]
  PIN r0_rd_out[281]
    DIRECTION OUTPUT ;
    USE SIGNAL ;
    SHAPE ABUTMENT ;
    PORT
      LAYER M3 ;
      RECT 14.607 128.510 14.625 128.564 ;
    END
  END r0_rd_out[281]
  PIN r0_rd_out[282]
    DIRECTION OUTPUT ;
    USE SIGNAL ;
    SHAPE ABUTMENT ;
    PORT
      LAYER M3 ;
      RECT 15.183 128.510 15.201 128.564 ;
    END
  END r0_rd_out[282]
  PIN r0_rd_out[283]
    DIRECTION OUTPUT ;
    USE SIGNAL ;
    SHAPE ABUTMENT ;
    PORT
      LAYER M3 ;
      RECT 15.759 128.510 15.777 128.564 ;
    END
  END r0_rd_out[283]
  PIN r0_rd_out[284]
    DIRECTION OUTPUT ;
    USE SIGNAL ;
    SHAPE ABUTMENT ;
    PORT
      LAYER M3 ;
      RECT 16.335 128.510 16.353 128.564 ;
    END
  END r0_rd_out[284]
  PIN r0_rd_out[285]
    DIRECTION OUTPUT ;
    USE SIGNAL ;
    SHAPE ABUTMENT ;
    PORT
      LAYER M3 ;
      RECT 16.911 128.510 16.929 128.564 ;
    END
  END r0_rd_out[285]
  PIN r0_rd_out[286]
    DIRECTION OUTPUT ;
    USE SIGNAL ;
    SHAPE ABUTMENT ;
    PORT
      LAYER M3 ;
      RECT 17.487 128.510 17.505 128.564 ;
    END
  END r0_rd_out[286]
  PIN r0_rd_out[287]
    DIRECTION OUTPUT ;
    USE SIGNAL ;
    SHAPE ABUTMENT ;
    PORT
      LAYER M3 ;
      RECT 18.063 128.510 18.081 128.564 ;
    END
  END r0_rd_out[287]
  PIN r0_rd_out[288]
    DIRECTION OUTPUT ;
    USE SIGNAL ;
    SHAPE ABUTMENT ;
    PORT
      LAYER M3 ;
      RECT 18.639 128.510 18.657 128.564 ;
    END
  END r0_rd_out[288]
  PIN r0_rd_out[289]
    DIRECTION OUTPUT ;
    USE SIGNAL ;
    SHAPE ABUTMENT ;
    PORT
      LAYER M3 ;
      RECT 19.215 128.510 19.233 128.564 ;
    END
  END r0_rd_out[289]
  PIN r0_rd_out[290]
    DIRECTION OUTPUT ;
    USE SIGNAL ;
    SHAPE ABUTMENT ;
    PORT
      LAYER M3 ;
      RECT 19.791 128.510 19.809 128.564 ;
    END
  END r0_rd_out[290]
  PIN r0_rd_out[291]
    DIRECTION OUTPUT ;
    USE SIGNAL ;
    SHAPE ABUTMENT ;
    PORT
      LAYER M3 ;
      RECT 20.367 128.510 20.385 128.564 ;
    END
  END r0_rd_out[291]
  PIN r0_rd_out[292]
    DIRECTION OUTPUT ;
    USE SIGNAL ;
    SHAPE ABUTMENT ;
    PORT
      LAYER M3 ;
      RECT 20.943 128.510 20.961 128.564 ;
    END
  END r0_rd_out[292]
  PIN r0_rd_out[293]
    DIRECTION OUTPUT ;
    USE SIGNAL ;
    SHAPE ABUTMENT ;
    PORT
      LAYER M3 ;
      RECT 21.519 128.510 21.537 128.564 ;
    END
  END r0_rd_out[293]
  PIN r0_rd_out[294]
    DIRECTION OUTPUT ;
    USE SIGNAL ;
    SHAPE ABUTMENT ;
    PORT
      LAYER M3 ;
      RECT 22.095 128.510 22.113 128.564 ;
    END
  END r0_rd_out[294]
  PIN r0_rd_out[295]
    DIRECTION OUTPUT ;
    USE SIGNAL ;
    SHAPE ABUTMENT ;
    PORT
      LAYER M3 ;
      RECT 22.671 128.510 22.689 128.564 ;
    END
  END r0_rd_out[295]
  PIN r0_rd_out[296]
    DIRECTION OUTPUT ;
    USE SIGNAL ;
    SHAPE ABUTMENT ;
    PORT
      LAYER M3 ;
      RECT 23.247 128.510 23.265 128.564 ;
    END
  END r0_rd_out[296]
  PIN r0_rd_out[297]
    DIRECTION OUTPUT ;
    USE SIGNAL ;
    SHAPE ABUTMENT ;
    PORT
      LAYER M3 ;
      RECT 23.823 128.510 23.841 128.564 ;
    END
  END r0_rd_out[297]
  PIN r0_rd_out[298]
    DIRECTION OUTPUT ;
    USE SIGNAL ;
    SHAPE ABUTMENT ;
    PORT
      LAYER M3 ;
      RECT 24.399 128.510 24.417 128.564 ;
    END
  END r0_rd_out[298]
  PIN r0_rd_out[299]
    DIRECTION OUTPUT ;
    USE SIGNAL ;
    SHAPE ABUTMENT ;
    PORT
      LAYER M3 ;
      RECT 24.975 128.510 24.993 128.564 ;
    END
  END r0_rd_out[299]
  PIN r0_rd_out[300]
    DIRECTION OUTPUT ;
    USE SIGNAL ;
    SHAPE ABUTMENT ;
    PORT
      LAYER M3 ;
      RECT 25.551 128.510 25.569 128.564 ;
    END
  END r0_rd_out[300]
  PIN r0_rd_out[301]
    DIRECTION OUTPUT ;
    USE SIGNAL ;
    SHAPE ABUTMENT ;
    PORT
      LAYER M3 ;
      RECT 26.127 128.510 26.145 128.564 ;
    END
  END r0_rd_out[301]
  PIN r0_rd_out[302]
    DIRECTION OUTPUT ;
    USE SIGNAL ;
    SHAPE ABUTMENT ;
    PORT
      LAYER M3 ;
      RECT 26.703 128.510 26.721 128.564 ;
    END
  END r0_rd_out[302]
  PIN r0_rd_out[303]
    DIRECTION OUTPUT ;
    USE SIGNAL ;
    SHAPE ABUTMENT ;
    PORT
      LAYER M3 ;
      RECT 27.279 128.510 27.297 128.564 ;
    END
  END r0_rd_out[303]
  PIN r0_rd_out[304]
    DIRECTION OUTPUT ;
    USE SIGNAL ;
    SHAPE ABUTMENT ;
    PORT
      LAYER M3 ;
      RECT 27.855 128.510 27.873 128.564 ;
    END
  END r0_rd_out[304]
  PIN r0_rd_out[305]
    DIRECTION OUTPUT ;
    USE SIGNAL ;
    SHAPE ABUTMENT ;
    PORT
      LAYER M3 ;
      RECT 28.431 128.510 28.449 128.564 ;
    END
  END r0_rd_out[305]
  PIN r0_rd_out[306]
    DIRECTION OUTPUT ;
    USE SIGNAL ;
    SHAPE ABUTMENT ;
    PORT
      LAYER M3 ;
      RECT 29.007 128.510 29.025 128.564 ;
    END
  END r0_rd_out[306]
  PIN r0_rd_out[307]
    DIRECTION OUTPUT ;
    USE SIGNAL ;
    SHAPE ABUTMENT ;
    PORT
      LAYER M3 ;
      RECT 29.583 128.510 29.601 128.564 ;
    END
  END r0_rd_out[307]
  PIN r0_rd_out[308]
    DIRECTION OUTPUT ;
    USE SIGNAL ;
    SHAPE ABUTMENT ;
    PORT
      LAYER M3 ;
      RECT 30.159 128.510 30.177 128.564 ;
    END
  END r0_rd_out[308]
  PIN r0_rd_out[309]
    DIRECTION OUTPUT ;
    USE SIGNAL ;
    SHAPE ABUTMENT ;
    PORT
      LAYER M3 ;
      RECT 30.735 128.510 30.753 128.564 ;
    END
  END r0_rd_out[309]
  PIN r0_rd_out[310]
    DIRECTION OUTPUT ;
    USE SIGNAL ;
    SHAPE ABUTMENT ;
    PORT
      LAYER M3 ;
      RECT 31.311 128.510 31.329 128.564 ;
    END
  END r0_rd_out[310]
  PIN r0_rd_out[311]
    DIRECTION OUTPUT ;
    USE SIGNAL ;
    SHAPE ABUTMENT ;
    PORT
      LAYER M3 ;
      RECT 31.887 128.510 31.905 128.564 ;
    END
  END r0_rd_out[311]
  PIN r0_rd_out[312]
    DIRECTION OUTPUT ;
    USE SIGNAL ;
    SHAPE ABUTMENT ;
    PORT
      LAYER M3 ;
      RECT 32.463 128.510 32.481 128.564 ;
    END
  END r0_rd_out[312]
  PIN r0_rd_out[313]
    DIRECTION OUTPUT ;
    USE SIGNAL ;
    SHAPE ABUTMENT ;
    PORT
      LAYER M3 ;
      RECT 33.039 128.510 33.057 128.564 ;
    END
  END r0_rd_out[313]
  PIN r0_rd_out[314]
    DIRECTION OUTPUT ;
    USE SIGNAL ;
    SHAPE ABUTMENT ;
    PORT
      LAYER M3 ;
      RECT 33.615 128.510 33.633 128.564 ;
    END
  END r0_rd_out[314]
  PIN r0_rd_out[315]
    DIRECTION OUTPUT ;
    USE SIGNAL ;
    SHAPE ABUTMENT ;
    PORT
      LAYER M3 ;
      RECT 34.191 128.510 34.209 128.564 ;
    END
  END r0_rd_out[315]
  PIN r0_rd_out[316]
    DIRECTION OUTPUT ;
    USE SIGNAL ;
    SHAPE ABUTMENT ;
    PORT
      LAYER M3 ;
      RECT 34.767 128.510 34.785 128.564 ;
    END
  END r0_rd_out[316]
  PIN r0_rd_out[317]
    DIRECTION OUTPUT ;
    USE SIGNAL ;
    SHAPE ABUTMENT ;
    PORT
      LAYER M3 ;
      RECT 35.343 128.510 35.361 128.564 ;
    END
  END r0_rd_out[317]
  PIN r0_rd_out[318]
    DIRECTION OUTPUT ;
    USE SIGNAL ;
    SHAPE ABUTMENT ;
    PORT
      LAYER M3 ;
      RECT 35.919 128.510 35.937 128.564 ;
    END
  END r0_rd_out[318]
  PIN r0_rd_out[319]
    DIRECTION OUTPUT ;
    USE SIGNAL ;
    SHAPE ABUTMENT ;
    PORT
      LAYER M3 ;
      RECT 36.495 128.510 36.513 128.564 ;
    END
  END r0_rd_out[319]
  PIN r0_rd_out[320]
    DIRECTION OUTPUT ;
    USE SIGNAL ;
    SHAPE ABUTMENT ;
    PORT
      LAYER M3 ;
      RECT 37.071 128.510 37.089 128.564 ;
    END
  END r0_rd_out[320]
  PIN r0_rd_out[321]
    DIRECTION OUTPUT ;
    USE SIGNAL ;
    SHAPE ABUTMENT ;
    PORT
      LAYER M3 ;
      RECT 37.647 128.510 37.665 128.564 ;
    END
  END r0_rd_out[321]
  PIN r0_rd_out[322]
    DIRECTION OUTPUT ;
    USE SIGNAL ;
    SHAPE ABUTMENT ;
    PORT
      LAYER M3 ;
      RECT 38.223 128.510 38.241 128.564 ;
    END
  END r0_rd_out[322]
  PIN r0_rd_out[323]
    DIRECTION OUTPUT ;
    USE SIGNAL ;
    SHAPE ABUTMENT ;
    PORT
      LAYER M3 ;
      RECT 38.799 128.510 38.817 128.564 ;
    END
  END r0_rd_out[323]
  PIN r0_rd_out[324]
    DIRECTION OUTPUT ;
    USE SIGNAL ;
    SHAPE ABUTMENT ;
    PORT
      LAYER M3 ;
      RECT 39.375 128.510 39.393 128.564 ;
    END
  END r0_rd_out[324]
  PIN r0_rd_out[325]
    DIRECTION OUTPUT ;
    USE SIGNAL ;
    SHAPE ABUTMENT ;
    PORT
      LAYER M3 ;
      RECT 39.951 128.510 39.969 128.564 ;
    END
  END r0_rd_out[325]
  PIN r0_rd_out[326]
    DIRECTION OUTPUT ;
    USE SIGNAL ;
    SHAPE ABUTMENT ;
    PORT
      LAYER M3 ;
      RECT 40.527 128.510 40.545 128.564 ;
    END
  END r0_rd_out[326]
  PIN r0_rd_out[327]
    DIRECTION OUTPUT ;
    USE SIGNAL ;
    SHAPE ABUTMENT ;
    PORT
      LAYER M3 ;
      RECT 41.103 128.510 41.121 128.564 ;
    END
  END r0_rd_out[327]
  PIN r0_rd_out[328]
    DIRECTION OUTPUT ;
    USE SIGNAL ;
    SHAPE ABUTMENT ;
    PORT
      LAYER M3 ;
      RECT 41.679 128.510 41.697 128.564 ;
    END
  END r0_rd_out[328]
  PIN r0_rd_out[329]
    DIRECTION OUTPUT ;
    USE SIGNAL ;
    SHAPE ABUTMENT ;
    PORT
      LAYER M3 ;
      RECT 42.255 128.510 42.273 128.564 ;
    END
  END r0_rd_out[329]
  PIN r0_rd_out[330]
    DIRECTION OUTPUT ;
    USE SIGNAL ;
    SHAPE ABUTMENT ;
    PORT
      LAYER M3 ;
      RECT 42.831 128.510 42.849 128.564 ;
    END
  END r0_rd_out[330]
  PIN r0_rd_out[331]
    DIRECTION OUTPUT ;
    USE SIGNAL ;
    SHAPE ABUTMENT ;
    PORT
      LAYER M3 ;
      RECT 43.407 128.510 43.425 128.564 ;
    END
  END r0_rd_out[331]
  PIN r0_rd_out[332]
    DIRECTION OUTPUT ;
    USE SIGNAL ;
    SHAPE ABUTMENT ;
    PORT
      LAYER M3 ;
      RECT 43.983 128.510 44.001 128.564 ;
    END
  END r0_rd_out[332]
  PIN r0_rd_out[333]
    DIRECTION OUTPUT ;
    USE SIGNAL ;
    SHAPE ABUTMENT ;
    PORT
      LAYER M3 ;
      RECT 44.559 128.510 44.577 128.564 ;
    END
  END r0_rd_out[333]
  PIN r0_rd_out[334]
    DIRECTION OUTPUT ;
    USE SIGNAL ;
    SHAPE ABUTMENT ;
    PORT
      LAYER M3 ;
      RECT 45.135 128.510 45.153 128.564 ;
    END
  END r0_rd_out[334]
  PIN r0_rd_out[335]
    DIRECTION OUTPUT ;
    USE SIGNAL ;
    SHAPE ABUTMENT ;
    PORT
      LAYER M3 ;
      RECT 45.711 128.510 45.729 128.564 ;
    END
  END r0_rd_out[335]
  PIN r0_rd_out[336]
    DIRECTION OUTPUT ;
    USE SIGNAL ;
    SHAPE ABUTMENT ;
    PORT
      LAYER M3 ;
      RECT 46.287 128.510 46.305 128.564 ;
    END
  END r0_rd_out[336]
  PIN r0_rd_out[337]
    DIRECTION OUTPUT ;
    USE SIGNAL ;
    SHAPE ABUTMENT ;
    PORT
      LAYER M3 ;
      RECT 46.863 128.510 46.881 128.564 ;
    END
  END r0_rd_out[337]
  PIN r0_rd_out[338]
    DIRECTION OUTPUT ;
    USE SIGNAL ;
    SHAPE ABUTMENT ;
    PORT
      LAYER M3 ;
      RECT 47.439 128.510 47.457 128.564 ;
    END
  END r0_rd_out[338]
  PIN r0_rd_out[339]
    DIRECTION OUTPUT ;
    USE SIGNAL ;
    SHAPE ABUTMENT ;
    PORT
      LAYER M3 ;
      RECT 48.015 128.510 48.033 128.564 ;
    END
  END r0_rd_out[339]
  PIN r0_rd_out[340]
    DIRECTION OUTPUT ;
    USE SIGNAL ;
    SHAPE ABUTMENT ;
    PORT
      LAYER M3 ;
      RECT 48.591 128.510 48.609 128.564 ;
    END
  END r0_rd_out[340]
  PIN r0_rd_out[341]
    DIRECTION OUTPUT ;
    USE SIGNAL ;
    SHAPE ABUTMENT ;
    PORT
      LAYER M3 ;
      RECT 49.167 128.510 49.185 128.564 ;
    END
  END r0_rd_out[341]
  PIN r0_rd_out[342]
    DIRECTION OUTPUT ;
    USE SIGNAL ;
    SHAPE ABUTMENT ;
    PORT
      LAYER M3 ;
      RECT 49.743 128.510 49.761 128.564 ;
    END
  END r0_rd_out[342]
  PIN r0_rd_out[343]
    DIRECTION OUTPUT ;
    USE SIGNAL ;
    SHAPE ABUTMENT ;
    PORT
      LAYER M3 ;
      RECT 50.319 128.510 50.337 128.564 ;
    END
  END r0_rd_out[343]
  PIN r0_rd_out[344]
    DIRECTION OUTPUT ;
    USE SIGNAL ;
    SHAPE ABUTMENT ;
    PORT
      LAYER M3 ;
      RECT 50.895 128.510 50.913 128.564 ;
    END
  END r0_rd_out[344]
  PIN r0_rd_out[345]
    DIRECTION OUTPUT ;
    USE SIGNAL ;
    SHAPE ABUTMENT ;
    PORT
      LAYER M3 ;
      RECT 51.471 128.510 51.489 128.564 ;
    END
  END r0_rd_out[345]
  PIN r0_rd_out[346]
    DIRECTION OUTPUT ;
    USE SIGNAL ;
    SHAPE ABUTMENT ;
    PORT
      LAYER M3 ;
      RECT 52.047 128.510 52.065 128.564 ;
    END
  END r0_rd_out[346]
  PIN r0_rd_out[347]
    DIRECTION OUTPUT ;
    USE SIGNAL ;
    SHAPE ABUTMENT ;
    PORT
      LAYER M3 ;
      RECT 52.623 128.510 52.641 128.564 ;
    END
  END r0_rd_out[347]
  PIN r0_rd_out[348]
    DIRECTION OUTPUT ;
    USE SIGNAL ;
    SHAPE ABUTMENT ;
    PORT
      LAYER M3 ;
      RECT 53.199 128.510 53.217 128.564 ;
    END
  END r0_rd_out[348]
  PIN r0_rd_out[349]
    DIRECTION OUTPUT ;
    USE SIGNAL ;
    SHAPE ABUTMENT ;
    PORT
      LAYER M3 ;
      RECT 53.775 128.510 53.793 128.564 ;
    END
  END r0_rd_out[349]
  PIN r0_rd_out[350]
    DIRECTION OUTPUT ;
    USE SIGNAL ;
    SHAPE ABUTMENT ;
    PORT
      LAYER M3 ;
      RECT 54.351 128.510 54.369 128.564 ;
    END
  END r0_rd_out[350]
  PIN r0_rd_out[351]
    DIRECTION OUTPUT ;
    USE SIGNAL ;
    SHAPE ABUTMENT ;
    PORT
      LAYER M3 ;
      RECT 54.927 128.510 54.945 128.564 ;
    END
  END r0_rd_out[351]
  PIN r0_rd_out[352]
    DIRECTION OUTPUT ;
    USE SIGNAL ;
    SHAPE ABUTMENT ;
    PORT
      LAYER M3 ;
      RECT 55.503 128.510 55.521 128.564 ;
    END
  END r0_rd_out[352]
  PIN r0_rd_out[353]
    DIRECTION OUTPUT ;
    USE SIGNAL ;
    SHAPE ABUTMENT ;
    PORT
      LAYER M3 ;
      RECT 56.079 128.510 56.097 128.564 ;
    END
  END r0_rd_out[353]
  PIN r0_rd_out[354]
    DIRECTION OUTPUT ;
    USE SIGNAL ;
    SHAPE ABUTMENT ;
    PORT
      LAYER M3 ;
      RECT 56.655 128.510 56.673 128.564 ;
    END
  END r0_rd_out[354]
  PIN r0_rd_out[355]
    DIRECTION OUTPUT ;
    USE SIGNAL ;
    SHAPE ABUTMENT ;
    PORT
      LAYER M3 ;
      RECT 57.231 128.510 57.249 128.564 ;
    END
  END r0_rd_out[355]
  PIN r0_rd_out[356]
    DIRECTION OUTPUT ;
    USE SIGNAL ;
    SHAPE ABUTMENT ;
    PORT
      LAYER M3 ;
      RECT 57.807 128.510 57.825 128.564 ;
    END
  END r0_rd_out[356]
  PIN r0_rd_out[357]
    DIRECTION OUTPUT ;
    USE SIGNAL ;
    SHAPE ABUTMENT ;
    PORT
      LAYER M3 ;
      RECT 58.383 128.510 58.401 128.564 ;
    END
  END r0_rd_out[357]
  PIN r0_rd_out[358]
    DIRECTION OUTPUT ;
    USE SIGNAL ;
    SHAPE ABUTMENT ;
    PORT
      LAYER M3 ;
      RECT 58.959 128.510 58.977 128.564 ;
    END
  END r0_rd_out[358]
  PIN r0_rd_out[359]
    DIRECTION OUTPUT ;
    USE SIGNAL ;
    SHAPE ABUTMENT ;
    PORT
      LAYER M3 ;
      RECT 59.535 128.510 59.553 128.564 ;
    END
  END r0_rd_out[359]
  PIN r0_rd_out[360]
    DIRECTION OUTPUT ;
    USE SIGNAL ;
    SHAPE ABUTMENT ;
    PORT
      LAYER M3 ;
      RECT 60.111 128.510 60.129 128.564 ;
    END
  END r0_rd_out[360]
  PIN r0_rd_out[361]
    DIRECTION OUTPUT ;
    USE SIGNAL ;
    SHAPE ABUTMENT ;
    PORT
      LAYER M3 ;
      RECT 60.687 128.510 60.705 128.564 ;
    END
  END r0_rd_out[361]
  PIN r0_rd_out[362]
    DIRECTION OUTPUT ;
    USE SIGNAL ;
    SHAPE ABUTMENT ;
    PORT
      LAYER M3 ;
      RECT 61.263 128.510 61.281 128.564 ;
    END
  END r0_rd_out[362]
  PIN r0_rd_out[363]
    DIRECTION OUTPUT ;
    USE SIGNAL ;
    SHAPE ABUTMENT ;
    PORT
      LAYER M3 ;
      RECT 61.839 128.510 61.857 128.564 ;
    END
  END r0_rd_out[363]
  PIN r0_rd_out[364]
    DIRECTION OUTPUT ;
    USE SIGNAL ;
    SHAPE ABUTMENT ;
    PORT
      LAYER M3 ;
      RECT 62.415 128.510 62.433 128.564 ;
    END
  END r0_rd_out[364]
  PIN r0_rd_out[365]
    DIRECTION OUTPUT ;
    USE SIGNAL ;
    SHAPE ABUTMENT ;
    PORT
      LAYER M3 ;
      RECT 62.991 128.510 63.009 128.564 ;
    END
  END r0_rd_out[365]
  PIN r0_rd_out[366]
    DIRECTION OUTPUT ;
    USE SIGNAL ;
    SHAPE ABUTMENT ;
    PORT
      LAYER M3 ;
      RECT 63.567 128.510 63.585 128.564 ;
    END
  END r0_rd_out[366]
  PIN r0_rd_out[367]
    DIRECTION OUTPUT ;
    USE SIGNAL ;
    SHAPE ABUTMENT ;
    PORT
      LAYER M3 ;
      RECT 64.143 128.510 64.161 128.564 ;
    END
  END r0_rd_out[367]
  PIN r0_rd_out[368]
    DIRECTION OUTPUT ;
    USE SIGNAL ;
    SHAPE ABUTMENT ;
    PORT
      LAYER M3 ;
      RECT 64.719 128.510 64.737 128.564 ;
    END
  END r0_rd_out[368]
  PIN r0_rd_out[369]
    DIRECTION OUTPUT ;
    USE SIGNAL ;
    SHAPE ABUTMENT ;
    PORT
      LAYER M3 ;
      RECT 65.295 128.510 65.313 128.564 ;
    END
  END r0_rd_out[369]
  PIN r0_rd_out[370]
    DIRECTION OUTPUT ;
    USE SIGNAL ;
    SHAPE ABUTMENT ;
    PORT
      LAYER M3 ;
      RECT 65.871 128.510 65.889 128.564 ;
    END
  END r0_rd_out[370]
  PIN r0_rd_out[371]
    DIRECTION OUTPUT ;
    USE SIGNAL ;
    SHAPE ABUTMENT ;
    PORT
      LAYER M3 ;
      RECT 66.447 128.510 66.465 128.564 ;
    END
  END r0_rd_out[371]
  PIN r0_rd_out[372]
    DIRECTION OUTPUT ;
    USE SIGNAL ;
    SHAPE ABUTMENT ;
    PORT
      LAYER M3 ;
      RECT 67.023 128.510 67.041 128.564 ;
    END
  END r0_rd_out[372]
  PIN r0_rd_out[373]
    DIRECTION OUTPUT ;
    USE SIGNAL ;
    SHAPE ABUTMENT ;
    PORT
      LAYER M3 ;
      RECT 67.599 128.510 67.617 128.564 ;
    END
  END r0_rd_out[373]
  PIN r0_rd_out[374]
    DIRECTION OUTPUT ;
    USE SIGNAL ;
    SHAPE ABUTMENT ;
    PORT
      LAYER M3 ;
      RECT 68.175 128.510 68.193 128.564 ;
    END
  END r0_rd_out[374]
  PIN r0_rd_out[375]
    DIRECTION OUTPUT ;
    USE SIGNAL ;
    SHAPE ABUTMENT ;
    PORT
      LAYER M3 ;
      RECT 68.751 128.510 68.769 128.564 ;
    END
  END r0_rd_out[375]
  PIN r0_rd_out[376]
    DIRECTION OUTPUT ;
    USE SIGNAL ;
    SHAPE ABUTMENT ;
    PORT
      LAYER M3 ;
      RECT 69.327 128.510 69.345 128.564 ;
    END
  END r0_rd_out[376]
  PIN r0_rd_out[377]
    DIRECTION OUTPUT ;
    USE SIGNAL ;
    SHAPE ABUTMENT ;
    PORT
      LAYER M3 ;
      RECT 69.903 128.510 69.921 128.564 ;
    END
  END r0_rd_out[377]
  PIN r0_rd_out[378]
    DIRECTION OUTPUT ;
    USE SIGNAL ;
    SHAPE ABUTMENT ;
    PORT
      LAYER M3 ;
      RECT 70.479 128.510 70.497 128.564 ;
    END
  END r0_rd_out[378]
  PIN r0_rd_out[379]
    DIRECTION OUTPUT ;
    USE SIGNAL ;
    SHAPE ABUTMENT ;
    PORT
      LAYER M3 ;
      RECT 71.055 128.510 71.073 128.564 ;
    END
  END r0_rd_out[379]
  PIN r0_rd_out[380]
    DIRECTION OUTPUT ;
    USE SIGNAL ;
    SHAPE ABUTMENT ;
    PORT
      LAYER M3 ;
      RECT 71.631 128.510 71.649 128.564 ;
    END
  END r0_rd_out[380]
  PIN r0_rd_out[381]
    DIRECTION OUTPUT ;
    USE SIGNAL ;
    SHAPE ABUTMENT ;
    PORT
      LAYER M3 ;
      RECT 72.207 128.510 72.225 128.564 ;
    END
  END r0_rd_out[381]
  PIN r0_rd_out[382]
    DIRECTION OUTPUT ;
    USE SIGNAL ;
    SHAPE ABUTMENT ;
    PORT
      LAYER M3 ;
      RECT 72.783 128.510 72.801 128.564 ;
    END
  END r0_rd_out[382]
  PIN r0_rd_out[383]
    DIRECTION OUTPUT ;
    USE SIGNAL ;
    SHAPE ABUTMENT ;
    PORT
      LAYER M3 ;
      RECT 73.359 128.510 73.377 128.564 ;
    END
  END r0_rd_out[383]
  PIN r0_rd_out[384]
    DIRECTION OUTPUT ;
    USE SIGNAL ;
    SHAPE ABUTMENT ;
    PORT
      LAYER M3 ;
      RECT 73.935 128.510 73.953 128.564 ;
    END
  END r0_rd_out[384]
  PIN r0_rd_out[385]
    DIRECTION OUTPUT ;
    USE SIGNAL ;
    SHAPE ABUTMENT ;
    PORT
      LAYER M3 ;
      RECT 74.511 128.510 74.529 128.564 ;
    END
  END r0_rd_out[385]
  PIN r0_rd_out[386]
    DIRECTION OUTPUT ;
    USE SIGNAL ;
    SHAPE ABUTMENT ;
    PORT
      LAYER M3 ;
      RECT 75.087 128.510 75.105 128.564 ;
    END
  END r0_rd_out[386]
  PIN r0_rd_out[387]
    DIRECTION OUTPUT ;
    USE SIGNAL ;
    SHAPE ABUTMENT ;
    PORT
      LAYER M3 ;
      RECT 75.663 128.510 75.681 128.564 ;
    END
  END r0_rd_out[387]
  PIN r0_rd_out[388]
    DIRECTION OUTPUT ;
    USE SIGNAL ;
    SHAPE ABUTMENT ;
    PORT
      LAYER M3 ;
      RECT 76.239 128.510 76.257 128.564 ;
    END
  END r0_rd_out[388]
  PIN r0_rd_out[389]
    DIRECTION OUTPUT ;
    USE SIGNAL ;
    SHAPE ABUTMENT ;
    PORT
      LAYER M3 ;
      RECT 76.815 128.510 76.833 128.564 ;
    END
  END r0_rd_out[389]
  PIN r0_rd_out[390]
    DIRECTION OUTPUT ;
    USE SIGNAL ;
    SHAPE ABUTMENT ;
    PORT
      LAYER M3 ;
      RECT 77.391 128.510 77.409 128.564 ;
    END
  END r0_rd_out[390]
  PIN r0_rd_out[391]
    DIRECTION OUTPUT ;
    USE SIGNAL ;
    SHAPE ABUTMENT ;
    PORT
      LAYER M3 ;
      RECT 77.967 128.510 77.985 128.564 ;
    END
  END r0_rd_out[391]
  PIN r0_rd_out[392]
    DIRECTION OUTPUT ;
    USE SIGNAL ;
    SHAPE ABUTMENT ;
    PORT
      LAYER M3 ;
      RECT 78.543 128.510 78.561 128.564 ;
    END
  END r0_rd_out[392]
  PIN r0_rd_out[393]
    DIRECTION OUTPUT ;
    USE SIGNAL ;
    SHAPE ABUTMENT ;
    PORT
      LAYER M3 ;
      RECT 79.119 128.510 79.137 128.564 ;
    END
  END r0_rd_out[393]
  PIN r0_rd_out[394]
    DIRECTION OUTPUT ;
    USE SIGNAL ;
    SHAPE ABUTMENT ;
    PORT
      LAYER M3 ;
      RECT 79.695 128.510 79.713 128.564 ;
    END
  END r0_rd_out[394]
  PIN r0_rd_out[395]
    DIRECTION OUTPUT ;
    USE SIGNAL ;
    SHAPE ABUTMENT ;
    PORT
      LAYER M3 ;
      RECT 80.271 128.510 80.289 128.564 ;
    END
  END r0_rd_out[395]
  PIN r0_rd_out[396]
    DIRECTION OUTPUT ;
    USE SIGNAL ;
    SHAPE ABUTMENT ;
    PORT
      LAYER M3 ;
      RECT 80.847 128.510 80.865 128.564 ;
    END
  END r0_rd_out[396]
  PIN r0_rd_out[397]
    DIRECTION OUTPUT ;
    USE SIGNAL ;
    SHAPE ABUTMENT ;
    PORT
      LAYER M3 ;
      RECT 81.423 128.510 81.441 128.564 ;
    END
  END r0_rd_out[397]
  PIN r0_rd_out[398]
    DIRECTION OUTPUT ;
    USE SIGNAL ;
    SHAPE ABUTMENT ;
    PORT
      LAYER M3 ;
      RECT 81.999 128.510 82.017 128.564 ;
    END
  END r0_rd_out[398]
  PIN r0_rd_out[399]
    DIRECTION OUTPUT ;
    USE SIGNAL ;
    SHAPE ABUTMENT ;
    PORT
      LAYER M3 ;
      RECT 82.575 128.510 82.593 128.564 ;
    END
  END r0_rd_out[399]
  PIN r0_rd_out[400]
    DIRECTION OUTPUT ;
    USE SIGNAL ;
    SHAPE ABUTMENT ;
    PORT
      LAYER M3 ;
      RECT 83.151 128.510 83.169 128.564 ;
    END
  END r0_rd_out[400]
  PIN r0_rd_out[401]
    DIRECTION OUTPUT ;
    USE SIGNAL ;
    SHAPE ABUTMENT ;
    PORT
      LAYER M3 ;
      RECT 83.727 128.510 83.745 128.564 ;
    END
  END r0_rd_out[401]
  PIN r0_rd_out[402]
    DIRECTION OUTPUT ;
    USE SIGNAL ;
    SHAPE ABUTMENT ;
    PORT
      LAYER M3 ;
      RECT 84.303 128.510 84.321 128.564 ;
    END
  END r0_rd_out[402]
  PIN r0_rd_out[403]
    DIRECTION OUTPUT ;
    USE SIGNAL ;
    SHAPE ABUTMENT ;
    PORT
      LAYER M3 ;
      RECT 84.879 128.510 84.897 128.564 ;
    END
  END r0_rd_out[403]
  PIN r0_rd_out[404]
    DIRECTION OUTPUT ;
    USE SIGNAL ;
    SHAPE ABUTMENT ;
    PORT
      LAYER M3 ;
      RECT 85.455 128.510 85.473 128.564 ;
    END
  END r0_rd_out[404]
  PIN r0_rd_out[405]
    DIRECTION OUTPUT ;
    USE SIGNAL ;
    SHAPE ABUTMENT ;
    PORT
      LAYER M3 ;
      RECT 86.031 128.510 86.049 128.564 ;
    END
  END r0_rd_out[405]
  PIN r0_rd_out[406]
    DIRECTION OUTPUT ;
    USE SIGNAL ;
    SHAPE ABUTMENT ;
    PORT
      LAYER M3 ;
      RECT 86.607 128.510 86.625 128.564 ;
    END
  END r0_rd_out[406]
  PIN r0_rd_out[407]
    DIRECTION OUTPUT ;
    USE SIGNAL ;
    SHAPE ABUTMENT ;
    PORT
      LAYER M3 ;
      RECT 87.183 128.510 87.201 128.564 ;
    END
  END r0_rd_out[407]
  PIN r0_rd_out[408]
    DIRECTION OUTPUT ;
    USE SIGNAL ;
    SHAPE ABUTMENT ;
    PORT
      LAYER M3 ;
      RECT 87.759 128.510 87.777 128.564 ;
    END
  END r0_rd_out[408]
  PIN r0_rd_out[409]
    DIRECTION OUTPUT ;
    USE SIGNAL ;
    SHAPE ABUTMENT ;
    PORT
      LAYER M3 ;
      RECT 88.335 128.510 88.353 128.564 ;
    END
  END r0_rd_out[409]
  PIN r0_rd_out[410]
    DIRECTION OUTPUT ;
    USE SIGNAL ;
    SHAPE ABUTMENT ;
    PORT
      LAYER M3 ;
      RECT 88.911 128.510 88.929 128.564 ;
    END
  END r0_rd_out[410]
  PIN r0_rd_out[411]
    DIRECTION OUTPUT ;
    USE SIGNAL ;
    SHAPE ABUTMENT ;
    PORT
      LAYER M3 ;
      RECT 89.487 128.510 89.505 128.564 ;
    END
  END r0_rd_out[411]
  PIN r0_rd_out[412]
    DIRECTION OUTPUT ;
    USE SIGNAL ;
    SHAPE ABUTMENT ;
    PORT
      LAYER M3 ;
      RECT 90.063 128.510 90.081 128.564 ;
    END
  END r0_rd_out[412]
  PIN r0_rd_out[413]
    DIRECTION OUTPUT ;
    USE SIGNAL ;
    SHAPE ABUTMENT ;
    PORT
      LAYER M3 ;
      RECT 90.639 128.510 90.657 128.564 ;
    END
  END r0_rd_out[413]
  PIN r0_rd_out[414]
    DIRECTION OUTPUT ;
    USE SIGNAL ;
    SHAPE ABUTMENT ;
    PORT
      LAYER M3 ;
      RECT 91.215 128.510 91.233 128.564 ;
    END
  END r0_rd_out[414]
  PIN r0_rd_out[415]
    DIRECTION OUTPUT ;
    USE SIGNAL ;
    SHAPE ABUTMENT ;
    PORT
      LAYER M3 ;
      RECT 91.791 128.510 91.809 128.564 ;
    END
  END r0_rd_out[415]
  PIN r0_rd_out[416]
    DIRECTION OUTPUT ;
    USE SIGNAL ;
    SHAPE ABUTMENT ;
    PORT
      LAYER M3 ;
      RECT 92.367 128.510 92.385 128.564 ;
    END
  END r0_rd_out[416]
  PIN r0_rd_out[417]
    DIRECTION OUTPUT ;
    USE SIGNAL ;
    SHAPE ABUTMENT ;
    PORT
      LAYER M3 ;
      RECT 92.943 128.510 92.961 128.564 ;
    END
  END r0_rd_out[417]
  PIN r0_rd_out[418]
    DIRECTION OUTPUT ;
    USE SIGNAL ;
    SHAPE ABUTMENT ;
    PORT
      LAYER M3 ;
      RECT 93.519 128.510 93.537 128.564 ;
    END
  END r0_rd_out[418]
  PIN r0_rd_out[419]
    DIRECTION OUTPUT ;
    USE SIGNAL ;
    SHAPE ABUTMENT ;
    PORT
      LAYER M3 ;
      RECT 94.095 128.510 94.113 128.564 ;
    END
  END r0_rd_out[419]
  PIN r0_rd_out[420]
    DIRECTION OUTPUT ;
    USE SIGNAL ;
    SHAPE ABUTMENT ;
    PORT
      LAYER M3 ;
      RECT 94.671 128.510 94.689 128.564 ;
    END
  END r0_rd_out[420]
  PIN r0_rd_out[421]
    DIRECTION OUTPUT ;
    USE SIGNAL ;
    SHAPE ABUTMENT ;
    PORT
      LAYER M3 ;
      RECT 95.247 128.510 95.265 128.564 ;
    END
  END r0_rd_out[421]
  PIN r0_rd_out[422]
    DIRECTION OUTPUT ;
    USE SIGNAL ;
    SHAPE ABUTMENT ;
    PORT
      LAYER M3 ;
      RECT 95.823 128.510 95.841 128.564 ;
    END
  END r0_rd_out[422]
  PIN r0_rd_out[423]
    DIRECTION OUTPUT ;
    USE SIGNAL ;
    SHAPE ABUTMENT ;
    PORT
      LAYER M3 ;
      RECT 96.399 128.510 96.417 128.564 ;
    END
  END r0_rd_out[423]
  PIN r0_rd_out[424]
    DIRECTION OUTPUT ;
    USE SIGNAL ;
    SHAPE ABUTMENT ;
    PORT
      LAYER M3 ;
      RECT 96.975 128.510 96.993 128.564 ;
    END
  END r0_rd_out[424]
  PIN r0_rd_out[425]
    DIRECTION OUTPUT ;
    USE SIGNAL ;
    SHAPE ABUTMENT ;
    PORT
      LAYER M3 ;
      RECT 97.551 128.510 97.569 128.564 ;
    END
  END r0_rd_out[425]
  PIN r0_rd_out[426]
    DIRECTION OUTPUT ;
    USE SIGNAL ;
    SHAPE ABUTMENT ;
    PORT
      LAYER M3 ;
      RECT 98.127 128.510 98.145 128.564 ;
    END
  END r0_rd_out[426]
  PIN r0_rd_out[427]
    DIRECTION OUTPUT ;
    USE SIGNAL ;
    SHAPE ABUTMENT ;
    PORT
      LAYER M3 ;
      RECT 98.703 128.510 98.721 128.564 ;
    END
  END r0_rd_out[427]
  PIN r0_rd_out[428]
    DIRECTION OUTPUT ;
    USE SIGNAL ;
    SHAPE ABUTMENT ;
    PORT
      LAYER M3 ;
      RECT 99.279 128.510 99.297 128.564 ;
    END
  END r0_rd_out[428]
  PIN r0_rd_out[429]
    DIRECTION OUTPUT ;
    USE SIGNAL ;
    SHAPE ABUTMENT ;
    PORT
      LAYER M3 ;
      RECT 99.855 128.510 99.873 128.564 ;
    END
  END r0_rd_out[429]
  PIN r0_rd_out[430]
    DIRECTION OUTPUT ;
    USE SIGNAL ;
    SHAPE ABUTMENT ;
    PORT
      LAYER M3 ;
      RECT 100.431 128.510 100.449 128.564 ;
    END
  END r0_rd_out[430]
  PIN r0_rd_out[431]
    DIRECTION OUTPUT ;
    USE SIGNAL ;
    SHAPE ABUTMENT ;
    PORT
      LAYER M3 ;
      RECT 101.007 128.510 101.025 128.564 ;
    END
  END r0_rd_out[431]
  PIN r0_rd_out[432]
    DIRECTION OUTPUT ;
    USE SIGNAL ;
    SHAPE ABUTMENT ;
    PORT
      LAYER M3 ;
      RECT 101.583 128.510 101.601 128.564 ;
    END
  END r0_rd_out[432]
  PIN r0_rd_out[433]
    DIRECTION OUTPUT ;
    USE SIGNAL ;
    SHAPE ABUTMENT ;
    PORT
      LAYER M3 ;
      RECT 102.159 128.510 102.177 128.564 ;
    END
  END r0_rd_out[433]
  PIN r0_rd_out[434]
    DIRECTION OUTPUT ;
    USE SIGNAL ;
    SHAPE ABUTMENT ;
    PORT
      LAYER M3 ;
      RECT 102.735 128.510 102.753 128.564 ;
    END
  END r0_rd_out[434]
  PIN r0_rd_out[435]
    DIRECTION OUTPUT ;
    USE SIGNAL ;
    SHAPE ABUTMENT ;
    PORT
      LAYER M3 ;
      RECT 103.311 128.510 103.329 128.564 ;
    END
  END r0_rd_out[435]
  PIN r0_rd_out[436]
    DIRECTION OUTPUT ;
    USE SIGNAL ;
    SHAPE ABUTMENT ;
    PORT
      LAYER M3 ;
      RECT 103.887 128.510 103.905 128.564 ;
    END
  END r0_rd_out[436]
  PIN r0_rd_out[437]
    DIRECTION OUTPUT ;
    USE SIGNAL ;
    SHAPE ABUTMENT ;
    PORT
      LAYER M3 ;
      RECT 104.463 128.510 104.481 128.564 ;
    END
  END r0_rd_out[437]
  PIN r0_rd_out[438]
    DIRECTION OUTPUT ;
    USE SIGNAL ;
    SHAPE ABUTMENT ;
    PORT
      LAYER M3 ;
      RECT 105.039 128.510 105.057 128.564 ;
    END
  END r0_rd_out[438]
  PIN r0_rd_out[439]
    DIRECTION OUTPUT ;
    USE SIGNAL ;
    SHAPE ABUTMENT ;
    PORT
      LAYER M3 ;
      RECT 105.615 128.510 105.633 128.564 ;
    END
  END r0_rd_out[439]
  PIN r0_rd_out[440]
    DIRECTION OUTPUT ;
    USE SIGNAL ;
    SHAPE ABUTMENT ;
    PORT
      LAYER M3 ;
      RECT 106.191 128.510 106.209 128.564 ;
    END
  END r0_rd_out[440]
  PIN r0_rd_out[441]
    DIRECTION OUTPUT ;
    USE SIGNAL ;
    SHAPE ABUTMENT ;
    PORT
      LAYER M3 ;
      RECT 106.767 128.510 106.785 128.564 ;
    END
  END r0_rd_out[441]
  PIN r0_rd_out[442]
    DIRECTION OUTPUT ;
    USE SIGNAL ;
    SHAPE ABUTMENT ;
    PORT
      LAYER M3 ;
      RECT 107.343 128.510 107.361 128.564 ;
    END
  END r0_rd_out[442]
  PIN r0_rd_out[443]
    DIRECTION OUTPUT ;
    USE SIGNAL ;
    SHAPE ABUTMENT ;
    PORT
      LAYER M3 ;
      RECT 107.919 128.510 107.937 128.564 ;
    END
  END r0_rd_out[443]
  PIN r0_rd_out[444]
    DIRECTION OUTPUT ;
    USE SIGNAL ;
    SHAPE ABUTMENT ;
    PORT
      LAYER M3 ;
      RECT 108.495 128.510 108.513 128.564 ;
    END
  END r0_rd_out[444]
  PIN r0_rd_out[445]
    DIRECTION OUTPUT ;
    USE SIGNAL ;
    SHAPE ABUTMENT ;
    PORT
      LAYER M3 ;
      RECT 109.071 128.510 109.089 128.564 ;
    END
  END r0_rd_out[445]
  PIN r0_rd_out[446]
    DIRECTION OUTPUT ;
    USE SIGNAL ;
    SHAPE ABUTMENT ;
    PORT
      LAYER M3 ;
      RECT 109.647 128.510 109.665 128.564 ;
    END
  END r0_rd_out[446]
  PIN r0_rd_out[447]
    DIRECTION OUTPUT ;
    USE SIGNAL ;
    SHAPE ABUTMENT ;
    PORT
      LAYER M3 ;
      RECT 110.223 128.510 110.241 128.564 ;
    END
  END r0_rd_out[447]
  PIN r0_rd_out[448]
    DIRECTION OUTPUT ;
    USE SIGNAL ;
    SHAPE ABUTMENT ;
    PORT
      LAYER M3 ;
      RECT 110.799 128.510 110.817 128.564 ;
    END
  END r0_rd_out[448]
  PIN r0_rd_out[449]
    DIRECTION OUTPUT ;
    USE SIGNAL ;
    SHAPE ABUTMENT ;
    PORT
      LAYER M3 ;
      RECT 111.375 128.510 111.393 128.564 ;
    END
  END r0_rd_out[449]
  PIN r0_rd_out[450]
    DIRECTION OUTPUT ;
    USE SIGNAL ;
    SHAPE ABUTMENT ;
    PORT
      LAYER M3 ;
      RECT 111.951 128.510 111.969 128.564 ;
    END
  END r0_rd_out[450]
  PIN r0_rd_out[451]
    DIRECTION OUTPUT ;
    USE SIGNAL ;
    SHAPE ABUTMENT ;
    PORT
      LAYER M3 ;
      RECT 112.527 128.510 112.545 128.564 ;
    END
  END r0_rd_out[451]
  PIN r0_rd_out[452]
    DIRECTION OUTPUT ;
    USE SIGNAL ;
    SHAPE ABUTMENT ;
    PORT
      LAYER M3 ;
      RECT 113.103 128.510 113.121 128.564 ;
    END
  END r0_rd_out[452]
  PIN r0_rd_out[453]
    DIRECTION OUTPUT ;
    USE SIGNAL ;
    SHAPE ABUTMENT ;
    PORT
      LAYER M3 ;
      RECT 113.679 128.510 113.697 128.564 ;
    END
  END r0_rd_out[453]
  PIN r0_rd_out[454]
    DIRECTION OUTPUT ;
    USE SIGNAL ;
    SHAPE ABUTMENT ;
    PORT
      LAYER M3 ;
      RECT 114.255 128.510 114.273 128.564 ;
    END
  END r0_rd_out[454]
  PIN r0_rd_out[455]
    DIRECTION OUTPUT ;
    USE SIGNAL ;
    SHAPE ABUTMENT ;
    PORT
      LAYER M3 ;
      RECT 114.831 128.510 114.849 128.564 ;
    END
  END r0_rd_out[455]
  PIN r0_rd_out[456]
    DIRECTION OUTPUT ;
    USE SIGNAL ;
    SHAPE ABUTMENT ;
    PORT
      LAYER M3 ;
      RECT 115.407 128.510 115.425 128.564 ;
    END
  END r0_rd_out[456]
  PIN r0_rd_out[457]
    DIRECTION OUTPUT ;
    USE SIGNAL ;
    SHAPE ABUTMENT ;
    PORT
      LAYER M3 ;
      RECT 115.983 128.510 116.001 128.564 ;
    END
  END r0_rd_out[457]
  PIN r0_rd_out[458]
    DIRECTION OUTPUT ;
    USE SIGNAL ;
    SHAPE ABUTMENT ;
    PORT
      LAYER M3 ;
      RECT 116.559 128.510 116.577 128.564 ;
    END
  END r0_rd_out[458]
  PIN r0_rd_out[459]
    DIRECTION OUTPUT ;
    USE SIGNAL ;
    SHAPE ABUTMENT ;
    PORT
      LAYER M3 ;
      RECT 117.135 128.510 117.153 128.564 ;
    END
  END r0_rd_out[459]
  PIN r0_rd_out[460]
    DIRECTION OUTPUT ;
    USE SIGNAL ;
    SHAPE ABUTMENT ;
    PORT
      LAYER M3 ;
      RECT 117.711 128.510 117.729 128.564 ;
    END
  END r0_rd_out[460]
  PIN r0_rd_out[461]
    DIRECTION OUTPUT ;
    USE SIGNAL ;
    SHAPE ABUTMENT ;
    PORT
      LAYER M3 ;
      RECT 118.287 128.510 118.305 128.564 ;
    END
  END r0_rd_out[461]
  PIN r0_rd_out[462]
    DIRECTION OUTPUT ;
    USE SIGNAL ;
    SHAPE ABUTMENT ;
    PORT
      LAYER M3 ;
      RECT 118.863 128.510 118.881 128.564 ;
    END
  END r0_rd_out[462]
  PIN r0_rd_out[463]
    DIRECTION OUTPUT ;
    USE SIGNAL ;
    SHAPE ABUTMENT ;
    PORT
      LAYER M3 ;
      RECT 119.439 128.510 119.457 128.564 ;
    END
  END r0_rd_out[463]
  PIN r0_rd_out[464]
    DIRECTION OUTPUT ;
    USE SIGNAL ;
    SHAPE ABUTMENT ;
    PORT
      LAYER M3 ;
      RECT 120.015 128.510 120.033 128.564 ;
    END
  END r0_rd_out[464]
  PIN r0_rd_out[465]
    DIRECTION OUTPUT ;
    USE SIGNAL ;
    SHAPE ABUTMENT ;
    PORT
      LAYER M3 ;
      RECT 120.591 128.510 120.609 128.564 ;
    END
  END r0_rd_out[465]
  PIN r0_rd_out[466]
    DIRECTION OUTPUT ;
    USE SIGNAL ;
    SHAPE ABUTMENT ;
    PORT
      LAYER M3 ;
      RECT 121.167 128.510 121.185 128.564 ;
    END
  END r0_rd_out[466]
  PIN r0_rd_out[467]
    DIRECTION OUTPUT ;
    USE SIGNAL ;
    SHAPE ABUTMENT ;
    PORT
      LAYER M3 ;
      RECT 121.743 128.510 121.761 128.564 ;
    END
  END r0_rd_out[467]
  PIN r0_rd_out[468]
    DIRECTION OUTPUT ;
    USE SIGNAL ;
    SHAPE ABUTMENT ;
    PORT
      LAYER M3 ;
      RECT 122.319 128.510 122.337 128.564 ;
    END
  END r0_rd_out[468]
  PIN r0_rd_out[469]
    DIRECTION OUTPUT ;
    USE SIGNAL ;
    SHAPE ABUTMENT ;
    PORT
      LAYER M3 ;
      RECT 122.895 128.510 122.913 128.564 ;
    END
  END r0_rd_out[469]
  PIN r0_rd_out[470]
    DIRECTION OUTPUT ;
    USE SIGNAL ;
    SHAPE ABUTMENT ;
    PORT
      LAYER M3 ;
      RECT 123.471 128.510 123.489 128.564 ;
    END
  END r0_rd_out[470]
  PIN r0_rd_out[471]
    DIRECTION OUTPUT ;
    USE SIGNAL ;
    SHAPE ABUTMENT ;
    PORT
      LAYER M3 ;
      RECT 124.047 128.510 124.065 128.564 ;
    END
  END r0_rd_out[471]
  PIN r0_rd_out[472]
    DIRECTION OUTPUT ;
    USE SIGNAL ;
    SHAPE ABUTMENT ;
    PORT
      LAYER M3 ;
      RECT 124.623 128.510 124.641 128.564 ;
    END
  END r0_rd_out[472]
  PIN r0_rd_out[473]
    DIRECTION OUTPUT ;
    USE SIGNAL ;
    SHAPE ABUTMENT ;
    PORT
      LAYER M3 ;
      RECT 125.199 128.510 125.217 128.564 ;
    END
  END r0_rd_out[473]
  PIN r0_rd_out[474]
    DIRECTION OUTPUT ;
    USE SIGNAL ;
    SHAPE ABUTMENT ;
    PORT
      LAYER M3 ;
      RECT 125.775 128.510 125.793 128.564 ;
    END
  END r0_rd_out[474]
  PIN r0_rd_out[475]
    DIRECTION OUTPUT ;
    USE SIGNAL ;
    SHAPE ABUTMENT ;
    PORT
      LAYER M3 ;
      RECT 126.351 128.510 126.369 128.564 ;
    END
  END r0_rd_out[475]
  PIN r0_rd_out[476]
    DIRECTION OUTPUT ;
    USE SIGNAL ;
    SHAPE ABUTMENT ;
    PORT
      LAYER M3 ;
      RECT 126.927 128.510 126.945 128.564 ;
    END
  END r0_rd_out[476]
  PIN r0_rd_out[477]
    DIRECTION OUTPUT ;
    USE SIGNAL ;
    SHAPE ABUTMENT ;
    PORT
      LAYER M3 ;
      RECT 127.503 128.510 127.521 128.564 ;
    END
  END r0_rd_out[477]
  PIN r0_rd_out[478]
    DIRECTION OUTPUT ;
    USE SIGNAL ;
    SHAPE ABUTMENT ;
    PORT
      LAYER M3 ;
      RECT 128.079 128.510 128.097 128.564 ;
    END
  END r0_rd_out[478]
  PIN r0_rd_out[479]
    DIRECTION OUTPUT ;
    USE SIGNAL ;
    SHAPE ABUTMENT ;
    PORT
      LAYER M3 ;
      RECT 128.655 128.510 128.673 128.564 ;
    END
  END r0_rd_out[479]
  PIN r0_rd_out[480]
    DIRECTION OUTPUT ;
    USE SIGNAL ;
    SHAPE ABUTMENT ;
    PORT
      LAYER M3 ;
      RECT 129.231 128.510 129.249 128.564 ;
    END
  END r0_rd_out[480]
  PIN r0_rd_out[481]
    DIRECTION OUTPUT ;
    USE SIGNAL ;
    SHAPE ABUTMENT ;
    PORT
      LAYER M3 ;
      RECT 129.807 128.510 129.825 128.564 ;
    END
  END r0_rd_out[481]
  PIN r0_rd_out[482]
    DIRECTION OUTPUT ;
    USE SIGNAL ;
    SHAPE ABUTMENT ;
    PORT
      LAYER M3 ;
      RECT 130.383 128.510 130.401 128.564 ;
    END
  END r0_rd_out[482]
  PIN r0_rd_out[483]
    DIRECTION OUTPUT ;
    USE SIGNAL ;
    SHAPE ABUTMENT ;
    PORT
      LAYER M3 ;
      RECT 130.959 128.510 130.977 128.564 ;
    END
  END r0_rd_out[483]
  PIN r0_rd_out[484]
    DIRECTION OUTPUT ;
    USE SIGNAL ;
    SHAPE ABUTMENT ;
    PORT
      LAYER M3 ;
      RECT 131.535 128.510 131.553 128.564 ;
    END
  END r0_rd_out[484]
  PIN r0_rd_out[485]
    DIRECTION OUTPUT ;
    USE SIGNAL ;
    SHAPE ABUTMENT ;
    PORT
      LAYER M3 ;
      RECT 132.111 128.510 132.129 128.564 ;
    END
  END r0_rd_out[485]
  PIN r0_rd_out[486]
    DIRECTION OUTPUT ;
    USE SIGNAL ;
    SHAPE ABUTMENT ;
    PORT
      LAYER M3 ;
      RECT 132.687 128.510 132.705 128.564 ;
    END
  END r0_rd_out[486]
  PIN r0_rd_out[487]
    DIRECTION OUTPUT ;
    USE SIGNAL ;
    SHAPE ABUTMENT ;
    PORT
      LAYER M3 ;
      RECT 133.263 128.510 133.281 128.564 ;
    END
  END r0_rd_out[487]
  PIN r0_rd_out[488]
    DIRECTION OUTPUT ;
    USE SIGNAL ;
    SHAPE ABUTMENT ;
    PORT
      LAYER M3 ;
      RECT 133.839 128.510 133.857 128.564 ;
    END
  END r0_rd_out[488]
  PIN r0_rd_out[489]
    DIRECTION OUTPUT ;
    USE SIGNAL ;
    SHAPE ABUTMENT ;
    PORT
      LAYER M3 ;
      RECT 134.415 128.510 134.433 128.564 ;
    END
  END r0_rd_out[489]
  PIN r0_rd_out[490]
    DIRECTION OUTPUT ;
    USE SIGNAL ;
    SHAPE ABUTMENT ;
    PORT
      LAYER M3 ;
      RECT 134.991 128.510 135.009 128.564 ;
    END
  END r0_rd_out[490]
  PIN r0_rd_out[491]
    DIRECTION OUTPUT ;
    USE SIGNAL ;
    SHAPE ABUTMENT ;
    PORT
      LAYER M3 ;
      RECT 135.567 128.510 135.585 128.564 ;
    END
  END r0_rd_out[491]
  PIN r0_rd_out[492]
    DIRECTION OUTPUT ;
    USE SIGNAL ;
    SHAPE ABUTMENT ;
    PORT
      LAYER M3 ;
      RECT 136.143 128.510 136.161 128.564 ;
    END
  END r0_rd_out[492]
  PIN r0_rd_out[493]
    DIRECTION OUTPUT ;
    USE SIGNAL ;
    SHAPE ABUTMENT ;
    PORT
      LAYER M3 ;
      RECT 136.719 128.510 136.737 128.564 ;
    END
  END r0_rd_out[493]
  PIN r0_rd_out[494]
    DIRECTION OUTPUT ;
    USE SIGNAL ;
    SHAPE ABUTMENT ;
    PORT
      LAYER M3 ;
      RECT 137.295 128.510 137.313 128.564 ;
    END
  END r0_rd_out[494]
  PIN r0_rd_out[495]
    DIRECTION OUTPUT ;
    USE SIGNAL ;
    SHAPE ABUTMENT ;
    PORT
      LAYER M3 ;
      RECT 137.871 128.510 137.889 128.564 ;
    END
  END r0_rd_out[495]
  PIN r0_rd_out[496]
    DIRECTION OUTPUT ;
    USE SIGNAL ;
    SHAPE ABUTMENT ;
    PORT
      LAYER M3 ;
      RECT 138.447 128.510 138.465 128.564 ;
    END
  END r0_rd_out[496]
  PIN r0_rd_out[497]
    DIRECTION OUTPUT ;
    USE SIGNAL ;
    SHAPE ABUTMENT ;
    PORT
      LAYER M3 ;
      RECT 139.023 128.510 139.041 128.564 ;
    END
  END r0_rd_out[497]
  PIN r0_rd_out[498]
    DIRECTION OUTPUT ;
    USE SIGNAL ;
    SHAPE ABUTMENT ;
    PORT
      LAYER M3 ;
      RECT 139.599 128.510 139.617 128.564 ;
    END
  END r0_rd_out[498]
  PIN r0_rd_out[499]
    DIRECTION OUTPUT ;
    USE SIGNAL ;
    SHAPE ABUTMENT ;
    PORT
      LAYER M3 ;
      RECT 140.175 128.510 140.193 128.564 ;
    END
  END r0_rd_out[499]
  PIN r0_rd_out[500]
    DIRECTION OUTPUT ;
    USE SIGNAL ;
    SHAPE ABUTMENT ;
    PORT
      LAYER M3 ;
      RECT 140.751 128.510 140.769 128.564 ;
    END
  END r0_rd_out[500]
  PIN r0_rd_out[501]
    DIRECTION OUTPUT ;
    USE SIGNAL ;
    SHAPE ABUTMENT ;
    PORT
      LAYER M3 ;
      RECT 141.327 128.510 141.345 128.564 ;
    END
  END r0_rd_out[501]
  PIN r0_rd_out[502]
    DIRECTION OUTPUT ;
    USE SIGNAL ;
    SHAPE ABUTMENT ;
    PORT
      LAYER M3 ;
      RECT 141.903 128.510 141.921 128.564 ;
    END
  END r0_rd_out[502]
  PIN r0_rd_out[503]
    DIRECTION OUTPUT ;
    USE SIGNAL ;
    SHAPE ABUTMENT ;
    PORT
      LAYER M3 ;
      RECT 142.479 128.510 142.497 128.564 ;
    END
  END r0_rd_out[503]
  PIN r0_rd_out[504]
    DIRECTION OUTPUT ;
    USE SIGNAL ;
    SHAPE ABUTMENT ;
    PORT
      LAYER M3 ;
      RECT 143.055 128.510 143.073 128.564 ;
    END
  END r0_rd_out[504]
  PIN r0_rd_out[505]
    DIRECTION OUTPUT ;
    USE SIGNAL ;
    SHAPE ABUTMENT ;
    PORT
      LAYER M3 ;
      RECT 143.631 128.510 143.649 128.564 ;
    END
  END r0_rd_out[505]
  PIN r0_rd_out[506]
    DIRECTION OUTPUT ;
    USE SIGNAL ;
    SHAPE ABUTMENT ;
    PORT
      LAYER M3 ;
      RECT 144.207 128.510 144.225 128.564 ;
    END
  END r0_rd_out[506]
  PIN r0_rd_out[507]
    DIRECTION OUTPUT ;
    USE SIGNAL ;
    SHAPE ABUTMENT ;
    PORT
      LAYER M3 ;
      RECT 144.783 128.510 144.801 128.564 ;
    END
  END r0_rd_out[507]
  PIN r0_rd_out[508]
    DIRECTION OUTPUT ;
    USE SIGNAL ;
    SHAPE ABUTMENT ;
    PORT
      LAYER M3 ;
      RECT 145.359 128.510 145.377 128.564 ;
    END
  END r0_rd_out[508]
  PIN r0_rd_out[509]
    DIRECTION OUTPUT ;
    USE SIGNAL ;
    SHAPE ABUTMENT ;
    PORT
      LAYER M3 ;
      RECT 145.935 128.510 145.953 128.564 ;
    END
  END r0_rd_out[509]
  PIN r0_rd_out[510]
    DIRECTION OUTPUT ;
    USE SIGNAL ;
    SHAPE ABUTMENT ;
    PORT
      LAYER M3 ;
      RECT 146.511 128.510 146.529 128.564 ;
    END
  END r0_rd_out[510]
  PIN r0_rd_out[511]
    DIRECTION OUTPUT ;
    USE SIGNAL ;
    SHAPE ABUTMENT ;
    PORT
      LAYER M3 ;
      RECT 147.087 128.510 147.105 128.564 ;
    END
  END r0_rd_out[511]
  PIN w0_addr_in[0]
    DIRECTION INPUT ;
    USE SIGNAL ;
    SHAPE ABUTMENT ;
    PORT
      LAYER M4 ;
      RECT 0.000 117.012 0.072 117.036 ;
    END
  END w0_addr_in[0]
  PIN w0_addr_in[1]
    DIRECTION INPUT ;
    USE SIGNAL ;
    SHAPE ABUTMENT ;
    PORT
      LAYER M4 ;
      RECT 0.000 117.924 0.072 117.948 ;
    END
  END w0_addr_in[1]
  PIN w0_addr_in[2]
    DIRECTION INPUT ;
    USE SIGNAL ;
    SHAPE ABUTMENT ;
    PORT
      LAYER M4 ;
      RECT 0.000 118.836 0.072 118.860 ;
    END
  END w0_addr_in[2]
  PIN w0_addr_in[3]
    DIRECTION INPUT ;
    USE SIGNAL ;
    SHAPE ABUTMENT ;
    PORT
      LAYER M4 ;
      RECT 0.000 119.748 0.072 119.772 ;
    END
  END w0_addr_in[3]
  PIN w0_addr_in[4]
    DIRECTION INPUT ;
    USE SIGNAL ;
    SHAPE ABUTMENT ;
    PORT
      LAYER M4 ;
      RECT 0.000 120.660 0.072 120.684 ;
    END
  END w0_addr_in[4]
  PIN w0_addr_in[5]
    DIRECTION INPUT ;
    USE SIGNAL ;
    SHAPE ABUTMENT ;
    PORT
      LAYER M4 ;
      RECT 154.204 117.012 154.276 117.036 ;
    END
  END w0_addr_in[5]
  PIN w0_addr_in[6]
    DIRECTION INPUT ;
    USE SIGNAL ;
    SHAPE ABUTMENT ;
    PORT
      LAYER M4 ;
      RECT 154.204 117.924 154.276 117.948 ;
    END
  END w0_addr_in[6]
  PIN w0_addr_in[7]
    DIRECTION INPUT ;
    USE SIGNAL ;
    SHAPE ABUTMENT ;
    PORT
      LAYER M4 ;
      RECT 154.204 118.836 154.276 118.860 ;
    END
  END w0_addr_in[7]
  PIN w0_addr_in[8]
    DIRECTION INPUT ;
    USE SIGNAL ;
    SHAPE ABUTMENT ;
    PORT
      LAYER M4 ;
      RECT 154.204 119.748 154.276 119.772 ;
    END
  END w0_addr_in[8]
  PIN r0_addr_in[0]
    DIRECTION INPUT ;
    USE SIGNAL ;
    SHAPE ABUTMENT ;
    PORT
      LAYER M4 ;
      RECT 0.000 121.572 0.072 121.596 ;
    END
  END r0_addr_in[0]
  PIN r0_addr_in[1]
    DIRECTION INPUT ;
    USE SIGNAL ;
    SHAPE ABUTMENT ;
    PORT
      LAYER M4 ;
      RECT 0.000 122.484 0.072 122.508 ;
    END
  END r0_addr_in[1]
  PIN r0_addr_in[2]
    DIRECTION INPUT ;
    USE SIGNAL ;
    SHAPE ABUTMENT ;
    PORT
      LAYER M4 ;
      RECT 0.000 123.396 0.072 123.420 ;
    END
  END r0_addr_in[2]
  PIN r0_addr_in[3]
    DIRECTION INPUT ;
    USE SIGNAL ;
    SHAPE ABUTMENT ;
    PORT
      LAYER M4 ;
      RECT 0.000 124.308 0.072 124.332 ;
    END
  END r0_addr_in[3]
  PIN r0_addr_in[4]
    DIRECTION INPUT ;
    USE SIGNAL ;
    SHAPE ABUTMENT ;
    PORT
      LAYER M4 ;
      RECT 0.000 125.220 0.072 125.244 ;
    END
  END r0_addr_in[4]
  PIN r0_addr_in[5]
    DIRECTION INPUT ;
    USE SIGNAL ;
    SHAPE ABUTMENT ;
    PORT
      LAYER M4 ;
      RECT 154.204 120.660 154.276 120.684 ;
    END
  END r0_addr_in[5]
  PIN r0_addr_in[6]
    DIRECTION INPUT ;
    USE SIGNAL ;
    SHAPE ABUTMENT ;
    PORT
      LAYER M4 ;
      RECT 154.204 121.572 154.276 121.596 ;
    END
  END r0_addr_in[6]
  PIN r0_addr_in[7]
    DIRECTION INPUT ;
    USE SIGNAL ;
    SHAPE ABUTMENT ;
    PORT
      LAYER M4 ;
      RECT 154.204 122.484 154.276 122.508 ;
    END
  END r0_addr_in[7]
  PIN r0_addr_in[8]
    DIRECTION INPUT ;
    USE SIGNAL ;
    SHAPE ABUTMENT ;
    PORT
      LAYER M4 ;
      RECT 154.204 123.396 154.276 123.420 ;
    END
  END r0_addr_in[8]
  PIN w0_we_in
    DIRECTION INPUT ;
    USE SIGNAL ;
    SHAPE ABUTMENT ;
    PORT
      LAYER M3 ;
      RECT 147.663 128.510 147.681 128.564 ;
    END
  END w0_we_in
  PIN w0_ce_in
    DIRECTION INPUT ;
    USE SIGNAL ;
    SHAPE ABUTMENT ;
    PORT
      LAYER M3 ;
      RECT 148.239 128.510 148.257 128.564 ;
    END
  END w0_ce_in
  PIN w0_clk
    DIRECTION INPUT ;
    USE SIGNAL ;
    SHAPE ABUTMENT ;
    PORT
      LAYER M3 ;
      RECT 148.815 128.510 148.833 128.564 ;
    END
  END w0_clk
  PIN r0_ce_in
    DIRECTION INPUT ;
    USE SIGNAL ;
    SHAPE ABUTMENT ;
    PORT
      LAYER M3 ;
      RECT 149.391 128.510 149.409 128.564 ;
    END
  END r0_ce_in
  PIN r0_clk
    DIRECTION INPUT ;
    USE SIGNAL ;
    SHAPE ABUTMENT ;
    PORT
      LAYER M3 ;
      RECT 149.967 128.510 149.985 128.564 ;
    END
  END r0_clk
  PIN VSS
    DIRECTION INOUT ;
    USE GROUND ;
    PORT
      LAYER M4 ;
      RECT 0.216 0.240 154.060 0.336 ;
      RECT 0.216 1.008 154.060 1.104 ;
      RECT 0.216 1.776 154.060 1.872 ;
      RECT 0.216 2.544 154.060 2.640 ;
      RECT 0.216 3.312 154.060 3.408 ;
      RECT 0.216 4.080 154.060 4.176 ;
      RECT 0.216 4.848 154.060 4.944 ;
      RECT 0.216 5.616 154.060 5.712 ;
      RECT 0.216 6.384 154.060 6.480 ;
      RECT 0.216 7.152 154.060 7.248 ;
      RECT 0.216 7.920 154.060 8.016 ;
      RECT 0.216 8.688 154.060 8.784 ;
      RECT 0.216 9.456 154.060 9.552 ;
      RECT 0.216 10.224 154.060 10.320 ;
      RECT 0.216 10.992 154.060 11.088 ;
      RECT 0.216 11.760 154.060 11.856 ;
      RECT 0.216 12.528 154.060 12.624 ;
      RECT 0.216 13.296 154.060 13.392 ;
      RECT 0.216 14.064 154.060 14.160 ;
      RECT 0.216 14.832 154.060 14.928 ;
      RECT 0.216 15.600 154.060 15.696 ;
      RECT 0.216 16.368 154.060 16.464 ;
      RECT 0.216 17.136 154.060 17.232 ;
      RECT 0.216 17.904 154.060 18.000 ;
      RECT 0.216 18.672 154.060 18.768 ;
      RECT 0.216 19.440 154.060 19.536 ;
      RECT 0.216 20.208 154.060 20.304 ;
      RECT 0.216 20.976 154.060 21.072 ;
      RECT 0.216 21.744 154.060 21.840 ;
      RECT 0.216 22.512 154.060 22.608 ;
      RECT 0.216 23.280 154.060 23.376 ;
      RECT 0.216 24.048 154.060 24.144 ;
      RECT 0.216 24.816 154.060 24.912 ;
      RECT 0.216 25.584 154.060 25.680 ;
      RECT 0.216 26.352 154.060 26.448 ;
      RECT 0.216 27.120 154.060 27.216 ;
      RECT 0.216 27.888 154.060 27.984 ;
      RECT 0.216 28.656 154.060 28.752 ;
      RECT 0.216 29.424 154.060 29.520 ;
      RECT 0.216 30.192 154.060 30.288 ;
      RECT 0.216 30.960 154.060 31.056 ;
      RECT 0.216 31.728 154.060 31.824 ;
      RECT 0.216 32.496 154.060 32.592 ;
      RECT 0.216 33.264 154.060 33.360 ;
      RECT 0.216 34.032 154.060 34.128 ;
      RECT 0.216 34.800 154.060 34.896 ;
      RECT 0.216 35.568 154.060 35.664 ;
      RECT 0.216 36.336 154.060 36.432 ;
      RECT 0.216 37.104 154.060 37.200 ;
      RECT 0.216 37.872 154.060 37.968 ;
      RECT 0.216 38.640 154.060 38.736 ;
      RECT 0.216 39.408 154.060 39.504 ;
      RECT 0.216 40.176 154.060 40.272 ;
      RECT 0.216 40.944 154.060 41.040 ;
      RECT 0.216 41.712 154.060 41.808 ;
      RECT 0.216 42.480 154.060 42.576 ;
      RECT 0.216 43.248 154.060 43.344 ;
      RECT 0.216 44.016 154.060 44.112 ;
      RECT 0.216 44.784 154.060 44.880 ;
      RECT 0.216 45.552 154.060 45.648 ;
      RECT 0.216 46.320 154.060 46.416 ;
      RECT 0.216 47.088 154.060 47.184 ;
      RECT 0.216 47.856 154.060 47.952 ;
      RECT 0.216 48.624 154.060 48.720 ;
      RECT 0.216 49.392 154.060 49.488 ;
      RECT 0.216 50.160 154.060 50.256 ;
      RECT 0.216 50.928 154.060 51.024 ;
      RECT 0.216 51.696 154.060 51.792 ;
      RECT 0.216 52.464 154.060 52.560 ;
      RECT 0.216 53.232 154.060 53.328 ;
      RECT 0.216 54.000 154.060 54.096 ;
      RECT 0.216 54.768 154.060 54.864 ;
      RECT 0.216 55.536 154.060 55.632 ;
      RECT 0.216 56.304 154.060 56.400 ;
      RECT 0.216 57.072 154.060 57.168 ;
      RECT 0.216 57.840 154.060 57.936 ;
      RECT 0.216 58.608 154.060 58.704 ;
      RECT 0.216 59.376 154.060 59.472 ;
      RECT 0.216 60.144 154.060 60.240 ;
      RECT 0.216 60.912 154.060 61.008 ;
      RECT 0.216 61.680 154.060 61.776 ;
      RECT 0.216 62.448 154.060 62.544 ;
      RECT 0.216 63.216 154.060 63.312 ;
      RECT 0.216 63.984 154.060 64.080 ;
      RECT 0.216 64.752 154.060 64.848 ;
      RECT 0.216 65.520 154.060 65.616 ;
      RECT 0.216 66.288 154.060 66.384 ;
      RECT 0.216 67.056 154.060 67.152 ;
      RECT 0.216 67.824 154.060 67.920 ;
      RECT 0.216 68.592 154.060 68.688 ;
      RECT 0.216 69.360 154.060 69.456 ;
      RECT 0.216 70.128 154.060 70.224 ;
      RECT 0.216 70.896 154.060 70.992 ;
      RECT 0.216 71.664 154.060 71.760 ;
      RECT 0.216 72.432 154.060 72.528 ;
      RECT 0.216 73.200 154.060 73.296 ;
      RECT 0.216 73.968 154.060 74.064 ;
      RECT 0.216 74.736 154.060 74.832 ;
      RECT 0.216 75.504 154.060 75.600 ;
      RECT 0.216 76.272 154.060 76.368 ;
      RECT 0.216 77.040 154.060 77.136 ;
      RECT 0.216 77.808 154.060 77.904 ;
      RECT 0.216 78.576 154.060 78.672 ;
      RECT 0.216 79.344 154.060 79.440 ;
      RECT 0.216 80.112 154.060 80.208 ;
      RECT 0.216 80.880 154.060 80.976 ;
      RECT 0.216 81.648 154.060 81.744 ;
      RECT 0.216 82.416 154.060 82.512 ;
      RECT 0.216 83.184 154.060 83.280 ;
      RECT 0.216 83.952 154.060 84.048 ;
      RECT 0.216 84.720 154.060 84.816 ;
      RECT 0.216 85.488 154.060 85.584 ;
      RECT 0.216 86.256 154.060 86.352 ;
      RECT 0.216 87.024 154.060 87.120 ;
      RECT 0.216 87.792 154.060 87.888 ;
      RECT 0.216 88.560 154.060 88.656 ;
      RECT 0.216 89.328 154.060 89.424 ;
      RECT 0.216 90.096 154.060 90.192 ;
      RECT 0.216 90.864 154.060 90.960 ;
      RECT 0.216 91.632 154.060 91.728 ;
      RECT 0.216 92.400 154.060 92.496 ;
      RECT 0.216 93.168 154.060 93.264 ;
      RECT 0.216 93.936 154.060 94.032 ;
      RECT 0.216 94.704 154.060 94.800 ;
      RECT 0.216 95.472 154.060 95.568 ;
      RECT 0.216 96.240 154.060 96.336 ;
      RECT 0.216 97.008 154.060 97.104 ;
      RECT 0.216 97.776 154.060 97.872 ;
      RECT 0.216 98.544 154.060 98.640 ;
      RECT 0.216 99.312 154.060 99.408 ;
      RECT 0.216 100.080 154.060 100.176 ;
      RECT 0.216 100.848 154.060 100.944 ;
      RECT 0.216 101.616 154.060 101.712 ;
      RECT 0.216 102.384 154.060 102.480 ;
      RECT 0.216 103.152 154.060 103.248 ;
      RECT 0.216 103.920 154.060 104.016 ;
      RECT 0.216 104.688 154.060 104.784 ;
      RECT 0.216 105.456 154.060 105.552 ;
      RECT 0.216 106.224 154.060 106.320 ;
      RECT 0.216 106.992 154.060 107.088 ;
      RECT 0.216 107.760 154.060 107.856 ;
      RECT 0.216 108.528 154.060 108.624 ;
      RECT 0.216 109.296 154.060 109.392 ;
      RECT 0.216 110.064 154.060 110.160 ;
      RECT 0.216 110.832 154.060 110.928 ;
      RECT 0.216 111.600 154.060 111.696 ;
      RECT 0.216 112.368 154.060 112.464 ;
      RECT 0.216 113.136 154.060 113.232 ;
      RECT 0.216 113.904 154.060 114.000 ;
      RECT 0.216 114.672 154.060 114.768 ;
      RECT 0.216 115.440 154.060 115.536 ;
      RECT 0.216 116.208 154.060 116.304 ;
      RECT 0.216 116.976 154.060 117.072 ;
      RECT 0.216 117.744 154.060 117.840 ;
      RECT 0.216 118.512 154.060 118.608 ;
      RECT 0.216 119.280 154.060 119.376 ;
      RECT 0.216 120.048 154.060 120.144 ;
      RECT 0.216 120.816 154.060 120.912 ;
      RECT 0.216 121.584 154.060 121.680 ;
      RECT 0.216 122.352 154.060 122.448 ;
      RECT 0.216 123.120 154.060 123.216 ;
      RECT 0.216 123.888 154.060 123.984 ;
      RECT 0.216 124.656 154.060 124.752 ;
      RECT 0.216 125.424 154.060 125.520 ;
      RECT 0.216 126.192 154.060 126.288 ;
      RECT 0.216 126.960 154.060 127.056 ;
      RECT 0.216 127.728 154.060 127.824 ;
    END
  END VSS
  PIN VDD
    DIRECTION INOUT ;
    USE POWER ;
    PORT
      LAYER M4 ;
      RECT 0.216 0.240 154.060 0.336 ;
      RECT 0.216 1.008 154.060 1.104 ;
      RECT 0.216 1.776 154.060 1.872 ;
      RECT 0.216 2.544 154.060 2.640 ;
      RECT 0.216 3.312 154.060 3.408 ;
      RECT 0.216 4.080 154.060 4.176 ;
      RECT 0.216 4.848 154.060 4.944 ;
      RECT 0.216 5.616 154.060 5.712 ;
      RECT 0.216 6.384 154.060 6.480 ;
      RECT 0.216 7.152 154.060 7.248 ;
      RECT 0.216 7.920 154.060 8.016 ;
      RECT 0.216 8.688 154.060 8.784 ;
      RECT 0.216 9.456 154.060 9.552 ;
      RECT 0.216 10.224 154.060 10.320 ;
      RECT 0.216 10.992 154.060 11.088 ;
      RECT 0.216 11.760 154.060 11.856 ;
      RECT 0.216 12.528 154.060 12.624 ;
      RECT 0.216 13.296 154.060 13.392 ;
      RECT 0.216 14.064 154.060 14.160 ;
      RECT 0.216 14.832 154.060 14.928 ;
      RECT 0.216 15.600 154.060 15.696 ;
      RECT 0.216 16.368 154.060 16.464 ;
      RECT 0.216 17.136 154.060 17.232 ;
      RECT 0.216 17.904 154.060 18.000 ;
      RECT 0.216 18.672 154.060 18.768 ;
      RECT 0.216 19.440 154.060 19.536 ;
      RECT 0.216 20.208 154.060 20.304 ;
      RECT 0.216 20.976 154.060 21.072 ;
      RECT 0.216 21.744 154.060 21.840 ;
      RECT 0.216 22.512 154.060 22.608 ;
      RECT 0.216 23.280 154.060 23.376 ;
      RECT 0.216 24.048 154.060 24.144 ;
      RECT 0.216 24.816 154.060 24.912 ;
      RECT 0.216 25.584 154.060 25.680 ;
      RECT 0.216 26.352 154.060 26.448 ;
      RECT 0.216 27.120 154.060 27.216 ;
      RECT 0.216 27.888 154.060 27.984 ;
      RECT 0.216 28.656 154.060 28.752 ;
      RECT 0.216 29.424 154.060 29.520 ;
      RECT 0.216 30.192 154.060 30.288 ;
      RECT 0.216 30.960 154.060 31.056 ;
      RECT 0.216 31.728 154.060 31.824 ;
      RECT 0.216 32.496 154.060 32.592 ;
      RECT 0.216 33.264 154.060 33.360 ;
      RECT 0.216 34.032 154.060 34.128 ;
      RECT 0.216 34.800 154.060 34.896 ;
      RECT 0.216 35.568 154.060 35.664 ;
      RECT 0.216 36.336 154.060 36.432 ;
      RECT 0.216 37.104 154.060 37.200 ;
      RECT 0.216 37.872 154.060 37.968 ;
      RECT 0.216 38.640 154.060 38.736 ;
      RECT 0.216 39.408 154.060 39.504 ;
      RECT 0.216 40.176 154.060 40.272 ;
      RECT 0.216 40.944 154.060 41.040 ;
      RECT 0.216 41.712 154.060 41.808 ;
      RECT 0.216 42.480 154.060 42.576 ;
      RECT 0.216 43.248 154.060 43.344 ;
      RECT 0.216 44.016 154.060 44.112 ;
      RECT 0.216 44.784 154.060 44.880 ;
      RECT 0.216 45.552 154.060 45.648 ;
      RECT 0.216 46.320 154.060 46.416 ;
      RECT 0.216 47.088 154.060 47.184 ;
      RECT 0.216 47.856 154.060 47.952 ;
      RECT 0.216 48.624 154.060 48.720 ;
      RECT 0.216 49.392 154.060 49.488 ;
      RECT 0.216 50.160 154.060 50.256 ;
      RECT 0.216 50.928 154.060 51.024 ;
      RECT 0.216 51.696 154.060 51.792 ;
      RECT 0.216 52.464 154.060 52.560 ;
      RECT 0.216 53.232 154.060 53.328 ;
      RECT 0.216 54.000 154.060 54.096 ;
      RECT 0.216 54.768 154.060 54.864 ;
      RECT 0.216 55.536 154.060 55.632 ;
      RECT 0.216 56.304 154.060 56.400 ;
      RECT 0.216 57.072 154.060 57.168 ;
      RECT 0.216 57.840 154.060 57.936 ;
      RECT 0.216 58.608 154.060 58.704 ;
      RECT 0.216 59.376 154.060 59.472 ;
      RECT 0.216 60.144 154.060 60.240 ;
      RECT 0.216 60.912 154.060 61.008 ;
      RECT 0.216 61.680 154.060 61.776 ;
      RECT 0.216 62.448 154.060 62.544 ;
      RECT 0.216 63.216 154.060 63.312 ;
      RECT 0.216 63.984 154.060 64.080 ;
      RECT 0.216 64.752 154.060 64.848 ;
      RECT 0.216 65.520 154.060 65.616 ;
      RECT 0.216 66.288 154.060 66.384 ;
      RECT 0.216 67.056 154.060 67.152 ;
      RECT 0.216 67.824 154.060 67.920 ;
      RECT 0.216 68.592 154.060 68.688 ;
      RECT 0.216 69.360 154.060 69.456 ;
      RECT 0.216 70.128 154.060 70.224 ;
      RECT 0.216 70.896 154.060 70.992 ;
      RECT 0.216 71.664 154.060 71.760 ;
      RECT 0.216 72.432 154.060 72.528 ;
      RECT 0.216 73.200 154.060 73.296 ;
      RECT 0.216 73.968 154.060 74.064 ;
      RECT 0.216 74.736 154.060 74.832 ;
      RECT 0.216 75.504 154.060 75.600 ;
      RECT 0.216 76.272 154.060 76.368 ;
      RECT 0.216 77.040 154.060 77.136 ;
      RECT 0.216 77.808 154.060 77.904 ;
      RECT 0.216 78.576 154.060 78.672 ;
      RECT 0.216 79.344 154.060 79.440 ;
      RECT 0.216 80.112 154.060 80.208 ;
      RECT 0.216 80.880 154.060 80.976 ;
      RECT 0.216 81.648 154.060 81.744 ;
      RECT 0.216 82.416 154.060 82.512 ;
      RECT 0.216 83.184 154.060 83.280 ;
      RECT 0.216 83.952 154.060 84.048 ;
      RECT 0.216 84.720 154.060 84.816 ;
      RECT 0.216 85.488 154.060 85.584 ;
      RECT 0.216 86.256 154.060 86.352 ;
      RECT 0.216 87.024 154.060 87.120 ;
      RECT 0.216 87.792 154.060 87.888 ;
      RECT 0.216 88.560 154.060 88.656 ;
      RECT 0.216 89.328 154.060 89.424 ;
      RECT 0.216 90.096 154.060 90.192 ;
      RECT 0.216 90.864 154.060 90.960 ;
      RECT 0.216 91.632 154.060 91.728 ;
      RECT 0.216 92.400 154.060 92.496 ;
      RECT 0.216 93.168 154.060 93.264 ;
      RECT 0.216 93.936 154.060 94.032 ;
      RECT 0.216 94.704 154.060 94.800 ;
      RECT 0.216 95.472 154.060 95.568 ;
      RECT 0.216 96.240 154.060 96.336 ;
      RECT 0.216 97.008 154.060 97.104 ;
      RECT 0.216 97.776 154.060 97.872 ;
      RECT 0.216 98.544 154.060 98.640 ;
      RECT 0.216 99.312 154.060 99.408 ;
      RECT 0.216 100.080 154.060 100.176 ;
      RECT 0.216 100.848 154.060 100.944 ;
      RECT 0.216 101.616 154.060 101.712 ;
      RECT 0.216 102.384 154.060 102.480 ;
      RECT 0.216 103.152 154.060 103.248 ;
      RECT 0.216 103.920 154.060 104.016 ;
      RECT 0.216 104.688 154.060 104.784 ;
      RECT 0.216 105.456 154.060 105.552 ;
      RECT 0.216 106.224 154.060 106.320 ;
      RECT 0.216 106.992 154.060 107.088 ;
      RECT 0.216 107.760 154.060 107.856 ;
      RECT 0.216 108.528 154.060 108.624 ;
      RECT 0.216 109.296 154.060 109.392 ;
      RECT 0.216 110.064 154.060 110.160 ;
      RECT 0.216 110.832 154.060 110.928 ;
      RECT 0.216 111.600 154.060 111.696 ;
      RECT 0.216 112.368 154.060 112.464 ;
      RECT 0.216 113.136 154.060 113.232 ;
      RECT 0.216 113.904 154.060 114.000 ;
      RECT 0.216 114.672 154.060 114.768 ;
      RECT 0.216 115.440 154.060 115.536 ;
      RECT 0.216 116.208 154.060 116.304 ;
      RECT 0.216 116.976 154.060 117.072 ;
      RECT 0.216 117.744 154.060 117.840 ;
      RECT 0.216 118.512 154.060 118.608 ;
      RECT 0.216 119.280 154.060 119.376 ;
      RECT 0.216 120.048 154.060 120.144 ;
      RECT 0.216 120.816 154.060 120.912 ;
      RECT 0.216 121.584 154.060 121.680 ;
      RECT 0.216 122.352 154.060 122.448 ;
      RECT 0.216 123.120 154.060 123.216 ;
      RECT 0.216 123.888 154.060 123.984 ;
      RECT 0.216 124.656 154.060 124.752 ;
      RECT 0.216 125.424 154.060 125.520 ;
      RECT 0.216 126.192 154.060 126.288 ;
      RECT 0.216 126.960 154.060 127.056 ;
      RECT 0.216 127.728 154.060 127.824 ;
    END
  END VDD
  OBS
    LAYER M1 ;
    RECT 0 0 154.276 128.564 ;
    LAYER M2 ;
    RECT 0 0 154.276 128.564 ;
    LAYER M3 ;
    RECT 0 0 154.276 128.564 ;
    LAYER M4 ;
    RECT 0 0 154.276 128.564 ;
  END
END fakeram_512x512_1r1w

END LIBRARY
